VERSION 5.7 ;
  NOWIREEXTENSIONATPIN ON ;
  DIVIDERCHAR "/" ;
  BUSBITCHARS "[]" ;
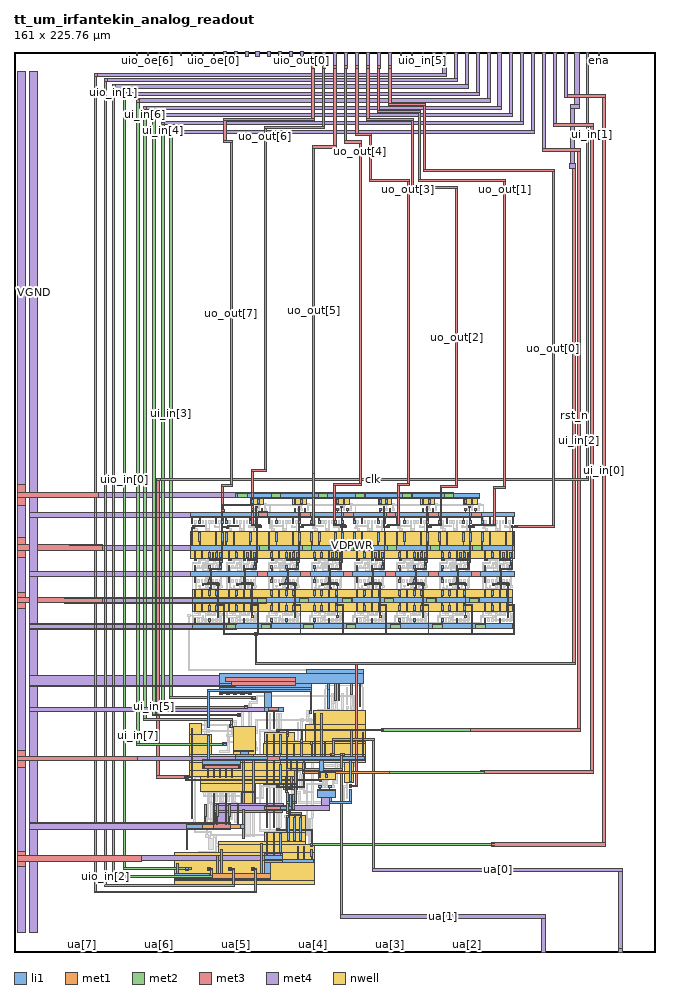
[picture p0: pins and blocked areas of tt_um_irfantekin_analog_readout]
MACRO tt_um_irfantekin_analog_readout
  CLASS BLOCK ;
  FOREIGN tt_um_irfantekin_analog_readout ;
  ORIGIN 0.000 0.000 ;
  SIZE 161.000 BY 225.760 ;
  PIN clk
    DIRECTION INPUT ;
    USE SIGNAL ;
    ANTENNAGATEAREA 0.300000 ;
    ANTENNADIFFAREA 13.200000 ;
    PORT
      LAYER li1 ;
        RECT 42.850 44.050 43.650 44.250 ;
        RECT 44.450 44.050 44.850 56.150 ;
        RECT 42.850 43.650 44.850 44.050 ;
        RECT 42.850 43.450 43.650 43.650 ;
        RECT 44.450 33.550 44.850 43.650 ;
        RECT 76.860 43.250 77.260 43.350 ;
        RECT 76.260 43.050 77.260 43.250 ;
        RECT 76.860 42.950 77.260 43.050 ;
      LAYER met1 ;
        RECT 42.850 43.450 43.650 44.250 ;
        RECT 76.550 42.750 77.250 43.350 ;
      LAYER met2 ;
        RECT 42.850 43.450 43.650 44.250 ;
        RECT 76.650 42.750 77.150 43.350 ;
      LAYER met3 ;
        RECT 35.800 118.300 36.700 118.900 ;
        RECT 35.800 44.200 36.600 118.300 ;
        RECT 42.850 44.200 43.650 44.250 ;
        RECT 35.800 43.500 43.650 44.200 ;
        RECT 42.850 43.450 43.650 43.500 ;
        RECT 43.050 43.350 43.650 43.450 ;
        RECT 43.050 43.050 77.250 43.350 ;
        RECT 76.550 42.750 77.250 43.050 ;
      LAYER met4 ;
        RECT 143.700 118.900 144.200 225.750 ;
        RECT 35.900 118.300 144.200 118.900 ;
        RECT 42.850 43.450 43.650 44.250 ;
    END
  END clk
  PIN ena
    DIRECTION INPUT ;
    USE SIGNAL ;
    PORT
      LAYER met4 ;
        RECT 146.590 224.760 146.890 225.760 ;
    END
  END ena
  PIN rst_n
    DIRECTION INPUT ;
    USE SIGNAL ;
    ANTENNAGATEAREA 19.500000 ;
    PORT
      LAYER li1 ;
        RECT 47.260 92.000 47.660 92.400 ;
        RECT 50.860 91.900 51.460 92.500 ;
        RECT 55.860 92.000 56.260 92.400 ;
        RECT 59.460 91.900 60.060 92.500 ;
        RECT 66.560 92.000 66.960 92.400 ;
        RECT 70.160 91.900 70.760 92.500 ;
        RECT 77.260 92.000 77.660 92.400 ;
        RECT 80.860 91.900 81.460 92.500 ;
        RECT 87.960 92.000 88.360 92.400 ;
        RECT 91.560 91.900 92.160 92.500 ;
        RECT 98.660 92.000 99.060 92.400 ;
        RECT 102.260 91.900 102.860 92.500 ;
        RECT 109.360 92.000 109.760 92.400 ;
        RECT 112.960 91.900 113.560 92.500 ;
        RECT 120.060 92.000 120.460 92.400 ;
        RECT 123.660 91.900 124.260 92.500 ;
        RECT 50.960 84.000 51.360 84.400 ;
        RECT 59.560 84.000 59.960 84.400 ;
        RECT 70.260 84.000 70.660 84.400 ;
        RECT 80.960 84.000 81.360 84.400 ;
        RECT 91.660 84.000 92.060 84.400 ;
        RECT 102.360 84.000 102.760 84.400 ;
        RECT 113.060 84.000 113.460 84.400 ;
        RECT 123.760 84.000 124.160 84.400 ;
        RECT 84.050 41.350 84.650 41.950 ;
      LAYER met1 ;
        RECT 48.560 92.500 49.060 92.700 ;
        RECT 57.160 92.500 57.660 92.700 ;
        RECT 67.860 92.500 68.360 92.700 ;
        RECT 78.560 92.500 79.060 92.700 ;
        RECT 89.260 92.500 89.760 92.700 ;
        RECT 99.960 92.500 100.460 92.700 ;
        RECT 110.660 92.500 111.160 92.700 ;
        RECT 121.360 92.500 121.860 92.700 ;
        RECT 47.360 92.400 49.060 92.500 ;
        RECT 47.260 92.300 49.060 92.400 ;
        RECT 47.260 92.000 47.660 92.300 ;
        RECT 48.560 92.200 49.060 92.300 ;
        RECT 50.860 91.900 51.460 92.500 ;
        RECT 55.960 92.400 57.660 92.500 ;
        RECT 55.860 92.300 57.660 92.400 ;
        RECT 55.860 92.000 56.260 92.300 ;
        RECT 57.160 92.200 57.660 92.300 ;
        RECT 59.460 91.900 60.060 92.500 ;
        RECT 66.660 92.400 68.360 92.500 ;
        RECT 66.560 92.300 68.360 92.400 ;
        RECT 66.560 92.000 66.960 92.300 ;
        RECT 67.860 92.200 68.360 92.300 ;
        RECT 70.160 91.900 70.760 92.500 ;
        RECT 77.360 92.400 79.060 92.500 ;
        RECT 77.260 92.300 79.060 92.400 ;
        RECT 77.260 92.000 77.660 92.300 ;
        RECT 78.560 92.200 79.060 92.300 ;
        RECT 80.860 91.900 81.460 92.500 ;
        RECT 88.060 92.400 89.760 92.500 ;
        RECT 87.960 92.300 89.760 92.400 ;
        RECT 87.960 92.000 88.360 92.300 ;
        RECT 89.260 92.200 89.760 92.300 ;
        RECT 91.560 91.900 92.160 92.500 ;
        RECT 98.760 92.400 100.460 92.500 ;
        RECT 98.660 92.300 100.460 92.400 ;
        RECT 98.660 92.000 99.060 92.300 ;
        RECT 99.960 92.200 100.460 92.300 ;
        RECT 102.260 91.900 102.860 92.500 ;
        RECT 109.460 92.400 111.160 92.500 ;
        RECT 109.360 92.300 111.160 92.400 ;
        RECT 109.360 92.000 109.760 92.300 ;
        RECT 110.660 92.200 111.160 92.300 ;
        RECT 112.960 91.900 113.560 92.500 ;
        RECT 120.160 92.400 121.860 92.500 ;
        RECT 120.060 92.300 121.860 92.400 ;
        RECT 120.060 92.000 120.460 92.300 ;
        RECT 121.360 92.200 121.860 92.300 ;
        RECT 123.660 91.900 124.260 92.500 ;
        RECT 51.060 87.200 51.260 91.900 ;
        RECT 59.660 87.200 59.860 91.900 ;
        RECT 70.360 87.200 70.560 91.900 ;
        RECT 81.060 87.200 81.260 91.900 ;
        RECT 91.760 87.200 91.960 91.900 ;
        RECT 102.460 87.200 102.660 91.900 ;
        RECT 113.160 87.200 113.360 91.900 ;
        RECT 123.860 87.200 124.060 91.900 ;
        RECT 51.060 87.000 52.860 87.200 ;
        RECT 51.060 84.400 51.260 87.000 ;
        RECT 50.960 84.000 51.360 84.400 ;
        RECT 52.660 79.900 52.860 87.000 ;
        RECT 59.660 87.000 61.260 87.200 ;
        RECT 59.660 84.400 59.860 87.000 ;
        RECT 59.560 84.000 59.960 84.400 ;
        RECT 61.060 80.100 61.260 87.000 ;
        RECT 70.360 87.000 71.960 87.200 ;
        RECT 70.360 84.400 70.560 87.000 ;
        RECT 70.260 84.000 70.660 84.400 ;
        RECT 60.450 79.900 61.260 80.100 ;
        RECT 71.760 79.900 71.960 87.000 ;
        RECT 81.060 87.000 82.660 87.200 ;
        RECT 81.060 84.400 81.260 87.000 ;
        RECT 80.960 84.000 81.360 84.400 ;
        RECT 82.460 79.900 82.660 87.000 ;
        RECT 91.760 87.000 93.360 87.200 ;
        RECT 91.760 84.400 91.960 87.000 ;
        RECT 91.660 84.000 92.060 84.400 ;
        RECT 93.160 79.900 93.360 87.000 ;
        RECT 102.460 87.000 104.060 87.200 ;
        RECT 102.460 84.400 102.660 87.000 ;
        RECT 102.360 84.000 102.760 84.400 ;
        RECT 103.860 79.900 104.060 87.000 ;
        RECT 113.160 87.000 114.960 87.200 ;
        RECT 113.160 84.400 113.360 87.000 ;
        RECT 113.060 84.000 113.460 84.400 ;
        RECT 114.760 79.900 114.960 87.000 ;
        RECT 123.860 87.000 125.560 87.200 ;
        RECT 123.860 84.400 124.060 87.000 ;
        RECT 123.760 84.000 124.160 84.400 ;
        RECT 125.360 79.900 125.560 87.000 ;
        RECT 52.660 79.700 125.560 79.900 ;
        RECT 60.450 79.500 61.060 79.700 ;
        RECT 84.050 41.350 84.650 41.950 ;
      LAYER met2 ;
        RECT 48.560 92.600 49.060 92.700 ;
        RECT 57.160 92.600 57.660 92.700 ;
        RECT 67.860 92.600 68.360 92.700 ;
        RECT 78.560 92.600 79.060 92.700 ;
        RECT 89.260 92.600 89.760 92.700 ;
        RECT 99.960 92.600 100.460 92.700 ;
        RECT 110.660 92.600 111.160 92.700 ;
        RECT 121.360 92.600 121.860 92.700 ;
        RECT 48.560 92.500 51.260 92.600 ;
        RECT 57.160 92.500 59.860 92.600 ;
        RECT 67.860 92.500 70.560 92.600 ;
        RECT 78.560 92.500 81.260 92.600 ;
        RECT 89.260 92.500 91.960 92.600 ;
        RECT 99.960 92.500 102.660 92.600 ;
        RECT 110.660 92.500 113.360 92.600 ;
        RECT 121.360 92.500 124.060 92.600 ;
        RECT 48.560 92.300 51.460 92.500 ;
        RECT 48.560 92.200 49.060 92.300 ;
        RECT 50.860 91.900 51.460 92.300 ;
        RECT 57.160 92.300 60.060 92.500 ;
        RECT 57.160 92.200 57.660 92.300 ;
        RECT 59.460 91.900 60.060 92.300 ;
        RECT 67.860 92.300 70.760 92.500 ;
        RECT 67.860 92.200 68.360 92.300 ;
        RECT 70.160 91.900 70.760 92.300 ;
        RECT 78.560 92.300 81.460 92.500 ;
        RECT 78.560 92.200 79.060 92.300 ;
        RECT 80.860 91.900 81.460 92.300 ;
        RECT 89.260 92.300 92.160 92.500 ;
        RECT 89.260 92.200 89.760 92.300 ;
        RECT 91.560 91.900 92.160 92.300 ;
        RECT 99.960 92.300 102.860 92.500 ;
        RECT 99.960 92.200 100.460 92.300 ;
        RECT 102.260 91.900 102.860 92.300 ;
        RECT 110.660 92.300 113.560 92.500 ;
        RECT 110.660 92.200 111.160 92.300 ;
        RECT 112.960 91.900 113.560 92.300 ;
        RECT 121.360 92.300 124.260 92.500 ;
        RECT 121.360 92.200 121.860 92.300 ;
        RECT 123.660 91.900 124.260 92.300 ;
        RECT 60.450 79.500 61.050 80.100 ;
        RECT 84.050 41.350 84.650 41.950 ;
      LAYER met3 ;
        RECT 139.400 196.650 140.900 197.800 ;
        RECT 60.450 79.500 61.050 80.100 ;
        RECT 60.550 72.550 60.950 79.500 ;
        RECT 60.550 72.500 86.150 72.550 ;
        RECT 140.200 72.500 140.900 196.650 ;
        RECT 60.550 72.150 140.900 72.500 ;
        RECT 85.750 72.000 140.900 72.150 ;
        RECT 84.050 41.850 84.650 41.950 ;
        RECT 85.750 41.850 86.150 72.000 ;
        RECT 84.050 41.450 86.150 41.850 ;
        RECT 84.050 41.350 84.650 41.450 ;
      LAYER met4 ;
        RECT 140.550 212.600 141.750 225.750 ;
        RECT 139.700 211.600 141.750 212.600 ;
        RECT 139.700 197.800 140.550 211.600 ;
        RECT 139.400 196.650 140.900 197.800 ;
    END
  END rst_n
  PIN ua[0]
    DIRECTION INOUT ;
    USE SIGNAL ;
    ANTENNAGATEAREA 1.500000 ;
    PORT
      LAYER li1 ;
        RECT 79.750 49.250 80.350 49.850 ;
      LAYER met1 ;
        RECT 79.750 49.250 80.350 49.850 ;
      LAYER met2 ;
        RECT 79.750 49.750 80.350 49.850 ;
        RECT 79.350 49.350 80.350 49.750 ;
        RECT 79.750 49.250 80.350 49.350 ;
      LAYER met3 ;
        RECT 79.700 49.200 80.400 49.900 ;
      LAYER met4 ;
        RECT 79.800 53.000 90.500 53.500 ;
        RECT 79.800 49.900 80.300 53.000 ;
        RECT 79.700 49.200 80.400 49.900 ;
        RECT 89.900 20.900 90.500 53.000 ;
        RECT 89.900 20.300 152.700 20.900 ;
        RECT 151.740 1.000 152.700 20.300 ;
        RECT 151.740 0.000 152.710 1.000 ;
        RECT 151.740 -0.010 152.700 0.000 ;
    END
  END ua[0]
  PIN ua[1]
    DIRECTION INOUT ;
    USE SIGNAL ;
    ANTENNAGATEAREA 1.500000 ;
    ANTENNADIFFAREA 16.500000 ;
    PORT
      LAYER li1 ;
        RECT 68.450 55.200 68.750 55.250 ;
        RECT 68.450 54.700 68.950 55.200 ;
        RECT 68.450 54.550 68.850 54.700 ;
        RECT 68.350 53.950 68.850 54.550 ;
        RECT 81.850 49.250 82.450 49.850 ;
        RECT 68.050 41.800 68.450 44.100 ;
        RECT 69.450 41.800 69.850 44.100 ;
        RECT 68.100 41.200 68.400 41.800 ;
        RECT 69.500 41.200 69.800 41.800 ;
        RECT 68.100 40.950 69.800 41.200 ;
        RECT 68.100 40.500 68.400 40.950 ;
        RECT 68.100 40.000 68.600 40.500 ;
        RECT 69.950 37.750 70.350 39.550 ;
        RECT 69.950 37.250 70.850 37.750 ;
        RECT 69.950 35.750 70.350 37.250 ;
        RECT 68.750 34.950 69.250 35.150 ;
        RECT 68.750 34.450 72.150 34.950 ;
        RECT 68.750 34.400 72.050 34.450 ;
        RECT 68.750 33.850 69.050 34.400 ;
        RECT 70.250 33.850 70.550 34.400 ;
        RECT 71.750 33.850 72.050 34.400 ;
        RECT 68.700 28.050 69.100 33.850 ;
        RECT 70.200 28.050 70.600 33.850 ;
        RECT 71.700 28.050 72.100 33.850 ;
      LAYER met1 ;
        RECT 68.450 54.700 68.950 55.200 ;
        RECT 81.850 49.250 82.450 49.850 ;
        RECT 68.100 40.000 68.600 40.500 ;
        RECT 70.350 37.250 70.850 37.750 ;
        RECT 68.750 34.650 69.250 35.150 ;
      LAYER met2 ;
        RECT 68.450 54.700 68.950 55.200 ;
        RECT 81.850 49.750 82.450 49.850 ;
        RECT 81.850 49.350 82.850 49.750 ;
        RECT 81.850 49.250 82.450 49.350 ;
        RECT 68.100 40.050 68.600 40.500 ;
        RECT 68.100 40.000 68.750 40.050 ;
        RECT 68.250 37.750 68.750 40.000 ;
        RECT 68.250 37.250 70.850 37.750 ;
        RECT 68.250 35.150 68.750 37.250 ;
        RECT 68.250 34.750 69.250 35.150 ;
        RECT 68.750 34.650 69.250 34.750 ;
      LAYER met3 ;
        RECT 68.450 54.700 68.950 55.200 ;
        RECT 81.850 49.250 82.450 49.850 ;
        RECT 68.100 40.000 68.600 40.500 ;
        RECT 70.350 37.250 70.850 37.750 ;
        RECT 68.750 34.650 69.250 35.150 ;
      LAYER met4 ;
        RECT 68.300 54.700 68.950 55.200 ;
        RECT 68.300 46.150 68.700 54.700 ;
        RECT 81.850 49.400 82.450 49.850 ;
        RECT 81.850 49.250 82.500 49.400 ;
        RECT 81.900 46.150 82.500 49.250 ;
        RECT 68.300 45.650 82.500 46.150 ;
        RECT 68.300 40.500 68.700 45.650 ;
        RECT 68.100 40.000 68.700 40.500 ;
        RECT 68.300 39.950 68.700 40.000 ;
        RECT 70.450 37.800 70.850 45.650 ;
        RECT 70.400 37.750 70.900 37.800 ;
        RECT 70.350 37.250 70.900 37.750 ;
        RECT 70.400 37.200 70.900 37.250 ;
        RECT 68.750 34.650 69.250 35.150 ;
        RECT 81.900 9.300 82.500 45.650 ;
        RECT 81.900 8.300 133.400 9.300 ;
        RECT 132.400 0.000 133.400 8.300 ;
    END
  END ua[1]
  PIN ua[2]
    DIRECTION INOUT ;
    USE SIGNAL ;
    PORT
      LAYER met4 ;
        RECT 113.170 0.000 114.070 1.000 ;
    END
  END ua[2]
  PIN ua[3]
    DIRECTION INOUT ;
    USE SIGNAL ;
    PORT
      LAYER met4 ;
        RECT 93.850 0.000 94.750 1.000 ;
    END
  END ua[3]
  PIN ua[4]
    DIRECTION INOUT ;
    USE SIGNAL ;
    PORT
      LAYER met4 ;
        RECT 74.530 0.000 75.430 1.000 ;
    END
  END ua[4]
  PIN ua[5]
    DIRECTION INOUT ;
    USE SIGNAL ;
    PORT
      LAYER met4 ;
        RECT 55.210 0.000 56.110 1.000 ;
    END
  END ua[5]
  PIN ua[6]
    DIRECTION INOUT ;
    USE SIGNAL ;
    PORT
      LAYER met4 ;
        RECT 35.890 0.000 36.790 1.000 ;
    END
  END ua[6]
  PIN ua[7]
    DIRECTION INOUT ;
    USE SIGNAL ;
    PORT
      LAYER met4 ;
        RECT 16.570 0.000 17.470 1.000 ;
    END
  END ua[7]
  PIN ui_in[0]
    DIRECTION INPUT ;
    USE SIGNAL ;
    ANTENNAGATEAREA 2.980000 ;
    PORT
      LAYER li1 ;
        RECT 66.060 30.450 66.560 30.950 ;
        RECT 74.300 26.550 75.000 27.250 ;
      LAYER met1 ;
        RECT 65.950 30.850 66.560 30.950 ;
        RECT 65.950 30.500 74.950 30.850 ;
        RECT 65.950 30.450 66.560 30.500 ;
        RECT 74.600 27.250 74.950 30.500 ;
        RECT 74.300 26.550 75.000 27.250 ;
      LAYER met2 ;
        RECT 74.300 27.200 75.000 27.250 ;
        RECT 119.700 27.200 120.600 27.400 ;
        RECT 74.300 26.600 120.600 27.200 ;
        RECT 74.300 26.550 75.000 26.600 ;
        RECT 119.700 26.500 120.600 26.600 ;
      LAYER met3 ;
        RECT 138.100 214.300 148.400 215.100 ;
        RECT 147.500 27.400 148.400 214.300 ;
        RECT 119.700 26.500 148.400 27.400 ;
      LAYER met4 ;
        RECT 138.100 214.300 138.800 225.750 ;
    END
  END ui_in[0]
  PIN ui_in[1]
    DIRECTION INPUT ;
    USE SIGNAL ;
    ANTENNAGATEAREA 2.980000 ;
    PORT
      LAYER li1 ;
        RECT 72.250 44.800 72.950 45.500 ;
        RECT 66.060 41.150 66.560 41.650 ;
      LAYER met1 ;
        RECT 72.250 45.400 72.950 45.500 ;
        RECT 72.250 44.900 94.200 45.400 ;
        RECT 72.250 44.800 72.950 44.900 ;
        RECT 93.600 44.800 94.200 44.900 ;
        RECT 65.950 41.550 66.560 41.650 ;
        RECT 72.600 41.550 72.900 44.800 ;
        RECT 65.950 41.250 72.900 41.550 ;
        RECT 66.060 41.150 66.560 41.250 ;
      LAYER met2 ;
        RECT 72.250 44.800 72.950 45.500 ;
        RECT 117.100 45.400 118.000 45.600 ;
        RECT 93.600 44.800 118.000 45.400 ;
        RECT 117.100 44.700 118.000 44.800 ;
      LAYER met3 ;
        RECT 135.400 207.000 145.400 207.800 ;
        RECT 144.500 45.600 145.400 207.000 ;
        RECT 117.100 44.700 145.400 45.600 ;
      LAYER met4 ;
        RECT 135.400 207.000 136.100 225.750 ;
    END
  END ui_in[1]
  PIN ui_in[2]
    DIRECTION INPUT ;
    USE SIGNAL ;
    ANTENNAGATEAREA 2.980000 ;
    PORT
      LAYER li1 ;
        RECT 66.060 55.350 66.560 55.850 ;
        RECT 71.750 52.650 72.350 53.350 ;
      LAYER met1 ;
        RECT 92.200 55.900 92.800 56.000 ;
        RECT 66.000 55.850 92.800 55.900 ;
        RECT 65.950 55.500 92.800 55.850 ;
        RECT 65.950 55.350 66.560 55.500 ;
        RECT 72.050 53.350 72.300 55.500 ;
        RECT 92.200 55.400 92.800 55.500 ;
        RECT 71.750 52.650 72.350 53.350 ;
      LAYER met2 ;
        RECT 113.700 56.000 114.600 56.100 ;
        RECT 92.200 55.400 114.600 56.000 ;
        RECT 113.700 55.200 114.600 55.400 ;
        RECT 71.750 52.650 72.350 53.350 ;
      LAYER met3 ;
        RECT 132.600 200.700 142.200 201.500 ;
        RECT 141.300 56.100 142.200 200.700 ;
        RECT 113.700 55.200 142.200 56.100 ;
      LAYER met4 ;
        RECT 132.600 200.700 133.300 225.750 ;
    END
  END ui_in[2]
  PIN ui_in[3]
    DIRECTION INPUT ;
    USE SIGNAL ;
    ANTENNAGATEAREA 2.000000 ;
    PORT
      LAYER li1 ;
        RECT 59.800 63.350 60.500 64.050 ;
      LAYER met1 ;
        RECT 59.650 64.050 60.400 64.100 ;
        RECT 59.650 63.400 60.500 64.050 ;
        RECT 59.800 63.350 60.500 63.400 ;
      LAYER met2 ;
        RECT 39.100 206.000 39.600 206.100 ;
        RECT 39.100 64.000 39.700 206.000 ;
        RECT 59.800 64.000 60.500 64.050 ;
        RECT 39.100 63.500 60.500 64.000 ;
        RECT 59.800 63.350 60.500 63.500 ;
      LAYER met3 ;
        RECT 39.000 205.300 39.800 206.100 ;
      LAYER met4 ;
        RECT 129.800 206.100 130.500 225.750 ;
        RECT 39.000 205.300 130.500 206.100 ;
    END
  END ui_in[3]
  PIN ui_in[4]
    DIRECTION INPUT ;
    USE SIGNAL ;
    ANTENNAGATEAREA 3.500000 ;
    PORT
      LAYER li1 ;
        RECT 57.900 61.050 58.600 61.750 ;
      LAYER met1 ;
        RECT 57.800 61.750 58.550 61.800 ;
        RECT 57.800 61.100 58.600 61.750 ;
        RECT 57.900 61.050 58.600 61.100 ;
      LAYER met2 ;
        RECT 37.100 208.100 37.600 208.300 ;
        RECT 37.100 61.700 37.700 208.100 ;
        RECT 57.900 61.700 58.600 61.750 ;
        RECT 37.100 61.200 58.600 61.700 ;
        RECT 57.900 61.050 58.600 61.200 ;
      LAYER met3 ;
        RECT 37.000 207.500 37.800 208.300 ;
      LAYER met4 ;
        RECT 127.000 208.300 127.800 225.750 ;
        RECT 37.000 207.500 127.800 208.300 ;
    END
  END ui_in[4]
  PIN ui_in[5]
    DIRECTION INPUT ;
    USE SIGNAL ;
    ANTENNAGATEAREA 6.500000 ;
    PORT
      LAYER li1 ;
        RECT 56.100 59.050 56.800 59.750 ;
      LAYER met1 ;
        RECT 55.950 59.750 56.700 59.800 ;
        RECT 55.950 59.100 56.800 59.750 ;
        RECT 56.100 59.050 56.800 59.100 ;
      LAYER met2 ;
        RECT 34.800 210.200 35.300 210.300 ;
        RECT 34.800 59.700 35.400 210.200 ;
        RECT 56.100 59.700 56.800 59.750 ;
        RECT 34.800 59.200 56.800 59.700 ;
        RECT 56.100 59.050 56.800 59.200 ;
      LAYER met3 ;
        RECT 34.700 209.500 35.500 210.300 ;
      LAYER met4 ;
        RECT 124.200 210.300 125.100 225.750 ;
        RECT 34.700 209.500 125.100 210.300 ;
    END
  END ui_in[5]
  PIN ui_in[6]
    DIRECTION INPUT ;
    USE SIGNAL ;
    ANTENNAGATEAREA 10.000000 ;
    PORT
      LAYER li1 ;
        RECT 54.200 56.350 54.900 57.050 ;
      LAYER met1 ;
        RECT 54.100 57.050 54.850 57.100 ;
        RECT 54.100 56.400 54.900 57.050 ;
        RECT 54.200 56.350 54.900 56.400 ;
      LAYER met2 ;
        RECT 32.600 212.000 33.100 212.200 ;
        RECT 32.600 58.500 33.200 212.000 ;
        RECT 32.600 58.000 54.700 58.500 ;
        RECT 54.200 57.050 54.700 58.000 ;
        RECT 54.200 56.350 54.900 57.050 ;
      LAYER met3 ;
        RECT 32.500 211.400 33.300 212.200 ;
      LAYER met4 ;
        RECT 121.400 212.200 122.300 225.750 ;
        RECT 32.500 211.400 122.300 212.200 ;
    END
  END ui_in[6]
  PIN ui_in[7]
    DIRECTION INPUT ;
    USE SIGNAL ;
    ANTENNAGATEAREA 14.000000 ;
    PORT
      LAYER li1 ;
        RECT 52.500 51.750 53.200 52.450 ;
      LAYER met1 ;
        RECT 52.350 52.450 53.100 52.500 ;
        RECT 52.350 51.800 53.200 52.450 ;
        RECT 52.500 51.750 53.200 51.800 ;
      LAYER met2 ;
        RECT 30.800 213.800 31.300 214.000 ;
        RECT 30.800 52.400 31.400 213.800 ;
        RECT 52.500 52.400 53.200 52.450 ;
        RECT 30.800 51.900 53.200 52.400 ;
        RECT 52.500 51.750 53.200 51.900 ;
      LAYER met3 ;
        RECT 30.700 213.200 31.500 214.000 ;
      LAYER met4 ;
        RECT 118.700 214.000 119.500 225.750 ;
        RECT 30.700 213.200 119.500 214.000 ;
    END
  END ui_in[7]
  PIN uio_in[0]
    DIRECTION INPUT ;
    USE SIGNAL ;
    ANTENNAGATEAREA 4.000000 ;
    PORT
      LAYER li1 ;
        RECT 43.000 20.500 43.700 21.200 ;
      LAYER met1 ;
        RECT 42.950 20.500 43.700 21.200 ;
      LAYER met2 ;
        RECT 27.500 21.100 28.000 215.700 ;
        RECT 43.000 21.100 43.700 21.200 ;
        RECT 27.500 20.600 44.400 21.100 ;
        RECT 43.000 20.500 43.700 20.600 ;
      LAYER met3 ;
        RECT 27.400 214.900 28.200 215.700 ;
      LAYER met4 ;
        RECT 115.900 215.700 116.800 225.750 ;
        RECT 27.400 214.900 116.800 215.700 ;
    END
  END uio_in[0]
  PIN uio_in[1]
    DIRECTION INPUT ;
    USE SIGNAL ;
    ANTENNAGATEAREA 12.000000 ;
    PORT
      LAYER li1 ;
        RECT 48.500 20.500 49.200 21.200 ;
      LAYER met1 ;
        RECT 48.450 20.500 49.200 21.200 ;
      LAYER met2 ;
        RECT 24.800 19.100 25.300 217.500 ;
        RECT 48.500 21.000 49.200 21.200 ;
        RECT 48.500 20.700 49.900 21.000 ;
        RECT 48.500 20.500 49.200 20.700 ;
        RECT 49.350 19.100 49.850 20.700 ;
        RECT 24.800 18.600 49.850 19.100 ;
      LAYER met3 ;
        RECT 24.700 216.700 25.500 217.500 ;
      LAYER met4 ;
        RECT 113.200 217.500 114.000 225.750 ;
        RECT 24.700 216.700 114.000 217.500 ;
    END
  END uio_in[1]
  PIN uio_in[2]
    DIRECTION INPUT ;
    USE SIGNAL ;
    ANTENNAGATEAREA 17.199999 ;
    PORT
      LAYER li1 ;
        RECT 53.900 20.500 54.600 21.200 ;
      LAYER met1 ;
        RECT 53.900 20.500 54.650 21.200 ;
      LAYER met2 ;
        RECT 22.700 17.000 23.200 219.100 ;
        RECT 53.900 21.000 54.600 21.200 ;
        RECT 53.900 20.700 55.300 21.000 ;
        RECT 53.900 20.500 54.600 20.700 ;
        RECT 54.800 17.000 55.300 20.700 ;
        RECT 22.700 16.500 55.300 17.000 ;
      LAYER met3 ;
        RECT 22.600 218.300 23.400 219.100 ;
      LAYER met4 ;
        RECT 110.400 219.100 111.300 225.750 ;
        RECT 22.600 218.300 111.300 219.100 ;
    END
  END uio_in[2]
  PIN uio_in[3]
    DIRECTION INPUT ;
    USE SIGNAL ;
    ANTENNAGATEAREA 24.000000 ;
    PORT
      LAYER li1 ;
        RECT 59.500 20.500 60.200 21.200 ;
      LAYER met1 ;
        RECT 59.500 20.500 60.250 21.200 ;
      LAYER met2 ;
        RECT 20.200 15.300 20.700 220.300 ;
        RECT 59.500 21.000 60.200 21.200 ;
        RECT 59.500 20.700 60.900 21.000 ;
        RECT 59.500 20.500 60.200 20.700 ;
        RECT 60.400 15.300 60.900 20.700 ;
        RECT 20.200 14.800 60.900 15.300 ;
      LAYER met3 ;
        RECT 20.100 219.500 20.900 220.300 ;
      LAYER met4 ;
        RECT 107.600 220.300 108.500 225.750 ;
        RECT 20.100 219.500 108.500 220.300 ;
    END
  END uio_in[3]
  PIN uio_in[4]
    DIRECTION INPUT ;
    USE SIGNAL ;
    PORT
      LAYER met4 ;
        RECT 104.900 224.450 105.700 225.750 ;
    END
  END uio_in[4]
  PIN uio_in[5]
    DIRECTION INPUT ;
    USE SIGNAL ;
    PORT
      LAYER met4 ;
        RECT 102.430 224.760 102.730 225.750 ;
    END
  END uio_in[5]
  PIN uio_in[6]
    DIRECTION INPUT ;
    USE SIGNAL ;
    PORT
      LAYER met4 ;
        RECT 99.670 224.760 99.970 225.750 ;
    END
  END uio_in[6]
  PIN uio_in[7]
    DIRECTION INPUT ;
    USE SIGNAL ;
    PORT
      LAYER met4 ;
        RECT 96.910 224.760 97.210 225.750 ;
    END
  END uio_in[7]
  PIN uio_oe[0]
    DIRECTION OUTPUT ;
    USE SIGNAL ;
    PORT
      LAYER met4 ;
        RECT 49.990 224.760 50.290 225.760 ;
    END
  END uio_oe[0]
  PIN uio_oe[1]
    DIRECTION OUTPUT ;
    USE SIGNAL ;
    PORT
      LAYER met4 ;
        RECT 47.230 224.760 47.530 225.760 ;
    END
  END uio_oe[1]
  PIN uio_oe[2]
    DIRECTION OUTPUT ;
    USE SIGNAL ;
    PORT
      LAYER met4 ;
        RECT 44.470 224.760 44.770 225.760 ;
    END
  END uio_oe[2]
  PIN uio_oe[3]
    DIRECTION OUTPUT ;
    USE SIGNAL ;
    PORT
      LAYER met4 ;
        RECT 41.710 224.760 42.010 225.760 ;
    END
  END uio_oe[3]
  PIN uio_oe[4]
    DIRECTION OUTPUT ;
    USE SIGNAL ;
    PORT
      LAYER met4 ;
        RECT 38.950 224.760 39.250 225.760 ;
    END
  END uio_oe[4]
  PIN uio_oe[5]
    DIRECTION OUTPUT ;
    USE SIGNAL ;
    PORT
      LAYER met4 ;
        RECT 36.190 224.760 36.490 225.760 ;
    END
  END uio_oe[5]
  PIN uio_oe[6]
    DIRECTION OUTPUT ;
    USE SIGNAL ;
    PORT
      LAYER met4 ;
        RECT 33.430 224.760 33.730 225.760 ;
    END
  END uio_oe[6]
  PIN uio_oe[7]
    DIRECTION OUTPUT ;
    USE SIGNAL ;
    PORT
      LAYER met4 ;
        RECT 30.670 224.760 30.970 225.760 ;
    END
  END uio_oe[7]
  PIN uio_out[0]
    DIRECTION OUTPUT ;
    USE SIGNAL ;
    PORT
      LAYER met4 ;
        RECT 71.800 224.700 72.600 226.000 ;
    END
  END uio_out[0]
  PIN uio_out[1]
    DIRECTION OUTPUT ;
    USE SIGNAL ;
    PORT
      LAYER met4 ;
        RECT 69.000 224.700 69.800 226.000 ;
    END
  END uio_out[1]
  PIN uio_out[2]
    DIRECTION OUTPUT ;
    USE SIGNAL ;
    PORT
      LAYER met4 ;
        RECT 66.300 224.700 67.100 226.000 ;
    END
  END uio_out[2]
  PIN uio_out[3]
    DIRECTION OUTPUT ;
    USE SIGNAL ;
    PORT
      LAYER met4 ;
        RECT 63.500 224.700 64.300 226.000 ;
    END
  END uio_out[3]
  PIN uio_out[4]
    DIRECTION OUTPUT ;
    USE SIGNAL ;
    PORT
      LAYER met4 ;
        RECT 60.700 224.700 61.500 226.000 ;
    END
  END uio_out[4]
  PIN uio_out[5]
    DIRECTION OUTPUT ;
    USE SIGNAL ;
    PORT
      LAYER met4 ;
        RECT 58.000 224.700 58.800 226.000 ;
    END
  END uio_out[5]
  PIN uio_out[6]
    DIRECTION OUTPUT ;
    USE SIGNAL ;
    PORT
      LAYER met4 ;
        RECT 55.200 224.700 56.000 226.000 ;
    END
  END uio_out[6]
  PIN uio_out[7]
    DIRECTION OUTPUT ;
    USE SIGNAL ;
    PORT
      LAYER met4 ;
        RECT 52.500 224.700 53.300 226.000 ;
    END
  END uio_out[7]
  PIN uo_out[0]
    DIRECTION OUTPUT ;
    USE SIGNAL ;
    ANTENNAGATEAREA 2.150000 ;
    ANTENNADIFFAREA 2.400000 ;
    PORT
      LAYER li1 ;
        RECT 124.760 106.500 125.160 106.900 ;
        RECT 122.560 98.900 122.960 100.200 ;
        RECT 124.360 98.900 124.760 100.200 ;
        RECT 122.660 98.500 122.860 98.900 ;
        RECT 124.460 98.500 124.660 98.900 ;
        RECT 122.660 98.300 124.660 98.500 ;
        RECT 124.460 98.200 124.660 98.300 ;
        RECT 124.460 97.600 125.060 98.200 ;
        RECT 124.460 96.900 124.660 97.600 ;
        RECT 124.360 96.100 124.760 96.900 ;
        RECT 121.960 91.100 122.360 91.500 ;
      LAYER met1 ;
        RECT 124.760 106.800 125.160 106.900 ;
        RECT 125.500 106.800 126.200 107.000 ;
        RECT 124.760 106.600 126.200 106.800 ;
        RECT 124.760 106.500 125.160 106.600 ;
        RECT 124.960 98.200 125.160 106.500 ;
        RECT 125.500 106.400 126.200 106.600 ;
        RECT 124.460 97.600 125.160 98.200 ;
        RECT 124.760 96.100 124.960 97.600 ;
        RECT 122.060 95.900 124.960 96.100 ;
        RECT 122.060 91.500 122.260 95.900 ;
        RECT 121.960 91.100 122.360 91.500 ;
      LAYER met2 ;
        RECT 125.500 106.400 126.200 107.000 ;
      LAYER met3 ;
        RECT 93.900 221.600 94.700 222.400 ;
        RECT 94.000 212.900 94.600 221.600 ;
        RECT 94.000 212.400 103.100 212.900 ;
        RECT 102.600 196.200 103.100 212.400 ;
        RECT 102.600 195.700 135.500 196.200 ;
        RECT 125.500 106.900 126.200 107.000 ;
        RECT 135.000 106.900 135.500 195.700 ;
        RECT 125.500 106.500 135.500 106.900 ;
        RECT 125.500 106.400 126.200 106.500 ;
      LAYER met4 ;
        RECT 93.900 221.600 94.700 225.750 ;
    END
  END uo_out[0]
  PIN uo_out[1]
    DIRECTION OUTPUT ;
    USE SIGNAL ;
    ANTENNAGATEAREA 2.530000 ;
    ANTENNADIFFAREA 2.400000 ;
    PORT
      LAYER li1 ;
        RECT 114.060 111.400 114.460 111.800 ;
        RECT 114.060 106.500 114.460 106.900 ;
        RECT 111.860 98.900 112.260 100.200 ;
        RECT 113.660 98.900 114.060 100.200 ;
        RECT 111.960 98.500 112.160 98.900 ;
        RECT 113.760 98.500 113.960 98.900 ;
        RECT 111.960 98.300 113.960 98.500 ;
        RECT 113.760 98.200 113.960 98.300 ;
        RECT 113.760 97.600 114.360 98.200 ;
        RECT 113.760 96.900 113.960 97.600 ;
        RECT 113.660 96.100 114.060 96.900 ;
        RECT 111.260 91.100 111.660 91.500 ;
      LAYER met1 ;
        RECT 114.060 111.400 114.460 111.800 ;
        RECT 114.160 106.900 114.360 111.400 ;
        RECT 114.060 106.800 114.460 106.900 ;
        RECT 114.800 106.800 115.500 107.000 ;
        RECT 114.060 106.600 115.500 106.800 ;
        RECT 114.060 106.500 114.460 106.600 ;
        RECT 114.260 98.200 114.460 106.500 ;
        RECT 114.800 106.400 115.500 106.600 ;
        RECT 113.760 97.600 114.460 98.200 ;
        RECT 114.060 96.100 114.260 97.600 ;
        RECT 111.360 95.900 114.260 96.100 ;
        RECT 111.360 91.500 111.560 95.900 ;
        RECT 111.260 91.100 111.660 91.500 ;
      LAYER met2 ;
        RECT 114.800 106.400 115.500 107.000 ;
      LAYER met3 ;
        RECT 91.100 221.600 91.900 222.400 ;
        RECT 91.200 211.200 91.800 221.600 ;
        RECT 91.200 210.700 101.900 211.200 ;
        RECT 101.400 193.900 101.900 210.700 ;
        RECT 101.400 193.400 123.300 193.900 ;
        RECT 122.800 116.800 123.300 193.400 ;
        RECT 120.400 116.300 123.300 116.800 ;
        RECT 120.400 107.300 120.800 116.300 ;
        RECT 115.000 107.000 120.800 107.300 ;
        RECT 114.800 106.900 120.800 107.000 ;
        RECT 114.800 106.400 115.500 106.900 ;
      LAYER met4 ;
        RECT 91.100 221.600 91.900 225.750 ;
    END
  END uo_out[1]
  PIN uo_out[2]
    DIRECTION OUTPUT ;
    USE SIGNAL ;
    ANTENNAGATEAREA 2.530000 ;
    ANTENNADIFFAREA 2.400000 ;
    PORT
      LAYER li1 ;
        RECT 103.360 111.400 103.760 111.800 ;
        RECT 103.360 106.500 103.760 106.900 ;
        RECT 101.160 98.900 101.560 100.200 ;
        RECT 102.960 98.900 103.360 100.200 ;
        RECT 101.260 98.500 101.460 98.900 ;
        RECT 103.060 98.500 103.260 98.900 ;
        RECT 101.260 98.300 103.260 98.500 ;
        RECT 103.060 98.200 103.260 98.300 ;
        RECT 103.060 97.600 103.660 98.200 ;
        RECT 103.060 96.900 103.260 97.600 ;
        RECT 102.960 96.100 103.360 96.900 ;
        RECT 100.560 91.100 100.960 91.500 ;
      LAYER met1 ;
        RECT 103.360 111.400 103.760 111.800 ;
        RECT 103.460 106.900 103.660 111.400 ;
        RECT 103.360 106.800 103.760 106.900 ;
        RECT 104.100 106.800 104.800 107.000 ;
        RECT 103.360 106.600 104.800 106.800 ;
        RECT 103.360 106.500 103.760 106.600 ;
        RECT 103.560 98.200 103.760 106.500 ;
        RECT 104.100 106.400 104.800 106.600 ;
        RECT 103.060 97.600 103.760 98.200 ;
        RECT 103.360 96.100 103.560 97.600 ;
        RECT 100.660 95.900 103.560 96.100 ;
        RECT 100.660 91.500 100.860 95.900 ;
        RECT 100.560 91.100 100.960 91.500 ;
      LAYER met2 ;
        RECT 104.100 106.400 104.800 107.000 ;
      LAYER met3 ;
        RECT 88.400 221.600 89.200 222.400 ;
        RECT 88.500 209.100 89.100 221.600 ;
        RECT 88.500 208.600 100.300 209.100 ;
        RECT 99.800 191.900 100.300 208.600 ;
        RECT 99.800 191.400 111.300 191.900 ;
        RECT 110.800 117.100 111.300 191.400 ;
        RECT 106.900 116.600 111.300 117.100 ;
        RECT 106.900 107.300 107.300 116.600 ;
        RECT 104.300 107.000 107.300 107.300 ;
        RECT 104.100 106.900 107.300 107.000 ;
        RECT 104.100 106.400 104.800 106.900 ;
      LAYER met4 ;
        RECT 88.400 221.600 89.200 225.750 ;
    END
  END uo_out[2]
  PIN uo_out[3]
    DIRECTION OUTPUT ;
    USE SIGNAL ;
    ANTENNAGATEAREA 2.530000 ;
    ANTENNADIFFAREA 2.400000 ;
    PORT
      LAYER li1 ;
        RECT 92.660 111.400 93.060 111.800 ;
        RECT 92.660 106.500 93.060 106.900 ;
        RECT 90.460 98.900 90.860 100.200 ;
        RECT 92.260 98.900 92.660 100.200 ;
        RECT 90.560 98.500 90.760 98.900 ;
        RECT 92.360 98.500 92.560 98.900 ;
        RECT 90.560 98.300 92.560 98.500 ;
        RECT 92.360 98.200 92.560 98.300 ;
        RECT 92.360 97.600 92.960 98.200 ;
        RECT 92.360 96.900 92.560 97.600 ;
        RECT 92.260 96.100 92.660 96.900 ;
        RECT 89.860 91.100 90.260 91.500 ;
      LAYER met1 ;
        RECT 92.660 111.400 93.060 111.800 ;
        RECT 92.760 106.900 92.960 111.400 ;
        RECT 92.660 106.800 93.060 106.900 ;
        RECT 93.400 106.800 94.100 107.000 ;
        RECT 92.660 106.600 94.100 106.800 ;
        RECT 92.660 106.500 93.060 106.600 ;
        RECT 92.860 98.200 93.060 106.500 ;
        RECT 93.400 106.400 94.100 106.600 ;
        RECT 92.360 97.600 93.060 98.200 ;
        RECT 92.660 96.100 92.860 97.600 ;
        RECT 89.960 95.900 92.860 96.100 ;
        RECT 89.960 91.500 90.160 95.900 ;
        RECT 89.860 91.100 90.260 91.500 ;
      LAYER met2 ;
        RECT 93.400 106.400 94.100 107.000 ;
      LAYER met3 ;
        RECT 85.600 221.600 86.400 222.400 ;
        RECT 85.700 205.200 86.300 221.600 ;
        RECT 85.700 204.700 89.800 205.200 ;
        RECT 89.300 193.800 89.800 204.700 ;
        RECT 89.300 193.300 99.200 193.800 ;
        RECT 98.700 117.400 99.200 193.300 ;
        RECT 96.200 117.000 99.200 117.400 ;
        RECT 96.200 107.300 96.600 117.000 ;
        RECT 93.600 107.000 96.600 107.300 ;
        RECT 93.400 106.900 96.600 107.000 ;
        RECT 93.400 106.400 94.100 106.900 ;
      LAYER met4 ;
        RECT 85.600 221.600 86.400 225.750 ;
    END
  END uo_out[3]
  PIN uo_out[4]
    DIRECTION OUTPUT ;
    USE SIGNAL ;
    ANTENNAGATEAREA 2.530000 ;
    ANTENNADIFFAREA 2.400000 ;
    PORT
      LAYER li1 ;
        RECT 81.960 111.400 82.360 111.800 ;
        RECT 81.960 106.500 82.360 106.900 ;
        RECT 79.760 98.900 80.160 100.200 ;
        RECT 81.560 98.900 81.960 100.200 ;
        RECT 79.860 98.500 80.060 98.900 ;
        RECT 81.660 98.500 81.860 98.900 ;
        RECT 79.860 98.300 81.860 98.500 ;
        RECT 81.660 98.200 81.860 98.300 ;
        RECT 81.660 97.600 82.260 98.200 ;
        RECT 81.660 96.900 81.860 97.600 ;
        RECT 81.560 96.100 81.960 96.900 ;
        RECT 79.160 91.100 79.560 91.500 ;
      LAYER met1 ;
        RECT 81.960 111.400 82.360 111.800 ;
        RECT 82.060 106.900 82.260 111.400 ;
        RECT 81.960 106.800 82.360 106.900 ;
        RECT 82.700 106.800 83.400 107.000 ;
        RECT 81.960 106.600 83.400 106.800 ;
        RECT 81.960 106.500 82.360 106.600 ;
        RECT 82.160 98.200 82.360 106.500 ;
        RECT 82.700 106.400 83.400 106.600 ;
        RECT 81.660 97.600 82.360 98.200 ;
        RECT 81.960 96.100 82.160 97.600 ;
        RECT 79.260 95.900 82.160 96.100 ;
        RECT 79.260 91.500 79.460 95.900 ;
        RECT 79.160 91.100 79.560 91.500 ;
      LAYER met2 ;
        RECT 82.700 106.400 83.400 107.000 ;
      LAYER met3 ;
        RECT 82.800 221.600 83.600 222.400 ;
        RECT 82.900 203.500 83.500 221.600 ;
        RECT 82.900 202.900 87.100 203.500 ;
        RECT 86.600 117.500 87.100 202.900 ;
        RECT 80.200 116.900 87.200 117.500 ;
        RECT 80.200 107.300 80.600 116.900 ;
        RECT 80.200 107.000 83.200 107.300 ;
        RECT 80.200 106.900 83.400 107.000 ;
        RECT 82.700 106.400 83.400 106.900 ;
      LAYER met4 ;
        RECT 82.800 221.600 83.600 225.750 ;
    END
  END uo_out[4]
  PIN uo_out[5]
    DIRECTION OUTPUT ;
    USE SIGNAL ;
    ANTENNAGATEAREA 2.530000 ;
    ANTENNADIFFAREA 2.400000 ;
    PORT
      LAYER li1 ;
        RECT 71.260 111.400 71.660 111.800 ;
        RECT 71.260 106.500 71.660 106.900 ;
        RECT 69.060 98.900 69.460 100.200 ;
        RECT 70.860 98.900 71.260 100.200 ;
        RECT 69.160 98.500 69.360 98.900 ;
        RECT 70.960 98.500 71.160 98.900 ;
        RECT 69.160 98.300 71.160 98.500 ;
        RECT 70.960 98.200 71.160 98.300 ;
        RECT 70.960 97.600 71.560 98.200 ;
        RECT 70.960 96.900 71.160 97.600 ;
        RECT 70.860 96.100 71.260 96.900 ;
        RECT 68.460 91.100 68.860 91.500 ;
      LAYER met1 ;
        RECT 71.260 111.400 71.660 111.800 ;
        RECT 71.360 106.900 71.560 111.400 ;
        RECT 71.260 106.800 71.660 106.900 ;
        RECT 72.000 106.800 72.700 107.000 ;
        RECT 71.260 106.600 72.700 106.800 ;
        RECT 71.260 106.500 71.660 106.600 ;
        RECT 71.460 98.200 71.660 106.500 ;
        RECT 72.000 106.400 72.700 106.600 ;
        RECT 70.960 97.600 71.660 98.200 ;
        RECT 71.260 96.100 71.460 97.600 ;
        RECT 68.560 95.900 71.460 96.100 ;
        RECT 68.560 91.500 68.760 95.900 ;
        RECT 68.460 91.100 68.860 91.500 ;
      LAYER met2 ;
        RECT 72.000 106.400 72.700 107.000 ;
      LAYER met3 ;
        RECT 80.100 221.600 80.900 222.400 ;
        RECT 80.200 202.200 80.800 221.600 ;
        RECT 74.900 201.600 80.800 202.200 ;
        RECT 74.900 120.100 75.400 201.600 ;
        RECT 75.000 107.300 75.400 120.100 ;
        RECT 72.200 107.000 75.400 107.300 ;
        RECT 72.000 106.900 75.400 107.000 ;
        RECT 72.000 106.400 72.700 106.900 ;
      LAYER met4 ;
        RECT 80.100 221.600 80.900 225.750 ;
    END
  END uo_out[5]
  PIN uo_out[6]
    DIRECTION OUTPUT ;
    USE SIGNAL ;
    ANTENNAGATEAREA 2.530000 ;
    ANTENNADIFFAREA 2.400000 ;
    PORT
      LAYER li1 ;
        RECT 60.560 111.400 60.960 111.800 ;
        RECT 60.560 106.500 60.960 106.900 ;
        RECT 58.360 98.900 58.760 100.200 ;
        RECT 60.160 98.900 60.560 100.200 ;
        RECT 58.460 98.500 58.660 98.900 ;
        RECT 60.260 98.500 60.460 98.900 ;
        RECT 58.460 98.300 60.460 98.500 ;
        RECT 60.260 98.200 60.460 98.300 ;
        RECT 60.260 97.600 60.860 98.200 ;
        RECT 60.260 96.900 60.460 97.600 ;
        RECT 60.160 96.100 60.560 96.900 ;
        RECT 57.760 91.100 58.160 91.500 ;
      LAYER met1 ;
        RECT 60.560 111.400 60.960 111.800 ;
        RECT 60.660 106.900 60.860 111.400 ;
        RECT 60.560 106.800 60.960 106.900 ;
        RECT 61.300 106.800 62.000 107.000 ;
        RECT 60.560 106.600 62.000 106.800 ;
        RECT 60.560 106.500 60.960 106.600 ;
        RECT 60.760 98.200 60.960 106.500 ;
        RECT 61.300 106.400 62.000 106.600 ;
        RECT 60.260 97.600 60.960 98.200 ;
        RECT 60.560 96.100 60.760 97.600 ;
        RECT 57.860 95.900 60.760 96.100 ;
        RECT 57.860 91.500 58.060 95.900 ;
        RECT 57.760 91.100 58.160 91.500 ;
      LAYER met2 ;
        RECT 61.300 106.400 62.000 107.000 ;
      LAYER met3 ;
        RECT 77.300 221.600 78.100 222.400 ;
        RECT 77.400 207.000 78.000 221.600 ;
        RECT 62.800 206.500 78.000 207.000 ;
        RECT 62.800 121.000 63.300 206.500 ;
        RECT 59.500 120.500 63.300 121.000 ;
        RECT 59.500 107.300 60.000 120.500 ;
        RECT 59.500 107.000 61.800 107.300 ;
        RECT 59.500 106.900 62.000 107.000 ;
        RECT 61.300 106.400 62.000 106.900 ;
      LAYER met4 ;
        RECT 77.300 221.600 78.100 225.750 ;
    END
  END uo_out[6]
  PIN uo_out[7]
    DIRECTION OUTPUT ;
    USE SIGNAL ;
    ANTENNAGATEAREA 3.930000 ;
    ANTENNADIFFAREA 2.400000 ;
    PORT
      LAYER li1 ;
        RECT 59.760 111.900 60.160 112.300 ;
        RECT 51.960 106.500 52.360 106.900 ;
        RECT 55.960 106.700 56.360 107.100 ;
        RECT 53.360 106.200 53.760 106.600 ;
        RECT 49.760 98.900 50.160 100.200 ;
        RECT 51.560 98.900 51.960 100.200 ;
        RECT 49.860 98.500 50.060 98.900 ;
        RECT 51.660 98.500 51.860 98.900 ;
        RECT 49.860 98.300 51.860 98.500 ;
        RECT 51.660 98.200 51.860 98.300 ;
        RECT 51.660 97.600 52.260 98.200 ;
        RECT 51.660 96.900 51.860 97.600 ;
        RECT 51.560 96.100 51.960 96.900 ;
        RECT 49.160 91.100 49.560 91.500 ;
      LAYER met1 ;
        RECT 59.760 112.200 60.160 112.300 ;
        RECT 52.060 112.000 60.160 112.200 ;
        RECT 52.060 111.100 52.260 112.000 ;
        RECT 59.760 111.900 60.160 112.000 ;
        RECT 52.000 110.500 52.700 111.100 ;
        RECT 52.060 106.900 52.260 110.500 ;
        RECT 55.960 107.000 56.360 107.100 ;
        RECT 51.960 106.800 52.360 106.900 ;
        RECT 53.460 106.800 56.360 107.000 ;
        RECT 51.960 106.600 53.660 106.800 ;
        RECT 55.960 106.700 56.360 106.800 ;
        RECT 51.960 106.500 52.360 106.600 ;
        RECT 52.160 98.200 52.360 106.500 ;
        RECT 53.360 106.200 53.760 106.600 ;
        RECT 51.660 97.600 52.360 98.200 ;
        RECT 51.960 96.100 52.160 97.600 ;
        RECT 49.260 95.900 52.160 96.100 ;
        RECT 49.260 91.500 49.460 95.900 ;
        RECT 49.160 91.100 49.560 91.500 ;
      LAYER met2 ;
        RECT 52.000 110.500 52.700 111.100 ;
      LAYER met3 ;
        RECT 74.600 221.600 75.400 222.400 ;
        RECT 74.700 209.100 75.300 221.600 ;
        RECT 52.600 208.600 75.300 209.100 ;
        RECT 52.600 203.600 53.200 208.600 ;
        RECT 52.600 203.100 54.700 203.600 ;
        RECT 54.200 117.200 54.700 203.100 ;
        RECT 52.100 116.700 54.700 117.200 ;
        RECT 52.100 111.100 52.600 116.700 ;
        RECT 52.000 110.500 52.700 111.100 ;
      LAYER met4 ;
        RECT 74.600 221.600 75.400 225.750 ;
    END
  END uo_out[7]
  PIN VDPWR
    DIRECTION INOUT ;
    USE POWER ;
    PORT
      LAYER nwell ;
        RECT 59.260 113.800 116.860 115.100 ;
        RECT 59.260 112.300 62.660 113.800 ;
        RECT 69.960 112.300 73.360 113.800 ;
        RECT 80.660 112.300 84.060 113.800 ;
        RECT 91.360 112.300 94.760 113.800 ;
        RECT 102.060 112.300 105.460 113.800 ;
        RECT 112.760 112.300 116.160 113.800 ;
        RECT 44.160 98.600 125.660 105.500 ;
        RECT 44.660 85.400 125.160 91.000 ;
        RECT 44.050 54.650 46.950 57.350 ;
        RECT 75.050 57.050 88.150 60.550 ;
        RECT 44.050 49.450 49.450 54.650 ;
        RECT 55.000 49.550 60.700 56.550 ;
        RECT 67.250 54.950 70.350 55.050 ;
        RECT 62.760 52.750 70.350 54.950 ;
        RECT 73.050 52.750 88.150 57.050 ;
        RECT 62.760 52.200 88.150 52.750 ;
        RECT 62.500 49.550 88.150 52.200 ;
        RECT 55.000 49.450 88.150 49.550 ;
        RECT 44.050 47.650 88.150 49.450 ;
        RECT 44.050 45.450 73.150 47.650 ;
        RECT 44.050 44.050 71.150 45.450 ;
        RECT 46.750 42.150 71.150 44.050 ;
        RECT 76.260 43.350 80.560 45.650 ;
        RECT 82.850 42.450 85.050 47.650 ;
        RECT 46.750 40.250 60.650 42.150 ;
        RECT 62.500 42.050 71.100 42.150 ;
        RECT 67.700 40.750 71.100 42.050 ;
        RECT 57.050 40.050 60.650 40.250 ;
        RECT 57.050 37.050 60.550 40.050 ;
        RECT 68.400 30.100 73.200 34.200 ;
        RECT 66.650 30.050 73.200 30.100 ;
        RECT 62.760 27.800 73.200 30.050 ;
        RECT 51.400 27.050 73.200 27.800 ;
        RECT 51.400 25.000 75.300 27.050 ;
        RECT 40.250 17.950 75.300 25.000 ;
        RECT 40.250 17.050 75.350 17.950 ;
      LAYER li1 ;
        RECT 56.160 115.100 58.460 115.200 ;
        RECT 64.560 115.100 66.860 115.200 ;
        RECT 76.260 115.100 78.560 115.200 ;
        RECT 85.660 115.100 87.960 115.200 ;
        RECT 97.460 115.100 99.760 115.200 ;
        RECT 107.960 115.100 110.260 115.200 ;
        RECT 55.460 114.000 116.860 115.100 ;
        RECT 59.660 113.600 59.860 114.000 ;
        RECT 61.260 113.600 61.460 114.000 ;
        RECT 70.360 113.600 70.560 114.000 ;
        RECT 71.960 113.600 72.160 114.000 ;
        RECT 81.060 113.600 81.260 114.000 ;
        RECT 82.660 113.600 82.860 114.000 ;
        RECT 91.760 113.600 91.960 114.000 ;
        RECT 93.360 113.600 93.560 114.000 ;
        RECT 102.460 113.600 102.660 114.000 ;
        RECT 104.060 113.600 104.260 114.000 ;
        RECT 113.160 113.600 113.360 114.000 ;
        RECT 114.760 113.600 114.960 114.000 ;
        RECT 59.560 112.600 59.960 113.600 ;
        RECT 61.160 112.600 61.560 113.600 ;
        RECT 70.260 112.600 70.660 113.600 ;
        RECT 71.860 112.600 72.260 113.600 ;
        RECT 80.960 112.600 81.360 113.600 ;
        RECT 82.560 112.600 82.960 113.600 ;
        RECT 91.660 112.600 92.060 113.600 ;
        RECT 93.260 112.600 93.660 113.600 ;
        RECT 102.360 112.600 102.760 113.600 ;
        RECT 103.960 112.600 104.360 113.600 ;
        RECT 113.060 112.600 113.460 113.600 ;
        RECT 114.660 112.600 115.060 113.600 ;
        RECT 47.360 106.700 47.760 107.100 ;
        RECT 44.760 106.500 45.160 106.600 ;
        RECT 44.560 106.200 45.160 106.500 ;
        RECT 44.560 105.200 44.760 106.200 ;
        RECT 44.460 102.900 44.860 105.200 ;
        RECT 46.360 102.900 46.760 105.200 ;
        RECT 50.460 102.900 50.860 105.200 ;
        RECT 52.160 102.900 52.560 105.200 ;
        RECT 53.060 102.900 53.460 105.200 ;
        RECT 54.960 102.900 55.360 105.200 ;
        RECT 59.060 102.900 59.460 105.200 ;
        RECT 60.760 102.900 61.160 105.200 ;
        RECT 63.760 102.900 64.160 105.200 ;
        RECT 65.660 102.900 66.060 105.200 ;
        RECT 69.760 102.900 70.160 105.200 ;
        RECT 71.460 102.900 71.860 105.200 ;
        RECT 74.460 102.900 74.860 105.200 ;
        RECT 76.360 102.900 76.760 105.200 ;
        RECT 80.460 102.900 80.860 105.200 ;
        RECT 82.160 102.900 82.560 105.200 ;
        RECT 85.160 102.900 85.560 105.200 ;
        RECT 87.060 102.900 87.460 105.200 ;
        RECT 91.160 102.900 91.560 105.200 ;
        RECT 92.860 102.900 93.260 105.200 ;
        RECT 95.860 102.900 96.260 105.200 ;
        RECT 97.760 102.900 98.160 105.200 ;
        RECT 101.860 102.900 102.260 105.200 ;
        RECT 103.560 102.900 103.960 105.200 ;
        RECT 106.560 102.900 106.960 105.200 ;
        RECT 108.460 102.900 108.860 105.200 ;
        RECT 112.560 102.900 112.960 105.200 ;
        RECT 114.260 102.900 114.660 105.200 ;
        RECT 117.260 102.900 117.660 105.200 ;
        RECT 119.160 102.900 119.560 105.200 ;
        RECT 123.260 102.900 123.660 105.200 ;
        RECT 124.960 102.900 125.360 105.200 ;
        RECT 44.560 102.000 44.760 102.900 ;
        RECT 46.460 102.000 46.660 102.900 ;
        RECT 50.560 102.000 50.760 102.900 ;
        RECT 52.260 102.000 52.460 102.900 ;
        RECT 53.160 102.000 53.360 102.900 ;
        RECT 55.060 102.000 55.260 102.900 ;
        RECT 59.160 102.000 59.360 102.900 ;
        RECT 60.860 102.000 61.060 102.900 ;
        RECT 63.860 102.000 64.060 102.900 ;
        RECT 65.760 102.000 65.960 102.900 ;
        RECT 69.860 102.000 70.060 102.900 ;
        RECT 71.560 102.000 71.760 102.900 ;
        RECT 74.560 102.000 74.760 102.900 ;
        RECT 76.460 102.000 76.660 102.900 ;
        RECT 80.560 102.000 80.760 102.900 ;
        RECT 82.260 102.000 82.460 102.900 ;
        RECT 85.260 102.000 85.460 102.900 ;
        RECT 87.160 102.000 87.360 102.900 ;
        RECT 91.260 102.000 91.460 102.900 ;
        RECT 92.960 102.000 93.160 102.900 ;
        RECT 95.960 102.000 96.160 102.900 ;
        RECT 97.860 102.000 98.060 102.900 ;
        RECT 101.960 102.000 102.160 102.900 ;
        RECT 103.660 102.000 103.860 102.900 ;
        RECT 106.660 102.000 106.860 102.900 ;
        RECT 108.560 102.000 108.760 102.900 ;
        RECT 112.660 102.000 112.860 102.900 ;
        RECT 114.360 102.000 114.560 102.900 ;
        RECT 117.360 102.000 117.560 102.900 ;
        RECT 119.260 102.000 119.460 102.900 ;
        RECT 123.360 102.000 123.560 102.900 ;
        RECT 125.060 102.000 125.260 102.900 ;
        RECT 44.160 100.800 125.660 102.000 ;
        RECT 45.260 100.200 45.460 100.800 ;
        RECT 47.060 100.200 47.260 100.800 ;
        RECT 48.960 100.200 49.160 100.800 ;
        RECT 50.760 100.200 50.960 100.800 ;
        RECT 53.860 100.200 54.060 100.800 ;
        RECT 55.660 100.200 55.860 100.800 ;
        RECT 57.560 100.200 57.760 100.800 ;
        RECT 59.360 100.200 59.560 100.800 ;
        RECT 64.560 100.200 64.760 100.800 ;
        RECT 66.360 100.200 66.560 100.800 ;
        RECT 68.260 100.200 68.460 100.800 ;
        RECT 70.060 100.200 70.260 100.800 ;
        RECT 75.260 100.200 75.460 100.800 ;
        RECT 77.060 100.200 77.260 100.800 ;
        RECT 78.960 100.200 79.160 100.800 ;
        RECT 80.760 100.200 80.960 100.800 ;
        RECT 85.960 100.200 86.160 100.800 ;
        RECT 87.760 100.200 87.960 100.800 ;
        RECT 89.660 100.200 89.860 100.800 ;
        RECT 91.460 100.200 91.660 100.800 ;
        RECT 96.660 100.200 96.860 100.800 ;
        RECT 98.460 100.200 98.660 100.800 ;
        RECT 100.360 100.200 100.560 100.800 ;
        RECT 102.160 100.200 102.360 100.800 ;
        RECT 107.360 100.200 107.560 100.800 ;
        RECT 109.160 100.200 109.360 100.800 ;
        RECT 111.060 100.200 111.260 100.800 ;
        RECT 112.860 100.200 113.060 100.800 ;
        RECT 118.060 100.200 118.260 100.800 ;
        RECT 119.860 100.200 120.060 100.800 ;
        RECT 121.760 100.200 121.960 100.800 ;
        RECT 123.560 100.200 123.760 100.800 ;
        RECT 45.160 98.900 45.560 100.200 ;
        RECT 46.960 98.900 47.360 100.200 ;
        RECT 48.860 98.900 49.260 100.200 ;
        RECT 50.660 98.900 51.060 100.200 ;
        RECT 53.760 98.900 54.160 100.200 ;
        RECT 55.560 98.900 55.960 100.200 ;
        RECT 57.460 98.900 57.860 100.200 ;
        RECT 59.260 98.900 59.660 100.200 ;
        RECT 64.460 98.900 64.860 100.200 ;
        RECT 66.260 98.900 66.660 100.200 ;
        RECT 68.160 98.900 68.560 100.200 ;
        RECT 69.960 98.900 70.360 100.200 ;
        RECT 75.160 98.900 75.560 100.200 ;
        RECT 76.960 98.900 77.360 100.200 ;
        RECT 78.860 98.900 79.260 100.200 ;
        RECT 80.660 98.900 81.060 100.200 ;
        RECT 85.860 98.900 86.260 100.200 ;
        RECT 87.660 98.900 88.060 100.200 ;
        RECT 89.560 98.900 89.960 100.200 ;
        RECT 91.360 98.900 91.760 100.200 ;
        RECT 96.560 98.900 96.960 100.200 ;
        RECT 98.360 98.900 98.760 100.200 ;
        RECT 100.260 98.900 100.660 100.200 ;
        RECT 102.060 98.900 102.460 100.200 ;
        RECT 107.260 98.900 107.660 100.200 ;
        RECT 109.060 98.900 109.460 100.200 ;
        RECT 110.960 98.900 111.360 100.200 ;
        RECT 112.760 98.900 113.160 100.200 ;
        RECT 117.960 98.900 118.360 100.200 ;
        RECT 119.760 98.900 120.160 100.200 ;
        RECT 121.660 98.900 122.060 100.200 ;
        RECT 123.460 98.900 123.860 100.200 ;
        RECT 45.260 98.500 45.460 98.900 ;
        RECT 48.960 98.500 49.160 98.900 ;
        RECT 53.860 98.500 54.060 98.900 ;
        RECT 57.560 98.500 57.760 98.900 ;
        RECT 64.560 98.500 64.760 98.900 ;
        RECT 68.260 98.500 68.460 98.900 ;
        RECT 75.260 98.500 75.460 98.900 ;
        RECT 78.960 98.500 79.160 98.900 ;
        RECT 85.960 98.500 86.160 98.900 ;
        RECT 89.660 98.500 89.860 98.900 ;
        RECT 96.660 98.500 96.860 98.900 ;
        RECT 100.360 98.500 100.560 98.900 ;
        RECT 107.360 98.500 107.560 98.900 ;
        RECT 111.060 98.500 111.260 98.900 ;
        RECT 118.060 98.500 118.260 98.900 ;
        RECT 121.760 98.500 121.960 98.900 ;
        RECT 45.260 98.200 45.860 98.500 ;
        RECT 48.960 98.200 49.560 98.500 ;
        RECT 53.860 98.200 54.460 98.500 ;
        RECT 57.560 98.200 58.160 98.500 ;
        RECT 64.560 98.200 65.160 98.500 ;
        RECT 68.260 98.200 68.860 98.500 ;
        RECT 75.260 98.200 75.860 98.500 ;
        RECT 78.960 98.200 79.560 98.500 ;
        RECT 85.960 98.200 86.560 98.500 ;
        RECT 89.660 98.200 90.260 98.500 ;
        RECT 96.660 98.200 97.260 98.500 ;
        RECT 100.360 98.200 100.960 98.500 ;
        RECT 107.360 98.200 107.960 98.500 ;
        RECT 111.060 98.200 111.660 98.500 ;
        RECT 118.060 98.200 118.660 98.500 ;
        RECT 121.760 98.200 122.360 98.500 ;
        RECT 45.460 98.100 45.860 98.200 ;
        RECT 49.160 98.100 49.560 98.200 ;
        RECT 54.060 98.100 54.460 98.200 ;
        RECT 57.760 98.100 58.160 98.200 ;
        RECT 64.760 98.100 65.160 98.200 ;
        RECT 68.460 98.100 68.860 98.200 ;
        RECT 75.460 98.100 75.860 98.200 ;
        RECT 79.160 98.100 79.560 98.200 ;
        RECT 86.160 98.100 86.560 98.200 ;
        RECT 89.860 98.100 90.260 98.200 ;
        RECT 96.860 98.100 97.260 98.200 ;
        RECT 100.560 98.100 100.960 98.200 ;
        RECT 107.560 98.100 107.960 98.200 ;
        RECT 111.260 98.100 111.660 98.200 ;
        RECT 118.260 98.100 118.660 98.200 ;
        RECT 121.960 98.100 122.360 98.200 ;
        RECT 45.160 89.400 45.560 90.700 ;
        RECT 46.960 89.400 47.360 90.700 ;
        RECT 48.860 89.400 49.260 90.700 ;
        RECT 50.660 89.400 51.060 90.700 ;
        RECT 53.760 89.400 54.160 90.700 ;
        RECT 55.560 89.400 55.960 90.700 ;
        RECT 57.460 89.400 57.860 90.700 ;
        RECT 59.260 89.400 59.660 90.700 ;
        RECT 64.460 89.400 64.860 90.700 ;
        RECT 66.260 89.400 66.660 90.700 ;
        RECT 68.160 89.400 68.560 90.700 ;
        RECT 69.960 89.400 70.360 90.700 ;
        RECT 75.160 89.400 75.560 90.700 ;
        RECT 76.960 89.400 77.360 90.700 ;
        RECT 78.860 89.400 79.260 90.700 ;
        RECT 80.660 89.400 81.060 90.700 ;
        RECT 85.860 89.400 86.260 90.700 ;
        RECT 87.660 89.400 88.060 90.700 ;
        RECT 89.560 89.400 89.960 90.700 ;
        RECT 91.360 89.400 91.760 90.700 ;
        RECT 96.560 89.400 96.960 90.700 ;
        RECT 98.360 89.400 98.760 90.700 ;
        RECT 100.260 89.400 100.660 90.700 ;
        RECT 102.060 89.400 102.460 90.700 ;
        RECT 107.260 89.400 107.660 90.700 ;
        RECT 109.060 89.400 109.460 90.700 ;
        RECT 110.960 89.400 111.360 90.700 ;
        RECT 112.760 89.400 113.160 90.700 ;
        RECT 117.960 89.400 118.360 90.700 ;
        RECT 119.760 89.400 120.160 90.700 ;
        RECT 121.660 89.400 122.060 90.700 ;
        RECT 123.460 89.400 123.860 90.700 ;
        RECT 45.260 88.800 45.460 89.400 ;
        RECT 47.060 88.800 47.260 89.400 ;
        RECT 48.960 88.800 49.160 89.400 ;
        RECT 50.760 88.800 50.960 89.400 ;
        RECT 53.860 88.800 54.060 89.400 ;
        RECT 55.660 88.800 55.860 89.400 ;
        RECT 57.560 88.800 57.760 89.400 ;
        RECT 59.360 88.800 59.560 89.400 ;
        RECT 64.560 88.800 64.760 89.400 ;
        RECT 66.360 88.800 66.560 89.400 ;
        RECT 68.260 88.800 68.460 89.400 ;
        RECT 70.060 88.800 70.260 89.400 ;
        RECT 75.260 88.800 75.460 89.400 ;
        RECT 77.060 88.800 77.260 89.400 ;
        RECT 78.960 88.800 79.160 89.400 ;
        RECT 80.760 88.800 80.960 89.400 ;
        RECT 85.960 88.800 86.160 89.400 ;
        RECT 87.760 88.800 87.960 89.400 ;
        RECT 89.660 88.800 89.860 89.400 ;
        RECT 91.460 88.800 91.660 89.400 ;
        RECT 96.660 88.800 96.860 89.400 ;
        RECT 98.460 88.800 98.660 89.400 ;
        RECT 100.360 88.800 100.560 89.400 ;
        RECT 102.160 88.800 102.360 89.400 ;
        RECT 107.360 88.800 107.560 89.400 ;
        RECT 109.160 88.800 109.360 89.400 ;
        RECT 111.060 88.800 111.260 89.400 ;
        RECT 112.860 88.800 113.060 89.400 ;
        RECT 118.060 88.800 118.260 89.400 ;
        RECT 119.860 88.800 120.060 89.400 ;
        RECT 121.760 88.800 121.960 89.400 ;
        RECT 123.560 88.800 123.760 89.400 ;
        RECT 44.660 87.600 125.060 88.800 ;
        RECT 45.260 87.000 45.460 87.600 ;
        RECT 47.060 87.000 47.260 87.600 ;
        RECT 48.960 87.000 49.160 87.600 ;
        RECT 50.760 87.000 50.960 87.600 ;
        RECT 53.860 87.000 54.060 87.600 ;
        RECT 55.660 87.000 55.860 87.600 ;
        RECT 57.560 87.000 57.760 87.600 ;
        RECT 59.360 87.000 59.560 87.600 ;
        RECT 64.560 87.000 64.760 87.600 ;
        RECT 66.360 87.000 66.560 87.600 ;
        RECT 68.260 87.000 68.460 87.600 ;
        RECT 70.060 87.000 70.260 87.600 ;
        RECT 75.260 87.000 75.460 87.600 ;
        RECT 77.060 87.000 77.260 87.600 ;
        RECT 78.960 87.000 79.160 87.600 ;
        RECT 80.760 87.000 80.960 87.600 ;
        RECT 85.960 87.000 86.160 87.600 ;
        RECT 87.760 87.000 87.960 87.600 ;
        RECT 89.660 87.000 89.860 87.600 ;
        RECT 91.460 87.000 91.660 87.600 ;
        RECT 96.660 87.000 96.860 87.600 ;
        RECT 98.460 87.000 98.660 87.600 ;
        RECT 100.360 87.000 100.560 87.600 ;
        RECT 102.160 87.000 102.360 87.600 ;
        RECT 107.360 87.000 107.560 87.600 ;
        RECT 109.160 87.000 109.360 87.600 ;
        RECT 111.060 87.000 111.260 87.600 ;
        RECT 112.860 87.000 113.060 87.600 ;
        RECT 118.060 87.000 118.260 87.600 ;
        RECT 119.860 87.000 120.060 87.600 ;
        RECT 121.760 87.000 121.960 87.600 ;
        RECT 123.560 87.000 123.760 87.600 ;
        RECT 45.160 85.700 45.560 87.000 ;
        RECT 46.960 85.700 47.360 87.000 ;
        RECT 48.860 85.700 49.260 87.000 ;
        RECT 50.660 85.700 51.060 87.000 ;
        RECT 53.760 85.700 54.160 87.000 ;
        RECT 55.560 85.700 55.960 87.000 ;
        RECT 57.460 85.700 57.860 87.000 ;
        RECT 59.260 85.700 59.660 87.000 ;
        RECT 64.460 85.700 64.860 87.000 ;
        RECT 66.260 85.700 66.660 87.000 ;
        RECT 68.160 85.700 68.560 87.000 ;
        RECT 69.960 85.700 70.360 87.000 ;
        RECT 75.160 85.700 75.560 87.000 ;
        RECT 76.960 85.700 77.360 87.000 ;
        RECT 78.860 85.700 79.260 87.000 ;
        RECT 80.660 85.700 81.060 87.000 ;
        RECT 85.860 85.700 86.260 87.000 ;
        RECT 87.660 85.700 88.060 87.000 ;
        RECT 89.560 85.700 89.960 87.000 ;
        RECT 91.360 85.700 91.760 87.000 ;
        RECT 96.560 85.700 96.960 87.000 ;
        RECT 98.360 85.700 98.760 87.000 ;
        RECT 100.260 85.700 100.660 87.000 ;
        RECT 102.060 85.700 102.460 87.000 ;
        RECT 107.260 85.700 107.660 87.000 ;
        RECT 109.060 85.700 109.460 87.000 ;
        RECT 110.960 85.700 111.360 87.000 ;
        RECT 112.760 85.700 113.160 87.000 ;
        RECT 117.960 85.700 118.360 87.000 ;
        RECT 119.760 85.700 120.160 87.000 ;
        RECT 121.660 85.700 122.060 87.000 ;
        RECT 123.460 85.700 123.860 87.000 ;
        RECT 48.650 48.250 49.050 54.350 ;
        RECT 55.400 50.250 60.200 50.650 ;
        RECT 56.900 49.550 58.700 50.250 ;
        RECT 63.260 49.850 63.660 54.650 ;
        RECT 65.060 49.850 65.460 54.650 ;
        RECT 66.660 49.850 67.060 54.650 ;
        RECT 55.600 49.050 60.200 49.550 ;
        RECT 63.360 49.150 63.560 49.850 ;
        RECT 65.160 49.150 65.360 49.850 ;
        RECT 66.760 49.150 66.960 49.850 ;
        RECT 70.050 49.150 70.450 52.350 ;
        RECT 71.850 49.150 72.250 52.350 ;
        RECT 74.450 52.050 74.850 52.850 ;
        RECT 62.450 49.050 73.250 49.150 ;
        RECT 55.550 48.950 73.250 49.050 ;
        RECT 74.550 48.950 74.850 52.050 ;
        RECT 75.350 48.950 75.750 59.850 ;
        RECT 76.950 48.950 77.350 59.850 ;
        RECT 77.850 52.050 78.250 52.850 ;
        RECT 77.850 48.950 78.150 52.050 ;
        RECT 84.450 48.950 84.850 55.650 ;
        RECT 87.350 48.950 87.750 55.050 ;
        RECT 55.550 48.250 87.950 48.950 ;
        RECT 47.250 48.050 87.950 48.250 ;
        RECT 47.250 47.950 67.360 48.050 ;
        RECT 69.350 48.000 72.750 48.050 ;
        RECT 47.250 47.000 56.850 47.950 ;
        RECT 57.350 47.500 57.800 47.950 ;
        RECT 47.250 46.000 56.800 47.000 ;
        RECT 48.550 45.550 48.800 46.000 ;
        RECT 50.050 45.550 50.300 46.000 ;
        RECT 51.550 45.550 51.800 46.000 ;
        RECT 53.050 45.550 53.300 46.000 ;
        RECT 54.550 45.550 54.800 46.000 ;
        RECT 48.450 43.650 48.850 45.550 ;
        RECT 49.950 43.650 50.350 45.550 ;
        RECT 51.450 43.650 51.850 45.550 ;
        RECT 52.950 43.650 53.350 45.550 ;
        RECT 54.450 43.650 54.850 45.550 ;
        RECT 57.350 37.350 57.750 47.500 ;
        RECT 59.850 37.350 60.250 47.950 ;
        RECT 63.360 47.150 63.560 47.950 ;
        RECT 65.160 47.150 65.360 47.950 ;
        RECT 66.760 47.150 66.960 47.950 ;
        RECT 69.350 47.550 69.550 48.000 ;
        RECT 70.850 47.550 71.050 48.000 ;
        RECT 72.550 47.600 72.750 48.000 ;
        RECT 63.260 42.350 63.660 47.150 ;
        RECT 65.060 42.350 65.460 47.150 ;
        RECT 66.660 42.350 67.060 47.150 ;
        RECT 69.250 45.750 69.650 47.550 ;
        RECT 70.750 45.750 71.150 47.550 ;
        RECT 72.450 45.800 72.850 47.600 ;
        RECT 76.650 45.350 77.650 48.050 ;
        RECT 76.260 44.950 80.560 45.350 ;
        RECT 76.660 44.450 76.860 44.950 ;
        RECT 78.260 44.450 78.460 44.950 ;
        RECT 76.560 43.650 76.960 44.450 ;
        RECT 78.160 43.650 78.560 44.450 ;
        RECT 84.150 42.750 84.550 48.050 ;
        RECT 40.800 19.800 41.200 22.300 ;
        RECT 50.900 19.800 51.300 24.300 ;
        RECT 51.800 19.800 52.200 25.600 ;
        RECT 61.900 19.800 62.300 27.300 ;
        RECT 63.260 24.950 63.660 29.750 ;
        RECT 65.060 24.950 65.460 29.750 ;
        RECT 66.660 24.950 67.060 29.750 ;
        RECT 63.360 24.150 63.560 24.950 ;
        RECT 65.160 24.150 65.360 24.950 ;
        RECT 66.760 24.150 66.960 24.950 ;
        RECT 62.850 23.250 67.360 24.150 ;
        RECT 71.000 23.550 71.400 26.350 ;
        RECT 72.500 23.550 72.900 26.350 ;
        RECT 74.500 23.950 74.900 25.750 ;
        RECT 71.050 23.250 71.350 23.550 ;
        RECT 72.550 23.250 72.850 23.550 ;
        RECT 74.550 23.250 74.850 23.950 ;
        RECT 62.850 22.550 75.100 23.250 ;
        RECT 62.850 22.450 67.450 22.550 ;
        RECT 62.850 19.800 64.300 22.450 ;
        RECT 40.200 18.450 64.300 19.800 ;
        RECT 40.200 18.250 64.350 18.450 ;
      LAYER met1 ;
        RECT 56.160 114.000 58.460 115.200 ;
        RECT 64.560 115.000 66.860 115.200 ;
        RECT 64.500 114.000 66.900 115.000 ;
        RECT 76.260 114.000 78.560 115.200 ;
        RECT 85.660 114.000 87.960 115.200 ;
        RECT 97.460 114.000 99.760 115.200 ;
        RECT 107.960 114.000 110.260 115.200 ;
        RECT 47.360 107.000 47.760 107.100 ;
        RECT 44.860 106.800 47.760 107.000 ;
        RECT 44.860 106.600 45.060 106.800 ;
        RECT 47.360 106.700 47.760 106.800 ;
        RECT 44.760 106.200 45.160 106.600 ;
        RECT 61.560 100.800 63.860 102.000 ;
        RECT 72.260 100.800 74.560 102.000 ;
        RECT 82.960 100.800 85.260 102.000 ;
        RECT 93.660 100.800 95.960 102.000 ;
        RECT 104.360 100.800 106.660 102.000 ;
        RECT 115.060 100.800 117.360 102.000 ;
        RECT 60.960 87.600 63.260 88.800 ;
        RECT 71.560 87.600 73.860 88.800 ;
        RECT 82.460 87.600 84.760 88.800 ;
        RECT 92.860 87.600 95.160 88.800 ;
        RECT 103.460 87.600 105.760 88.800 ;
        RECT 114.260 87.600 116.560 88.800 ;
        RECT 63.650 48.050 66.660 48.950 ;
        RECT 47.650 46.100 56.500 46.900 ;
        RECT 62.950 23.050 67.250 24.250 ;
        RECT 63.050 19.700 64.250 23.050 ;
        RECT 49.100 18.300 64.250 19.700 ;
      LAYER met2 ;
        RECT 56.160 114.000 58.460 115.200 ;
        RECT 64.560 115.000 66.860 115.200 ;
        RECT 64.500 114.000 66.900 115.000 ;
        RECT 76.260 114.000 78.560 115.200 ;
        RECT 85.660 114.000 87.960 115.200 ;
        RECT 97.460 114.000 99.760 115.200 ;
        RECT 107.960 114.000 110.260 115.200 ;
        RECT 61.560 100.800 63.860 102.000 ;
        RECT 72.260 100.800 74.560 102.000 ;
        RECT 82.960 100.800 85.260 102.000 ;
        RECT 93.660 100.800 95.960 102.000 ;
        RECT 104.360 100.800 106.660 102.000 ;
        RECT 115.060 100.800 117.360 102.000 ;
        RECT 60.960 87.600 63.260 88.800 ;
        RECT 71.560 87.600 73.860 88.800 ;
        RECT 82.460 87.600 84.760 88.800 ;
        RECT 92.860 87.600 95.160 88.800 ;
        RECT 103.460 87.600 105.760 88.800 ;
        RECT 114.260 87.600 116.560 88.800 ;
        RECT 63.650 48.050 66.650 48.950 ;
        RECT 47.750 46.150 56.400 46.850 ;
        RECT 62.950 23.050 67.250 24.250 ;
      LAYER met3 ;
        RECT 1.000 115.200 3.000 117.150 ;
        RECT 1.000 113.900 21.200 115.200 ;
        RECT 56.160 115.170 58.460 115.200 ;
        RECT 64.560 115.170 66.860 115.200 ;
        RECT 76.260 115.170 78.560 115.200 ;
        RECT 85.660 115.170 87.960 115.200 ;
        RECT 97.460 115.170 99.760 115.200 ;
        RECT 107.960 115.170 110.260 115.200 ;
        RECT 56.160 114.000 58.570 115.170 ;
        RECT 64.560 115.000 66.970 115.170 ;
        RECT 64.500 114.000 66.970 115.000 ;
        RECT 76.260 114.000 78.670 115.170 ;
        RECT 85.660 114.000 88.070 115.170 ;
        RECT 97.460 114.000 99.870 115.170 ;
        RECT 107.960 114.000 110.370 115.170 ;
        RECT 56.170 113.970 58.570 114.000 ;
        RECT 64.570 113.970 66.970 114.000 ;
        RECT 76.270 113.970 78.670 114.000 ;
        RECT 85.670 113.970 88.070 114.000 ;
        RECT 97.470 113.970 99.870 114.000 ;
        RECT 107.970 113.970 110.370 114.000 ;
        RECT 1.000 111.900 3.000 113.900 ;
        RECT 1.000 102.100 3.000 103.950 ;
        RECT 1.000 100.800 22.200 102.100 ;
        RECT 61.560 101.970 63.860 102.000 ;
        RECT 72.260 101.970 74.560 102.000 ;
        RECT 82.960 101.970 85.260 102.000 ;
        RECT 93.660 101.970 95.960 102.000 ;
        RECT 104.360 101.970 106.660 102.000 ;
        RECT 115.060 101.970 117.360 102.000 ;
        RECT 61.560 100.800 63.970 101.970 ;
        RECT 72.260 100.800 74.670 101.970 ;
        RECT 82.960 100.800 85.370 101.970 ;
        RECT 93.660 100.800 96.070 101.970 ;
        RECT 104.360 100.800 106.770 101.970 ;
        RECT 115.060 100.800 117.470 101.970 ;
        RECT 1.000 99.000 3.000 100.800 ;
        RECT 61.570 100.770 63.970 100.800 ;
        RECT 72.270 100.770 74.670 100.800 ;
        RECT 82.970 100.770 85.370 100.800 ;
        RECT 93.670 100.770 96.070 100.800 ;
        RECT 104.370 100.770 106.770 100.800 ;
        RECT 115.070 100.770 117.470 100.800 ;
        RECT 1.000 88.900 3.000 90.250 ;
        RECT 1.000 87.600 22.200 88.900 ;
        RECT 60.960 88.770 63.260 88.800 ;
        RECT 71.560 88.770 73.860 88.800 ;
        RECT 82.460 88.770 84.760 88.800 ;
        RECT 92.860 88.770 95.160 88.800 ;
        RECT 103.460 88.770 105.760 88.800 ;
        RECT 114.260 88.770 116.560 88.800 ;
        RECT 60.960 87.600 63.370 88.770 ;
        RECT 71.560 87.600 73.970 88.770 ;
        RECT 82.460 87.600 84.870 88.770 ;
        RECT 92.860 87.600 95.270 88.770 ;
        RECT 103.460 87.600 105.870 88.770 ;
        RECT 114.260 87.600 116.670 88.770 ;
        RECT 1.000 86.200 3.000 87.600 ;
        RECT 60.970 87.570 63.370 87.600 ;
        RECT 71.570 87.570 73.970 87.600 ;
        RECT 82.470 87.570 84.870 87.600 ;
        RECT 92.870 87.570 95.270 87.600 ;
        RECT 103.470 87.570 105.870 87.600 ;
        RECT 114.270 87.570 116.670 87.600 ;
        RECT 1.000 48.950 3.000 50.550 ;
        RECT 1.000 48.000 31.000 48.950 ;
        RECT 63.650 48.050 66.650 48.950 ;
        RECT 1.000 46.250 3.000 48.000 ;
        RECT 47.750 46.150 56.400 46.850 ;
        RECT 1.000 24.200 3.000 25.300 ;
        RECT 1.000 22.800 32.100 24.200 ;
        RECT 62.950 23.050 67.250 24.250 ;
        RECT 1.000 21.500 3.000 22.800 ;
      LAYER met4 ;
        RECT 1.000 5.000 3.000 220.760 ;
        RECT 14.600 115.170 67.000 115.200 ;
        RECT 14.600 114.000 110.370 115.170 ;
        RECT 38.370 113.970 110.370 114.000 ;
        RECT 13.850 101.970 63.900 102.000 ;
        RECT 13.850 100.800 117.470 101.970 ;
        RECT 40.270 100.770 117.470 100.800 ;
        RECT 12.650 88.800 17.600 88.900 ;
        RECT 12.650 88.770 63.300 88.800 ;
        RECT 12.650 87.570 116.670 88.770 ;
        RECT 12.650 87.500 63.300 87.570 ;
        RECT 25.500 48.050 67.350 48.950 ;
        RECT 47.650 46.100 56.500 48.050 ;
        RECT 62.850 24.150 67.250 24.650 ;
        RECT 25.950 22.850 67.250 24.150 ;
        RECT 62.850 22.550 67.250 22.850 ;
    END
  END VDPWR
  PIN VGND
    DIRECTION INOUT ;
    USE GROUND ;
    PORT
      LAYER li1 ;
        RECT 59.560 110.700 59.960 111.200 ;
        RECT 62.060 110.700 62.460 111.200 ;
        RECT 70.260 110.700 70.660 111.200 ;
        RECT 72.760 110.700 73.160 111.200 ;
        RECT 80.960 110.700 81.360 111.200 ;
        RECT 83.460 110.700 83.860 111.200 ;
        RECT 91.660 110.700 92.060 111.200 ;
        RECT 94.160 110.700 94.560 111.200 ;
        RECT 102.360 110.700 102.760 111.200 ;
        RECT 104.860 110.700 105.260 111.200 ;
        RECT 113.060 110.700 113.460 111.200 ;
        RECT 115.560 110.700 115.960 111.200 ;
        RECT 59.660 110.300 59.860 110.700 ;
        RECT 62.160 110.300 62.360 110.700 ;
        RECT 70.360 110.300 70.560 110.700 ;
        RECT 72.860 110.300 73.060 110.700 ;
        RECT 81.060 110.300 81.260 110.700 ;
        RECT 83.560 110.300 83.760 110.700 ;
        RECT 91.760 110.300 91.960 110.700 ;
        RECT 94.260 110.300 94.460 110.700 ;
        RECT 102.460 110.300 102.660 110.700 ;
        RECT 104.960 110.300 105.160 110.700 ;
        RECT 113.160 110.300 113.360 110.700 ;
        RECT 115.660 110.300 115.860 110.700 ;
        RECT 44.160 109.200 125.660 110.300 ;
        RECT 44.560 108.200 44.760 109.200 ;
        RECT 46.460 108.200 46.660 109.200 ;
        RECT 50.560 108.200 50.760 109.200 ;
        RECT 52.260 108.200 52.460 109.200 ;
        RECT 53.160 108.200 53.360 109.200 ;
        RECT 55.060 108.200 55.260 109.200 ;
        RECT 59.160 108.200 59.360 109.200 ;
        RECT 60.860 108.200 61.060 109.200 ;
        RECT 63.860 108.200 64.060 109.200 ;
        RECT 65.760 108.200 65.960 109.200 ;
        RECT 69.860 108.200 70.060 109.200 ;
        RECT 71.560 108.200 71.760 109.200 ;
        RECT 74.560 108.200 74.760 109.200 ;
        RECT 76.460 108.200 76.660 109.200 ;
        RECT 80.560 108.200 80.760 109.200 ;
        RECT 82.260 108.200 82.460 109.200 ;
        RECT 85.260 108.200 85.460 109.200 ;
        RECT 87.160 108.200 87.360 109.200 ;
        RECT 91.260 108.200 91.460 109.200 ;
        RECT 92.960 108.200 93.160 109.200 ;
        RECT 95.960 108.200 96.160 109.200 ;
        RECT 97.860 108.200 98.060 109.200 ;
        RECT 101.960 108.200 102.160 109.200 ;
        RECT 103.660 108.200 103.860 109.200 ;
        RECT 106.660 108.200 106.860 109.200 ;
        RECT 108.560 108.200 108.760 109.200 ;
        RECT 112.660 108.200 112.860 109.200 ;
        RECT 114.360 108.200 114.560 109.200 ;
        RECT 117.360 108.200 117.560 109.200 ;
        RECT 119.260 108.200 119.460 109.200 ;
        RECT 123.360 108.200 123.560 109.200 ;
        RECT 125.060 108.200 125.260 109.200 ;
        RECT 44.460 107.400 44.860 108.200 ;
        RECT 46.360 107.400 46.760 108.200 ;
        RECT 50.460 107.400 50.860 108.200 ;
        RECT 52.160 107.400 52.560 108.200 ;
        RECT 53.060 107.400 53.460 108.200 ;
        RECT 54.960 107.400 55.360 108.200 ;
        RECT 59.060 107.400 59.460 108.200 ;
        RECT 60.760 107.400 61.160 108.200 ;
        RECT 63.760 107.400 64.160 108.200 ;
        RECT 65.660 107.400 66.060 108.200 ;
        RECT 69.760 107.400 70.160 108.200 ;
        RECT 71.460 107.400 71.860 108.200 ;
        RECT 74.460 107.400 74.860 108.200 ;
        RECT 76.360 107.400 76.760 108.200 ;
        RECT 80.460 107.400 80.860 108.200 ;
        RECT 82.160 107.400 82.560 108.200 ;
        RECT 85.160 107.400 85.560 108.200 ;
        RECT 87.060 107.400 87.460 108.200 ;
        RECT 91.160 107.400 91.560 108.200 ;
        RECT 92.860 107.400 93.260 108.200 ;
        RECT 95.860 107.400 96.260 108.200 ;
        RECT 97.760 107.400 98.160 108.200 ;
        RECT 101.860 107.400 102.260 108.200 ;
        RECT 103.560 107.400 103.960 108.200 ;
        RECT 106.560 107.400 106.960 108.200 ;
        RECT 108.460 107.400 108.860 108.200 ;
        RECT 112.560 107.400 112.960 108.200 ;
        RECT 114.260 107.400 114.660 108.200 ;
        RECT 117.260 107.400 117.660 108.200 ;
        RECT 119.160 107.400 119.560 108.200 ;
        RECT 123.260 107.400 123.660 108.200 ;
        RECT 124.960 107.400 125.360 108.200 ;
        RECT 45.160 96.100 45.560 96.900 ;
        RECT 48.860 96.100 49.260 96.900 ;
        RECT 53.760 96.100 54.160 96.900 ;
        RECT 57.460 96.100 57.860 96.900 ;
        RECT 64.460 96.100 64.860 96.900 ;
        RECT 68.160 96.100 68.560 96.900 ;
        RECT 75.160 96.100 75.560 96.900 ;
        RECT 78.860 96.100 79.260 96.900 ;
        RECT 85.860 96.100 86.260 96.900 ;
        RECT 89.560 96.100 89.960 96.900 ;
        RECT 96.560 96.100 96.960 96.900 ;
        RECT 100.260 96.100 100.660 96.900 ;
        RECT 107.260 96.100 107.660 96.900 ;
        RECT 110.960 96.100 111.360 96.900 ;
        RECT 117.960 96.100 118.360 96.900 ;
        RECT 121.660 96.100 122.060 96.900 ;
        RECT 45.260 95.500 45.460 96.100 ;
        RECT 48.960 95.500 49.160 96.100 ;
        RECT 53.860 95.500 54.060 96.100 ;
        RECT 57.560 95.500 57.760 96.100 ;
        RECT 64.560 95.500 64.760 96.100 ;
        RECT 68.260 95.500 68.460 96.100 ;
        RECT 75.260 95.500 75.460 96.100 ;
        RECT 78.960 95.500 79.160 96.100 ;
        RECT 85.960 95.500 86.160 96.100 ;
        RECT 89.660 95.500 89.860 96.100 ;
        RECT 96.660 95.500 96.860 96.100 ;
        RECT 100.360 95.500 100.560 96.100 ;
        RECT 107.360 95.500 107.560 96.100 ;
        RECT 111.060 95.500 111.260 96.100 ;
        RECT 118.060 95.500 118.260 96.100 ;
        RECT 121.760 95.500 121.960 96.100 ;
        RECT 44.160 94.100 125.660 95.500 ;
        RECT 45.260 93.500 45.460 94.100 ;
        RECT 48.960 93.500 49.160 94.100 ;
        RECT 53.860 93.500 54.060 94.100 ;
        RECT 57.560 93.500 57.760 94.100 ;
        RECT 64.560 93.500 64.760 94.100 ;
        RECT 68.260 93.500 68.460 94.100 ;
        RECT 75.260 93.500 75.460 94.100 ;
        RECT 78.960 93.500 79.160 94.100 ;
        RECT 85.960 93.500 86.160 94.100 ;
        RECT 89.660 93.500 89.860 94.100 ;
        RECT 96.660 93.500 96.860 94.100 ;
        RECT 100.360 93.500 100.560 94.100 ;
        RECT 107.360 93.500 107.560 94.100 ;
        RECT 111.060 93.500 111.260 94.100 ;
        RECT 118.060 93.500 118.260 94.100 ;
        RECT 121.760 93.500 121.960 94.100 ;
        RECT 45.160 92.700 45.560 93.500 ;
        RECT 48.860 92.700 49.260 93.500 ;
        RECT 53.760 92.700 54.160 93.500 ;
        RECT 57.460 92.700 57.860 93.500 ;
        RECT 64.460 92.700 64.860 93.500 ;
        RECT 68.160 92.700 68.560 93.500 ;
        RECT 75.160 92.700 75.560 93.500 ;
        RECT 78.860 92.700 79.260 93.500 ;
        RECT 85.860 92.700 86.260 93.500 ;
        RECT 89.560 92.700 89.960 93.500 ;
        RECT 96.560 92.700 96.960 93.500 ;
        RECT 100.260 92.700 100.660 93.500 ;
        RECT 107.260 92.700 107.660 93.500 ;
        RECT 110.960 92.700 111.360 93.500 ;
        RECT 117.960 92.700 118.360 93.500 ;
        RECT 121.660 92.700 122.060 93.500 ;
        RECT 45.160 82.900 45.560 83.700 ;
        RECT 48.860 82.900 49.260 83.700 ;
        RECT 53.760 82.900 54.160 83.700 ;
        RECT 57.460 82.900 57.860 83.700 ;
        RECT 64.460 82.900 64.860 83.700 ;
        RECT 68.160 82.900 68.560 83.700 ;
        RECT 75.160 82.900 75.560 83.700 ;
        RECT 78.860 82.900 79.260 83.700 ;
        RECT 85.860 82.900 86.260 83.700 ;
        RECT 89.560 82.900 89.960 83.700 ;
        RECT 96.560 82.900 96.960 83.700 ;
        RECT 100.260 82.900 100.660 83.700 ;
        RECT 107.260 82.900 107.660 83.700 ;
        RECT 110.960 82.900 111.360 83.700 ;
        RECT 117.960 82.900 118.360 83.700 ;
        RECT 121.660 82.900 122.060 83.700 ;
        RECT 45.260 82.300 45.460 82.900 ;
        RECT 48.960 82.300 49.160 82.900 ;
        RECT 53.860 82.300 54.060 82.900 ;
        RECT 57.560 82.300 57.760 82.900 ;
        RECT 64.560 82.300 64.760 82.900 ;
        RECT 68.260 82.300 68.460 82.900 ;
        RECT 75.260 82.300 75.460 82.900 ;
        RECT 78.960 82.300 79.160 82.900 ;
        RECT 85.960 82.300 86.160 82.900 ;
        RECT 89.660 82.300 89.860 82.900 ;
        RECT 96.660 82.300 96.860 82.900 ;
        RECT 100.360 82.300 100.560 82.900 ;
        RECT 107.360 82.300 107.560 82.900 ;
        RECT 111.060 82.300 111.260 82.900 ;
        RECT 118.060 82.300 118.260 82.900 ;
        RECT 121.760 82.300 121.960 82.900 ;
        RECT 44.660 81.100 125.060 82.300 ;
        RECT 73.350 69.750 87.550 70.750 ;
        RECT 51.450 67.450 87.550 69.750 ;
        RECT 51.450 66.350 74.550 67.450 ;
        RECT 51.500 65.950 74.550 66.350 ;
        RECT 48.650 65.450 74.550 65.950 ;
        RECT 78.750 65.850 79.050 67.450 ;
        RECT 48.650 56.350 49.050 65.450 ;
        RECT 51.500 65.250 74.550 65.450 ;
        RECT 51.500 65.000 64.500 65.250 ;
        RECT 51.500 64.950 59.500 65.000 ;
        RECT 51.500 64.650 52.300 64.950 ;
        RECT 53.300 64.650 54.100 64.950 ;
        RECT 55.100 64.650 55.900 64.950 ;
        RECT 56.900 64.650 57.700 64.950 ;
        RECT 58.700 64.650 59.500 64.950 ;
        RECT 62.850 61.450 64.500 65.000 ;
        RECT 62.850 60.450 67.550 61.450 ;
        RECT 74.250 60.550 74.550 65.250 ;
        RECT 78.650 61.050 79.050 65.850 ;
        RECT 80.450 63.150 80.850 67.450 ;
        RECT 81.350 63.050 81.750 67.450 ;
        RECT 84.450 64.550 84.850 67.450 ;
        RECT 86.550 66.450 86.850 67.450 ;
        RECT 86.550 61.550 86.950 66.450 ;
        RECT 63.360 59.750 63.560 60.450 ;
        RECT 65.160 59.750 65.360 60.450 ;
        RECT 74.150 59.750 74.550 60.550 ;
        RECT 63.260 56.050 63.660 59.750 ;
        RECT 65.060 56.050 65.460 59.750 ;
        RECT 76.460 41.250 77.060 41.750 ;
        RECT 78.960 41.250 79.560 41.750 ;
        RECT 49.950 37.850 50.350 39.750 ;
        RECT 52.950 37.850 53.350 39.750 ;
        RECT 63.260 37.250 63.660 40.950 ;
        RECT 65.060 37.250 65.460 40.950 ;
        RECT 76.660 40.850 76.860 41.250 ;
        RECT 79.060 40.850 79.260 41.250 ;
        RECT 76.150 40.450 80.560 40.850 ;
        RECT 47.800 34.050 48.200 36.950 ;
        RECT 47.800 32.050 48.000 34.050 ;
        RECT 50.000 32.550 50.400 36.950 ;
        RECT 50.800 34.050 51.200 36.950 ;
        RECT 43.200 32.000 48.050 32.050 ;
        RECT 50.100 32.000 50.300 32.550 ;
        RECT 50.800 32.000 51.000 34.050 ;
        RECT 53.000 32.550 53.400 36.950 ;
        RECT 53.800 34.050 54.200 36.950 ;
        RECT 53.100 32.000 53.300 32.550 ;
        RECT 53.800 32.000 54.000 34.050 ;
        RECT 56.000 32.550 56.400 36.950 ;
        RECT 63.360 36.650 63.560 37.250 ;
        RECT 65.160 36.650 65.360 37.250 ;
        RECT 62.960 36.450 67.550 36.650 ;
        RECT 69.150 36.450 69.550 39.550 ;
        RECT 76.150 38.750 80.550 40.450 ;
        RECT 79.250 37.850 79.650 38.750 ;
        RECT 84.150 37.850 84.550 40.750 ;
        RECT 79.250 37.350 84.550 37.850 ;
        RECT 62.960 35.750 69.550 36.450 ;
        RECT 56.100 32.000 56.300 32.550 ;
        RECT 57.350 32.050 57.750 35.750 ;
        RECT 62.960 35.650 67.550 35.750 ;
        RECT 63.250 34.850 63.560 35.650 ;
        RECT 65.160 34.850 65.360 35.650 ;
        RECT 63.250 34.650 63.660 34.850 ;
        RECT 56.750 32.000 57.750 32.050 ;
        RECT 43.200 31.050 57.750 32.000 ;
        RECT 63.260 31.150 63.660 34.650 ;
        RECT 65.060 31.150 65.460 34.850 ;
        RECT 43.200 25.700 43.600 31.050 ;
        RECT 47.250 31.000 57.750 31.050 ;
        RECT 57.350 28.550 57.750 31.000 ;
      LAYER met1 ;
        RECT 61.260 109.200 63.660 110.300 ;
        RECT 71.960 109.200 74.360 110.300 ;
        RECT 82.660 109.200 85.060 110.300 ;
        RECT 93.360 109.200 95.760 110.300 ;
        RECT 104.060 109.200 106.460 110.300 ;
        RECT 114.760 109.200 117.160 110.300 ;
        RECT 61.160 94.300 63.560 95.400 ;
        RECT 71.860 94.300 74.260 95.400 ;
        RECT 82.560 94.300 84.960 95.400 ;
        RECT 93.260 94.300 95.660 95.400 ;
        RECT 103.960 94.300 106.360 95.400 ;
        RECT 114.660 94.300 117.060 95.400 ;
        RECT 61.200 94.200 63.500 94.300 ;
        RECT 53.260 81.100 55.660 82.200 ;
        RECT 62.060 81.100 64.460 82.200 ;
        RECT 72.660 81.100 75.060 82.200 ;
        RECT 83.360 81.100 85.760 82.200 ;
        RECT 94.560 81.100 96.960 82.200 ;
        RECT 105.060 81.100 107.460 82.200 ;
        RECT 115.860 81.100 118.260 82.200 ;
        RECT 53.140 67.850 70.640 68.800 ;
        RECT 54.650 66.750 70.650 67.850 ;
        RECT 63.950 60.550 66.360 61.350 ;
        RECT 50.000 38.150 50.300 39.550 ;
        RECT 53.000 38.150 53.300 39.550 ;
        RECT 76.150 38.750 80.550 40.850 ;
        RECT 50.050 32.000 50.250 38.150 ;
        RECT 53.050 32.000 53.250 38.150 ;
        RECT 63.450 35.750 66.860 36.550 ;
        RECT 47.250 31.000 56.800 32.000 ;
      LAYER met2 ;
        RECT 61.260 109.200 63.660 110.300 ;
        RECT 71.960 109.200 74.360 110.300 ;
        RECT 82.660 109.200 85.060 110.300 ;
        RECT 93.360 109.200 95.760 110.300 ;
        RECT 104.060 109.200 106.460 110.300 ;
        RECT 114.760 109.200 117.160 110.300 ;
        RECT 61.160 94.300 63.560 95.400 ;
        RECT 71.860 94.300 74.260 95.400 ;
        RECT 82.560 94.300 84.960 95.400 ;
        RECT 93.260 94.300 95.660 95.400 ;
        RECT 103.960 94.300 106.360 95.400 ;
        RECT 114.660 94.300 117.060 95.400 ;
        RECT 61.200 94.200 63.500 94.300 ;
        RECT 53.260 81.100 55.660 82.200 ;
        RECT 62.060 81.100 64.460 82.200 ;
        RECT 72.660 81.100 75.060 82.200 ;
        RECT 83.360 81.100 85.760 82.200 ;
        RECT 94.560 81.100 96.960 82.200 ;
        RECT 105.060 81.100 107.460 82.200 ;
        RECT 115.860 81.100 118.260 82.200 ;
        RECT 53.140 67.850 70.640 68.800 ;
        RECT 54.650 66.750 70.650 67.850 ;
        RECT 63.950 60.550 66.350 61.350 ;
        RECT 76.150 38.750 80.550 40.850 ;
        RECT 63.450 35.750 66.850 36.550 ;
        RECT 49.950 30.750 54.350 32.250 ;
      LAYER met3 ;
        RECT 61.260 110.300 63.560 110.400 ;
        RECT 61.260 110.270 63.660 110.300 ;
        RECT 71.960 110.270 74.360 110.300 ;
        RECT 82.660 110.270 85.060 110.300 ;
        RECT 93.360 110.270 95.760 110.300 ;
        RECT 104.060 110.270 106.460 110.300 ;
        RECT 114.760 110.270 117.160 110.300 ;
        RECT 61.260 109.200 63.670 110.270 ;
        RECT 71.960 109.200 74.370 110.270 ;
        RECT 82.660 109.200 85.070 110.270 ;
        RECT 93.360 109.200 95.770 110.270 ;
        RECT 104.060 109.200 106.470 110.270 ;
        RECT 114.760 109.200 117.170 110.270 ;
        RECT 61.270 109.070 63.670 109.200 ;
        RECT 71.970 109.070 74.370 109.200 ;
        RECT 82.670 109.070 85.070 109.200 ;
        RECT 93.370 109.070 95.770 109.200 ;
        RECT 104.070 109.070 106.470 109.200 ;
        RECT 114.770 109.070 117.170 109.200 ;
        RECT 61.160 95.400 63.460 95.500 ;
        RECT 114.660 95.400 116.960 95.500 ;
        RECT 61.160 95.370 63.560 95.400 ;
        RECT 71.860 95.370 74.260 95.400 ;
        RECT 82.560 95.370 84.960 95.400 ;
        RECT 93.260 95.370 95.660 95.400 ;
        RECT 103.960 95.370 106.360 95.400 ;
        RECT 114.660 95.370 117.060 95.400 ;
        RECT 61.160 94.300 63.570 95.370 ;
        RECT 71.860 94.300 74.270 95.370 ;
        RECT 82.560 94.300 84.970 95.370 ;
        RECT 93.260 94.300 95.670 95.370 ;
        RECT 103.960 94.300 106.370 95.370 ;
        RECT 114.660 94.300 117.070 95.370 ;
        RECT 61.170 94.170 63.570 94.300 ;
        RECT 71.870 94.170 74.270 94.300 ;
        RECT 82.570 94.170 84.970 94.300 ;
        RECT 93.270 94.170 95.670 94.300 ;
        RECT 103.970 94.170 106.370 94.300 ;
        RECT 114.670 94.170 117.070 94.300 ;
        RECT 62.060 82.270 64.360 82.300 ;
        RECT 115.860 82.270 118.160 82.300 ;
        RECT 53.270 82.200 55.670 82.270 ;
        RECT 53.260 81.100 55.670 82.200 ;
        RECT 62.060 81.100 64.470 82.270 ;
        RECT 72.670 82.200 75.070 82.270 ;
        RECT 83.370 82.200 85.770 82.270 ;
        RECT 94.570 82.200 96.970 82.270 ;
        RECT 105.070 82.200 107.470 82.270 ;
        RECT 72.660 81.100 75.070 82.200 ;
        RECT 83.360 81.100 85.770 82.200 ;
        RECT 94.560 81.100 96.970 82.200 ;
        RECT 105.060 81.100 107.470 82.200 ;
        RECT 115.860 81.100 118.270 82.270 ;
        RECT 53.270 81.070 55.670 81.100 ;
        RECT 62.070 81.070 64.470 81.100 ;
        RECT 72.670 81.070 75.070 81.100 ;
        RECT 83.370 81.070 85.770 81.100 ;
        RECT 94.570 81.070 96.970 81.100 ;
        RECT 105.070 81.070 107.470 81.100 ;
        RECT 115.870 81.070 118.270 81.100 ;
        RECT 53.140 67.850 70.640 68.800 ;
        RECT 54.650 66.750 70.650 67.850 ;
        RECT 63.950 60.550 66.350 61.350 ;
        RECT 76.150 38.750 80.550 40.850 ;
        RECT 63.450 35.750 66.850 36.550 ;
        RECT 49.950 30.750 54.350 32.250 ;
      LAYER met4 ;
        RECT 4.000 110.300 6.000 220.760 ;
        RECT 4.000 110.270 63.700 110.300 ;
        RECT 4.000 109.070 117.170 110.270 ;
        RECT 4.000 109.000 63.700 109.070 ;
        RECT 4.000 95.400 6.000 109.000 ;
        RECT 4.000 95.370 63.600 95.400 ;
        RECT 4.000 94.170 117.070 95.370 ;
        RECT 4.000 94.100 63.600 94.170 ;
        RECT 4.000 82.300 6.000 94.100 ;
        RECT 4.000 82.270 55.700 82.300 ;
        RECT 4.000 81.070 118.270 82.270 ;
        RECT 4.000 81.000 55.700 81.070 ;
        RECT 4.000 69.250 6.000 81.000 ;
        RECT 4.000 66.750 70.700 69.250 ;
        RECT 4.000 66.700 55.660 66.750 ;
        RECT 4.000 61.350 6.000 66.700 ;
        RECT 4.000 60.300 67.350 61.350 ;
        RECT 4.000 32.400 6.000 60.300 ;
        RECT 76.150 38.750 80.550 40.850 ;
        RECT 50.350 36.650 67.600 37.150 ;
        RECT 77.050 36.650 79.250 38.750 ;
        RECT 50.350 35.450 79.250 36.650 ;
        RECT 50.350 35.050 67.250 35.450 ;
        RECT 50.450 32.400 53.750 35.050 ;
        RECT 4.000 32.250 54.300 32.400 ;
        RECT 4.000 30.750 54.350 32.250 ;
        RECT 4.000 30.700 54.300 30.750 ;
        RECT 4.000 5.000 6.000 30.700 ;
    END
  END VGND
  OBS
      LAYER li1 ;
        RECT 60.360 112.600 60.760 113.600 ;
        RECT 61.960 112.600 62.360 113.600 ;
        RECT 71.060 112.600 71.460 113.600 ;
        RECT 72.660 112.600 73.060 113.600 ;
        RECT 81.760 112.600 82.160 113.600 ;
        RECT 83.360 112.600 83.760 113.600 ;
        RECT 92.460 112.600 92.860 113.600 ;
        RECT 94.060 112.600 94.460 113.600 ;
        RECT 103.160 112.600 103.560 113.600 ;
        RECT 104.760 112.600 105.160 113.600 ;
        RECT 113.860 112.600 114.260 113.600 ;
        RECT 115.460 112.600 115.860 113.600 ;
        RECT 60.460 112.200 60.660 112.600 ;
        RECT 62.060 112.400 62.260 112.600 ;
        RECT 61.360 112.200 61.760 112.300 ;
        RECT 62.060 112.200 63.460 112.400 ;
        RECT 60.460 112.000 61.760 112.200 ;
        RECT 61.260 111.900 61.760 112.000 ;
        RECT 62.960 111.900 63.460 112.200 ;
        RECT 70.460 111.900 70.860 112.300 ;
        RECT 71.160 112.200 71.360 112.600 ;
        RECT 72.760 112.400 72.960 112.600 ;
        RECT 72.060 112.200 72.460 112.300 ;
        RECT 72.760 112.200 74.160 112.400 ;
        RECT 71.160 112.000 72.460 112.200 ;
        RECT 71.960 111.900 72.460 112.000 ;
        RECT 73.660 111.900 74.160 112.200 ;
        RECT 81.160 111.900 81.560 112.300 ;
        RECT 81.860 112.200 82.060 112.600 ;
        RECT 83.460 112.400 83.660 112.600 ;
        RECT 82.760 112.200 83.160 112.300 ;
        RECT 83.460 112.200 84.860 112.400 ;
        RECT 81.860 112.000 83.160 112.200 ;
        RECT 82.660 111.900 83.160 112.000 ;
        RECT 84.360 111.900 84.860 112.200 ;
        RECT 91.860 111.900 92.260 112.300 ;
        RECT 92.560 112.200 92.760 112.600 ;
        RECT 94.160 112.400 94.360 112.600 ;
        RECT 93.460 112.200 93.860 112.300 ;
        RECT 94.160 112.200 95.560 112.400 ;
        RECT 92.560 112.000 93.860 112.200 ;
        RECT 93.360 111.900 93.860 112.000 ;
        RECT 95.060 111.900 95.560 112.200 ;
        RECT 102.560 111.900 102.960 112.300 ;
        RECT 103.260 112.200 103.460 112.600 ;
        RECT 104.860 112.400 105.060 112.600 ;
        RECT 104.160 112.200 104.560 112.300 ;
        RECT 104.860 112.200 106.260 112.400 ;
        RECT 103.260 112.000 104.560 112.200 ;
        RECT 104.060 111.900 104.560 112.000 ;
        RECT 105.760 111.900 106.260 112.200 ;
        RECT 113.260 111.900 113.660 112.300 ;
        RECT 113.960 112.200 114.160 112.600 ;
        RECT 115.560 112.400 115.760 112.600 ;
        RECT 114.860 112.200 115.260 112.300 ;
        RECT 115.560 112.200 116.960 112.400 ;
        RECT 113.960 112.000 115.260 112.200 ;
        RECT 114.760 111.900 115.260 112.000 ;
        RECT 116.460 111.900 116.960 112.200 ;
        RECT 61.260 111.200 61.460 111.900 ;
        RECT 62.960 111.200 63.160 111.900 ;
        RECT 71.960 111.200 72.160 111.900 ;
        RECT 73.660 111.200 73.860 111.900 ;
        RECT 82.660 111.200 82.860 111.900 ;
        RECT 84.360 111.200 84.560 111.900 ;
        RECT 93.360 111.200 93.560 111.900 ;
        RECT 95.060 111.200 95.260 111.900 ;
        RECT 104.060 111.200 104.260 111.900 ;
        RECT 105.760 111.200 105.960 111.900 ;
        RECT 114.760 111.200 114.960 111.900 ;
        RECT 116.460 111.200 116.660 111.900 ;
        RECT 60.360 110.700 60.760 111.200 ;
        RECT 61.160 110.700 61.560 111.200 ;
        RECT 62.860 110.700 63.260 111.200 ;
        RECT 71.060 110.700 71.460 111.200 ;
        RECT 71.860 110.700 72.260 111.200 ;
        RECT 73.560 110.700 73.960 111.200 ;
        RECT 81.760 110.700 82.160 111.200 ;
        RECT 82.560 110.700 82.960 111.200 ;
        RECT 84.260 110.700 84.660 111.200 ;
        RECT 92.460 110.700 92.860 111.200 ;
        RECT 93.260 110.700 93.660 111.200 ;
        RECT 94.960 110.700 95.360 111.200 ;
        RECT 103.160 110.700 103.560 111.200 ;
        RECT 103.960 110.700 104.360 111.200 ;
        RECT 105.660 110.700 106.060 111.200 ;
        RECT 113.860 110.700 114.260 111.200 ;
        RECT 114.660 110.700 115.060 111.200 ;
        RECT 116.360 110.700 116.760 111.200 ;
        RECT 45.260 107.400 45.660 108.200 ;
        RECT 47.160 107.400 47.560 108.200 ;
        RECT 47.960 107.400 48.360 108.200 ;
        RECT 48.860 107.400 49.260 108.200 ;
        RECT 49.660 107.400 50.060 108.200 ;
        RECT 51.360 107.400 51.760 108.200 ;
        RECT 53.860 107.400 54.260 108.200 ;
        RECT 55.760 107.400 56.160 108.200 ;
        RECT 56.560 107.400 56.960 108.200 ;
        RECT 57.460 107.400 57.860 108.200 ;
        RECT 58.260 107.400 58.660 108.200 ;
        RECT 59.960 107.400 60.360 108.200 ;
        RECT 64.560 107.400 64.960 108.200 ;
        RECT 66.460 107.400 66.860 108.200 ;
        RECT 67.260 107.400 67.660 108.200 ;
        RECT 68.160 107.400 68.560 108.200 ;
        RECT 68.960 107.400 69.360 108.200 ;
        RECT 70.660 107.400 71.060 108.200 ;
        RECT 75.260 107.400 75.660 108.200 ;
        RECT 77.160 107.400 77.560 108.200 ;
        RECT 77.960 107.400 78.360 108.200 ;
        RECT 78.860 107.400 79.260 108.200 ;
        RECT 79.660 107.400 80.060 108.200 ;
        RECT 81.360 107.400 81.760 108.200 ;
        RECT 85.960 107.400 86.360 108.200 ;
        RECT 87.860 107.400 88.260 108.200 ;
        RECT 88.660 107.400 89.060 108.200 ;
        RECT 89.560 107.400 89.960 108.200 ;
        RECT 90.360 107.400 90.760 108.200 ;
        RECT 92.060 107.400 92.460 108.200 ;
        RECT 96.660 107.400 97.060 108.200 ;
        RECT 98.560 107.400 98.960 108.200 ;
        RECT 99.360 107.400 99.760 108.200 ;
        RECT 100.260 107.400 100.660 108.200 ;
        RECT 101.060 107.400 101.460 108.200 ;
        RECT 102.760 107.400 103.160 108.200 ;
        RECT 107.360 107.400 107.760 108.200 ;
        RECT 109.260 107.400 109.660 108.200 ;
        RECT 110.060 107.400 110.460 108.200 ;
        RECT 110.960 107.400 111.360 108.200 ;
        RECT 111.760 107.400 112.160 108.200 ;
        RECT 113.460 107.400 113.860 108.200 ;
        RECT 118.060 107.400 118.460 108.200 ;
        RECT 119.960 107.400 120.360 108.200 ;
        RECT 120.760 107.400 121.160 108.200 ;
        RECT 121.660 107.400 122.060 108.200 ;
        RECT 122.460 107.400 122.860 108.200 ;
        RECT 124.160 107.400 124.560 108.200 ;
        RECT 45.360 106.200 45.560 107.400 ;
        RECT 48.060 106.300 48.260 107.400 ;
        RECT 48.960 106.300 49.160 107.400 ;
        RECT 50.260 106.800 50.660 106.900 ;
        RECT 51.460 106.800 51.660 107.400 ;
        RECT 50.260 106.600 51.660 106.800 ;
        RECT 50.260 106.500 50.660 106.600 ;
        RECT 45.360 105.800 46.060 106.200 ;
        RECT 45.360 105.200 45.560 105.800 ;
        RECT 48.060 105.700 49.160 106.300 ;
        RECT 48.060 105.200 48.260 105.700 ;
        RECT 48.960 105.200 49.160 105.700 ;
        RECT 51.460 105.200 51.660 106.600 ;
        RECT 53.960 106.200 54.160 107.400 ;
        RECT 56.660 106.300 56.860 107.400 ;
        RECT 57.560 106.300 57.760 107.400 ;
        RECT 58.860 106.800 59.260 106.900 ;
        RECT 60.060 106.800 60.260 107.400 ;
        RECT 58.860 106.600 60.260 106.800 ;
        RECT 58.860 106.500 59.260 106.600 ;
        RECT 53.960 105.800 54.660 106.200 ;
        RECT 53.960 105.200 54.160 105.800 ;
        RECT 56.660 105.700 57.760 106.300 ;
        RECT 56.660 105.200 56.860 105.700 ;
        RECT 57.560 105.200 57.760 105.700 ;
        RECT 60.060 105.200 60.260 106.600 ;
        RECT 64.060 106.200 64.460 106.600 ;
        RECT 64.660 106.200 64.860 107.400 ;
        RECT 66.660 106.700 67.060 107.100 ;
        RECT 67.360 106.300 67.560 107.400 ;
        RECT 68.260 106.300 68.460 107.400 ;
        RECT 69.560 106.800 69.960 106.900 ;
        RECT 70.760 106.800 70.960 107.400 ;
        RECT 69.560 106.600 70.960 106.800 ;
        RECT 69.560 106.500 69.960 106.600 ;
        RECT 64.660 105.800 65.360 106.200 ;
        RECT 64.660 105.200 64.860 105.800 ;
        RECT 67.360 105.700 68.460 106.300 ;
        RECT 67.360 105.200 67.560 105.700 ;
        RECT 68.260 105.200 68.460 105.700 ;
        RECT 70.760 105.200 70.960 106.600 ;
        RECT 74.760 106.200 75.160 106.600 ;
        RECT 75.360 106.200 75.560 107.400 ;
        RECT 77.360 106.700 77.760 107.100 ;
        RECT 78.060 106.300 78.260 107.400 ;
        RECT 78.960 106.300 79.160 107.400 ;
        RECT 80.260 106.800 80.660 106.900 ;
        RECT 81.460 106.800 81.660 107.400 ;
        RECT 80.260 106.600 81.660 106.800 ;
        RECT 80.260 106.500 80.660 106.600 ;
        RECT 75.360 105.800 76.060 106.200 ;
        RECT 75.360 105.200 75.560 105.800 ;
        RECT 78.060 105.700 79.160 106.300 ;
        RECT 78.060 105.200 78.260 105.700 ;
        RECT 78.960 105.200 79.160 105.700 ;
        RECT 81.460 105.200 81.660 106.600 ;
        RECT 85.460 106.200 85.860 106.600 ;
        RECT 86.060 106.200 86.260 107.400 ;
        RECT 88.060 106.700 88.460 107.100 ;
        RECT 88.760 106.300 88.960 107.400 ;
        RECT 89.660 106.300 89.860 107.400 ;
        RECT 90.960 106.800 91.360 106.900 ;
        RECT 92.160 106.800 92.360 107.400 ;
        RECT 90.960 106.600 92.360 106.800 ;
        RECT 90.960 106.500 91.360 106.600 ;
        RECT 86.060 105.800 86.760 106.200 ;
        RECT 86.060 105.200 86.260 105.800 ;
        RECT 88.760 105.700 89.860 106.300 ;
        RECT 88.760 105.200 88.960 105.700 ;
        RECT 89.660 105.200 89.860 105.700 ;
        RECT 92.160 105.200 92.360 106.600 ;
        RECT 96.160 106.200 96.560 106.600 ;
        RECT 96.760 106.200 96.960 107.400 ;
        RECT 98.760 106.700 99.160 107.100 ;
        RECT 99.460 106.300 99.660 107.400 ;
        RECT 100.360 106.300 100.560 107.400 ;
        RECT 101.660 106.800 102.060 106.900 ;
        RECT 102.860 106.800 103.060 107.400 ;
        RECT 101.660 106.600 103.060 106.800 ;
        RECT 101.660 106.500 102.060 106.600 ;
        RECT 96.760 105.800 97.460 106.200 ;
        RECT 96.760 105.200 96.960 105.800 ;
        RECT 99.460 105.700 100.560 106.300 ;
        RECT 99.460 105.200 99.660 105.700 ;
        RECT 100.360 105.200 100.560 105.700 ;
        RECT 102.860 105.200 103.060 106.600 ;
        RECT 106.860 106.200 107.260 106.600 ;
        RECT 107.460 106.200 107.660 107.400 ;
        RECT 109.460 106.700 109.860 107.100 ;
        RECT 110.160 106.300 110.360 107.400 ;
        RECT 111.060 106.300 111.260 107.400 ;
        RECT 112.360 106.800 112.760 106.900 ;
        RECT 113.560 106.800 113.760 107.400 ;
        RECT 112.360 106.600 113.760 106.800 ;
        RECT 112.360 106.500 112.760 106.600 ;
        RECT 107.460 105.800 108.160 106.200 ;
        RECT 107.460 105.200 107.660 105.800 ;
        RECT 110.160 105.700 111.260 106.300 ;
        RECT 110.160 105.200 110.360 105.700 ;
        RECT 111.060 105.200 111.260 105.700 ;
        RECT 113.560 105.200 113.760 106.600 ;
        RECT 117.560 106.200 117.960 106.600 ;
        RECT 118.160 106.200 118.360 107.400 ;
        RECT 120.160 106.700 120.560 107.100 ;
        RECT 120.860 106.300 121.060 107.400 ;
        RECT 121.760 106.300 121.960 107.400 ;
        RECT 123.060 106.800 123.460 106.900 ;
        RECT 124.260 106.800 124.460 107.400 ;
        RECT 123.060 106.600 124.460 106.800 ;
        RECT 123.060 106.500 123.460 106.600 ;
        RECT 118.160 105.800 118.860 106.200 ;
        RECT 118.160 105.200 118.360 105.800 ;
        RECT 120.860 105.700 121.960 106.300 ;
        RECT 120.860 105.200 121.060 105.700 ;
        RECT 121.760 105.200 121.960 105.700 ;
        RECT 124.260 105.200 124.460 106.600 ;
        RECT 45.260 102.900 45.660 105.200 ;
        RECT 47.160 102.900 47.560 105.200 ;
        RECT 47.960 102.900 48.360 105.200 ;
        RECT 48.860 102.900 49.260 105.200 ;
        RECT 49.660 102.900 50.060 105.200 ;
        RECT 51.360 102.900 51.760 105.200 ;
        RECT 53.860 102.900 54.260 105.200 ;
        RECT 55.760 102.900 56.160 105.200 ;
        RECT 56.560 102.900 56.960 105.200 ;
        RECT 57.460 102.900 57.860 105.200 ;
        RECT 58.260 102.900 58.660 105.200 ;
        RECT 59.960 102.900 60.360 105.200 ;
        RECT 64.560 102.900 64.960 105.200 ;
        RECT 66.460 102.900 66.860 105.200 ;
        RECT 67.260 102.900 67.660 105.200 ;
        RECT 68.160 102.900 68.560 105.200 ;
        RECT 68.960 102.900 69.360 105.200 ;
        RECT 70.660 102.900 71.060 105.200 ;
        RECT 75.260 102.900 75.660 105.200 ;
        RECT 77.160 102.900 77.560 105.200 ;
        RECT 77.960 102.900 78.360 105.200 ;
        RECT 78.860 102.900 79.260 105.200 ;
        RECT 79.660 102.900 80.060 105.200 ;
        RECT 81.360 102.900 81.760 105.200 ;
        RECT 85.960 102.900 86.360 105.200 ;
        RECT 87.860 102.900 88.260 105.200 ;
        RECT 88.660 102.900 89.060 105.200 ;
        RECT 89.560 102.900 89.960 105.200 ;
        RECT 90.360 102.900 90.760 105.200 ;
        RECT 92.060 102.900 92.460 105.200 ;
        RECT 96.660 102.900 97.060 105.200 ;
        RECT 98.560 102.900 98.960 105.200 ;
        RECT 99.360 102.900 99.760 105.200 ;
        RECT 100.260 102.900 100.660 105.200 ;
        RECT 101.060 102.900 101.460 105.200 ;
        RECT 102.760 102.900 103.160 105.200 ;
        RECT 107.360 102.900 107.760 105.200 ;
        RECT 109.260 102.900 109.660 105.200 ;
        RECT 110.060 102.900 110.460 105.200 ;
        RECT 110.960 102.900 111.360 105.200 ;
        RECT 111.760 102.900 112.160 105.200 ;
        RECT 113.460 102.900 113.860 105.200 ;
        RECT 118.060 102.900 118.460 105.200 ;
        RECT 119.960 102.900 120.360 105.200 ;
        RECT 120.760 102.900 121.160 105.200 ;
        RECT 121.660 102.900 122.060 105.200 ;
        RECT 122.460 102.900 122.860 105.200 ;
        RECT 124.160 102.900 124.560 105.200 ;
        RECT 46.060 98.900 46.460 100.200 ;
        RECT 47.860 98.900 48.260 100.200 ;
        RECT 54.660 98.900 55.060 100.200 ;
        RECT 56.460 98.900 56.860 100.200 ;
        RECT 65.360 98.900 65.760 100.200 ;
        RECT 67.160 98.900 67.560 100.200 ;
        RECT 76.060 98.900 76.460 100.200 ;
        RECT 77.860 98.900 78.260 100.200 ;
        RECT 86.760 98.900 87.160 100.200 ;
        RECT 88.560 98.900 88.960 100.200 ;
        RECT 97.460 98.900 97.860 100.200 ;
        RECT 99.260 98.900 99.660 100.200 ;
        RECT 108.160 98.900 108.560 100.200 ;
        RECT 109.960 98.900 110.360 100.200 ;
        RECT 118.860 98.900 119.260 100.200 ;
        RECT 120.660 98.900 121.060 100.200 ;
        RECT 46.160 98.500 46.360 98.900 ;
        RECT 47.960 98.500 48.160 98.900 ;
        RECT 46.160 98.300 48.160 98.500 ;
        RECT 54.760 98.500 54.960 98.900 ;
        RECT 56.560 98.500 56.760 98.900 ;
        RECT 54.760 98.300 56.760 98.500 ;
        RECT 65.460 98.500 65.660 98.900 ;
        RECT 67.260 98.500 67.460 98.900 ;
        RECT 65.460 98.300 67.460 98.500 ;
        RECT 76.160 98.500 76.360 98.900 ;
        RECT 77.960 98.500 78.160 98.900 ;
        RECT 76.160 98.300 78.160 98.500 ;
        RECT 86.860 98.500 87.060 98.900 ;
        RECT 88.660 98.500 88.860 98.900 ;
        RECT 86.860 98.300 88.860 98.500 ;
        RECT 97.560 98.500 97.760 98.900 ;
        RECT 99.360 98.500 99.560 98.900 ;
        RECT 97.560 98.300 99.560 98.500 ;
        RECT 108.260 98.500 108.460 98.900 ;
        RECT 110.060 98.500 110.260 98.900 ;
        RECT 108.260 98.300 110.260 98.500 ;
        RECT 118.960 98.500 119.160 98.900 ;
        RECT 120.760 98.500 120.960 98.900 ;
        RECT 118.960 98.300 120.960 98.500 ;
        RECT 47.960 98.200 48.160 98.300 ;
        RECT 56.560 98.200 56.760 98.300 ;
        RECT 67.260 98.200 67.460 98.300 ;
        RECT 77.960 98.200 78.160 98.300 ;
        RECT 88.660 98.200 88.860 98.300 ;
        RECT 99.360 98.200 99.560 98.300 ;
        RECT 110.060 98.200 110.260 98.300 ;
        RECT 120.760 98.200 120.960 98.300 ;
        RECT 46.360 97.600 46.760 98.000 ;
        RECT 47.160 97.100 47.760 97.700 ;
        RECT 47.960 97.600 48.560 98.200 ;
        RECT 47.960 96.900 48.160 97.600 ;
        RECT 49.960 97.500 50.560 98.100 ;
        RECT 50.860 97.100 51.460 97.700 ;
        RECT 54.960 97.600 55.360 98.000 ;
        RECT 55.760 97.100 56.360 97.700 ;
        RECT 56.560 97.600 57.160 98.200 ;
        RECT 56.560 96.900 56.760 97.600 ;
        RECT 58.560 97.500 59.160 98.100 ;
        RECT 59.460 97.100 60.060 97.700 ;
        RECT 65.660 97.600 66.060 98.000 ;
        RECT 66.460 97.100 67.060 97.700 ;
        RECT 67.260 97.600 67.860 98.200 ;
        RECT 67.260 96.900 67.460 97.600 ;
        RECT 69.260 97.500 69.860 98.100 ;
        RECT 70.160 97.100 70.760 97.700 ;
        RECT 76.360 97.600 76.760 98.000 ;
        RECT 77.160 97.100 77.760 97.700 ;
        RECT 77.960 97.600 78.560 98.200 ;
        RECT 77.960 96.900 78.160 97.600 ;
        RECT 79.960 97.500 80.560 98.100 ;
        RECT 80.860 97.100 81.460 97.700 ;
        RECT 87.060 97.600 87.460 98.000 ;
        RECT 87.860 97.100 88.460 97.700 ;
        RECT 88.660 97.600 89.260 98.200 ;
        RECT 88.660 96.900 88.860 97.600 ;
        RECT 90.660 97.500 91.260 98.100 ;
        RECT 91.560 97.100 92.160 97.700 ;
        RECT 97.760 97.600 98.160 98.000 ;
        RECT 98.560 97.100 99.160 97.700 ;
        RECT 99.360 97.600 99.960 98.200 ;
        RECT 99.360 96.900 99.560 97.600 ;
        RECT 101.360 97.500 101.960 98.100 ;
        RECT 102.260 97.100 102.860 97.700 ;
        RECT 108.460 97.600 108.860 98.000 ;
        RECT 109.260 97.100 109.860 97.700 ;
        RECT 110.060 97.600 110.660 98.200 ;
        RECT 110.060 96.900 110.260 97.600 ;
        RECT 112.060 97.500 112.660 98.100 ;
        RECT 112.960 97.100 113.560 97.700 ;
        RECT 119.160 97.600 119.560 98.000 ;
        RECT 119.960 97.100 120.560 97.700 ;
        RECT 120.760 97.600 121.360 98.200 ;
        RECT 120.760 96.900 120.960 97.600 ;
        RECT 122.760 97.500 123.360 98.100 ;
        RECT 123.660 97.100 124.260 97.700 ;
        RECT 46.060 96.100 46.460 96.900 ;
        RECT 46.960 96.100 47.360 96.900 ;
        RECT 47.860 96.100 48.260 96.900 ;
        RECT 49.760 96.100 50.160 96.900 ;
        RECT 50.660 96.100 51.060 96.900 ;
        RECT 54.660 96.100 55.060 96.900 ;
        RECT 55.560 96.100 55.960 96.900 ;
        RECT 56.460 96.100 56.860 96.900 ;
        RECT 58.360 96.100 58.760 96.900 ;
        RECT 59.260 96.100 59.660 96.900 ;
        RECT 65.360 96.100 65.760 96.900 ;
        RECT 66.260 96.100 66.660 96.900 ;
        RECT 67.160 96.100 67.560 96.900 ;
        RECT 69.060 96.100 69.460 96.900 ;
        RECT 69.960 96.100 70.360 96.900 ;
        RECT 76.060 96.100 76.460 96.900 ;
        RECT 76.960 96.100 77.360 96.900 ;
        RECT 77.860 96.100 78.260 96.900 ;
        RECT 79.760 96.100 80.160 96.900 ;
        RECT 80.660 96.100 81.060 96.900 ;
        RECT 86.760 96.100 87.160 96.900 ;
        RECT 87.660 96.100 88.060 96.900 ;
        RECT 88.560 96.100 88.960 96.900 ;
        RECT 90.460 96.100 90.860 96.900 ;
        RECT 91.360 96.100 91.760 96.900 ;
        RECT 97.460 96.100 97.860 96.900 ;
        RECT 98.360 96.100 98.760 96.900 ;
        RECT 99.260 96.100 99.660 96.900 ;
        RECT 101.160 96.100 101.560 96.900 ;
        RECT 102.060 96.100 102.460 96.900 ;
        RECT 108.160 96.100 108.560 96.900 ;
        RECT 109.060 96.100 109.460 96.900 ;
        RECT 109.960 96.100 110.360 96.900 ;
        RECT 111.860 96.100 112.260 96.900 ;
        RECT 112.760 96.100 113.160 96.900 ;
        RECT 118.860 96.100 119.260 96.900 ;
        RECT 119.760 96.100 120.160 96.900 ;
        RECT 120.660 96.100 121.060 96.900 ;
        RECT 122.560 96.100 122.960 96.900 ;
        RECT 123.460 96.100 123.860 96.900 ;
        RECT 46.060 92.700 46.460 93.500 ;
        RECT 46.960 92.700 47.360 93.500 ;
        RECT 47.860 92.700 48.260 93.500 ;
        RECT 49.760 92.700 50.160 93.500 ;
        RECT 50.660 92.700 51.060 93.500 ;
        RECT 51.560 92.700 51.960 93.500 ;
        RECT 54.660 92.700 55.060 93.500 ;
        RECT 55.560 92.700 55.960 93.500 ;
        RECT 56.460 92.700 56.860 93.500 ;
        RECT 58.360 92.700 58.760 93.500 ;
        RECT 59.260 92.700 59.660 93.500 ;
        RECT 60.160 92.700 60.560 93.500 ;
        RECT 65.360 92.700 65.760 93.500 ;
        RECT 66.260 92.700 66.660 93.500 ;
        RECT 67.160 92.700 67.560 93.500 ;
        RECT 69.060 92.700 69.460 93.500 ;
        RECT 69.960 92.700 70.360 93.500 ;
        RECT 70.860 92.700 71.260 93.500 ;
        RECT 76.060 92.700 76.460 93.500 ;
        RECT 76.960 92.700 77.360 93.500 ;
        RECT 77.860 92.700 78.260 93.500 ;
        RECT 79.760 92.700 80.160 93.500 ;
        RECT 80.660 92.700 81.060 93.500 ;
        RECT 81.560 92.700 81.960 93.500 ;
        RECT 86.760 92.700 87.160 93.500 ;
        RECT 87.660 92.700 88.060 93.500 ;
        RECT 88.560 92.700 88.960 93.500 ;
        RECT 90.460 92.700 90.860 93.500 ;
        RECT 91.360 92.700 91.760 93.500 ;
        RECT 92.260 92.700 92.660 93.500 ;
        RECT 97.460 92.700 97.860 93.500 ;
        RECT 98.360 92.700 98.760 93.500 ;
        RECT 99.260 92.700 99.660 93.500 ;
        RECT 101.160 92.700 101.560 93.500 ;
        RECT 102.060 92.700 102.460 93.500 ;
        RECT 102.960 92.700 103.360 93.500 ;
        RECT 108.160 92.700 108.560 93.500 ;
        RECT 109.060 92.700 109.460 93.500 ;
        RECT 109.960 92.700 110.360 93.500 ;
        RECT 111.860 92.700 112.260 93.500 ;
        RECT 112.760 92.700 113.160 93.500 ;
        RECT 113.660 92.700 114.060 93.500 ;
        RECT 118.860 92.700 119.260 93.500 ;
        RECT 119.760 92.700 120.160 93.500 ;
        RECT 120.660 92.700 121.060 93.500 ;
        RECT 122.560 92.700 122.960 93.500 ;
        RECT 123.460 92.700 123.860 93.500 ;
        RECT 124.360 92.700 124.760 93.500 ;
        RECT 47.960 92.000 48.160 92.700 ;
        RECT 51.660 92.000 51.860 92.700 ;
        RECT 56.560 92.000 56.760 92.700 ;
        RECT 60.260 92.000 60.460 92.700 ;
        RECT 67.260 92.000 67.460 92.700 ;
        RECT 70.960 92.000 71.160 92.700 ;
        RECT 77.960 92.000 78.160 92.700 ;
        RECT 81.660 92.000 81.860 92.700 ;
        RECT 88.660 92.000 88.860 92.700 ;
        RECT 92.360 92.000 92.560 92.700 ;
        RECT 99.360 92.000 99.560 92.700 ;
        RECT 103.060 92.000 103.260 92.700 ;
        RECT 110.060 92.000 110.260 92.700 ;
        RECT 113.760 92.000 113.960 92.700 ;
        RECT 120.760 92.000 120.960 92.700 ;
        RECT 124.460 92.000 124.660 92.700 ;
        RECT 46.360 91.600 46.760 92.000 ;
        RECT 45.460 91.100 45.860 91.500 ;
        RECT 47.960 91.400 48.560 92.000 ;
        RECT 50.060 91.600 50.460 92.000 ;
        RECT 51.660 91.400 52.260 92.000 ;
        RECT 54.960 91.600 55.360 92.000 ;
        RECT 47.960 91.300 48.160 91.400 ;
        RECT 51.660 91.300 51.860 91.400 ;
        RECT 46.160 91.100 48.160 91.300 ;
        RECT 46.160 90.700 46.360 91.100 ;
        RECT 47.960 90.700 48.160 91.100 ;
        RECT 49.860 91.100 51.860 91.300 ;
        RECT 54.060 91.100 54.460 91.500 ;
        RECT 56.560 91.400 57.160 92.000 ;
        RECT 58.660 91.600 59.060 92.000 ;
        RECT 60.260 91.400 60.860 92.000 ;
        RECT 65.660 91.600 66.060 92.000 ;
        RECT 56.560 91.300 56.760 91.400 ;
        RECT 60.260 91.300 60.460 91.400 ;
        RECT 54.760 91.100 56.760 91.300 ;
        RECT 49.860 90.700 50.060 91.100 ;
        RECT 51.660 90.700 51.860 91.100 ;
        RECT 54.760 90.700 54.960 91.100 ;
        RECT 56.560 90.700 56.760 91.100 ;
        RECT 58.460 91.100 60.460 91.300 ;
        RECT 64.760 91.100 65.160 91.500 ;
        RECT 67.260 91.400 67.860 92.000 ;
        RECT 69.360 91.600 69.760 92.000 ;
        RECT 70.960 91.400 71.560 92.000 ;
        RECT 76.360 91.600 76.760 92.000 ;
        RECT 67.260 91.300 67.460 91.400 ;
        RECT 70.960 91.300 71.160 91.400 ;
        RECT 65.460 91.100 67.460 91.300 ;
        RECT 58.460 90.700 58.660 91.100 ;
        RECT 60.260 90.700 60.460 91.100 ;
        RECT 65.460 90.700 65.660 91.100 ;
        RECT 67.260 90.700 67.460 91.100 ;
        RECT 69.160 91.100 71.160 91.300 ;
        RECT 75.460 91.100 75.860 91.500 ;
        RECT 77.960 91.400 78.560 92.000 ;
        RECT 80.060 91.600 80.460 92.000 ;
        RECT 81.660 91.400 82.260 92.000 ;
        RECT 87.060 91.600 87.460 92.000 ;
        RECT 77.960 91.300 78.160 91.400 ;
        RECT 81.660 91.300 81.860 91.400 ;
        RECT 76.160 91.100 78.160 91.300 ;
        RECT 69.160 90.700 69.360 91.100 ;
        RECT 70.960 90.700 71.160 91.100 ;
        RECT 76.160 90.700 76.360 91.100 ;
        RECT 77.960 90.700 78.160 91.100 ;
        RECT 79.860 91.100 81.860 91.300 ;
        RECT 86.160 91.100 86.560 91.500 ;
        RECT 88.660 91.400 89.260 92.000 ;
        RECT 90.760 91.600 91.160 92.000 ;
        RECT 92.360 91.400 92.960 92.000 ;
        RECT 97.760 91.600 98.160 92.000 ;
        RECT 88.660 91.300 88.860 91.400 ;
        RECT 92.360 91.300 92.560 91.400 ;
        RECT 86.860 91.100 88.860 91.300 ;
        RECT 79.860 90.700 80.060 91.100 ;
        RECT 81.660 90.700 81.860 91.100 ;
        RECT 86.860 90.700 87.060 91.100 ;
        RECT 88.660 90.700 88.860 91.100 ;
        RECT 90.560 91.100 92.560 91.300 ;
        RECT 96.860 91.100 97.260 91.500 ;
        RECT 99.360 91.400 99.960 92.000 ;
        RECT 101.460 91.600 101.860 92.000 ;
        RECT 103.060 91.400 103.660 92.000 ;
        RECT 108.460 91.600 108.860 92.000 ;
        RECT 99.360 91.300 99.560 91.400 ;
        RECT 103.060 91.300 103.260 91.400 ;
        RECT 97.560 91.100 99.560 91.300 ;
        RECT 90.560 90.700 90.760 91.100 ;
        RECT 92.360 90.700 92.560 91.100 ;
        RECT 97.560 90.700 97.760 91.100 ;
        RECT 99.360 90.700 99.560 91.100 ;
        RECT 101.260 91.100 103.260 91.300 ;
        RECT 107.560 91.100 107.960 91.500 ;
        RECT 110.060 91.400 110.660 92.000 ;
        RECT 112.160 91.600 112.560 92.000 ;
        RECT 113.760 91.400 114.360 92.000 ;
        RECT 119.160 91.600 119.560 92.000 ;
        RECT 110.060 91.300 110.260 91.400 ;
        RECT 113.760 91.300 113.960 91.400 ;
        RECT 108.260 91.100 110.260 91.300 ;
        RECT 101.260 90.700 101.460 91.100 ;
        RECT 103.060 90.700 103.260 91.100 ;
        RECT 108.260 90.700 108.460 91.100 ;
        RECT 110.060 90.700 110.260 91.100 ;
        RECT 111.960 91.100 113.960 91.300 ;
        RECT 118.260 91.100 118.660 91.500 ;
        RECT 120.760 91.400 121.360 92.000 ;
        RECT 122.860 91.600 123.260 92.000 ;
        RECT 124.460 91.400 125.060 92.000 ;
        RECT 120.760 91.300 120.960 91.400 ;
        RECT 124.460 91.300 124.660 91.400 ;
        RECT 118.960 91.100 120.960 91.300 ;
        RECT 111.960 90.700 112.160 91.100 ;
        RECT 113.760 90.700 113.960 91.100 ;
        RECT 118.960 90.700 119.160 91.100 ;
        RECT 120.760 90.700 120.960 91.100 ;
        RECT 122.660 91.100 124.660 91.300 ;
        RECT 122.660 90.700 122.860 91.100 ;
        RECT 124.460 90.700 124.660 91.100 ;
        RECT 46.060 89.400 46.460 90.700 ;
        RECT 47.860 89.400 48.260 90.700 ;
        RECT 49.760 89.400 50.160 90.700 ;
        RECT 51.560 89.400 51.960 90.700 ;
        RECT 54.660 89.400 55.060 90.700 ;
        RECT 56.460 89.400 56.860 90.700 ;
        RECT 58.360 89.400 58.760 90.700 ;
        RECT 60.160 89.400 60.560 90.700 ;
        RECT 65.360 89.400 65.760 90.700 ;
        RECT 67.160 89.400 67.560 90.700 ;
        RECT 69.060 89.400 69.460 90.700 ;
        RECT 70.860 89.400 71.260 90.700 ;
        RECT 76.060 89.400 76.460 90.700 ;
        RECT 77.860 89.400 78.260 90.700 ;
        RECT 79.760 89.400 80.160 90.700 ;
        RECT 81.560 89.400 81.960 90.700 ;
        RECT 86.760 89.400 87.160 90.700 ;
        RECT 88.560 89.400 88.960 90.700 ;
        RECT 90.460 89.400 90.860 90.700 ;
        RECT 92.260 89.400 92.660 90.700 ;
        RECT 97.460 89.400 97.860 90.700 ;
        RECT 99.260 89.400 99.660 90.700 ;
        RECT 101.160 89.400 101.560 90.700 ;
        RECT 102.960 89.400 103.360 90.700 ;
        RECT 108.160 89.400 108.560 90.700 ;
        RECT 109.960 89.400 110.360 90.700 ;
        RECT 111.860 89.400 112.260 90.700 ;
        RECT 113.660 89.400 114.060 90.700 ;
        RECT 118.860 89.400 119.260 90.700 ;
        RECT 120.660 89.400 121.060 90.700 ;
        RECT 122.560 89.400 122.960 90.700 ;
        RECT 124.360 89.400 124.760 90.700 ;
        RECT 46.060 85.700 46.460 87.000 ;
        RECT 47.860 85.700 48.260 87.000 ;
        RECT 49.760 85.700 50.160 87.000 ;
        RECT 51.560 85.700 51.960 87.000 ;
        RECT 54.660 85.700 55.060 87.000 ;
        RECT 56.460 85.700 56.860 87.000 ;
        RECT 58.360 85.700 58.760 87.000 ;
        RECT 60.160 85.700 60.560 87.000 ;
        RECT 65.360 85.700 65.760 87.000 ;
        RECT 67.160 85.700 67.560 87.000 ;
        RECT 69.060 85.700 69.460 87.000 ;
        RECT 70.860 85.700 71.260 87.000 ;
        RECT 76.060 85.700 76.460 87.000 ;
        RECT 77.860 85.700 78.260 87.000 ;
        RECT 79.760 85.700 80.160 87.000 ;
        RECT 81.560 85.700 81.960 87.000 ;
        RECT 86.760 85.700 87.160 87.000 ;
        RECT 88.560 85.700 88.960 87.000 ;
        RECT 90.460 85.700 90.860 87.000 ;
        RECT 92.260 85.700 92.660 87.000 ;
        RECT 97.460 85.700 97.860 87.000 ;
        RECT 99.260 85.700 99.660 87.000 ;
        RECT 101.160 85.700 101.560 87.000 ;
        RECT 102.960 85.700 103.360 87.000 ;
        RECT 108.160 85.700 108.560 87.000 ;
        RECT 109.960 85.700 110.360 87.000 ;
        RECT 111.860 85.700 112.260 87.000 ;
        RECT 113.660 85.700 114.060 87.000 ;
        RECT 118.860 85.700 119.260 87.000 ;
        RECT 120.660 85.700 121.060 87.000 ;
        RECT 122.560 85.700 122.960 87.000 ;
        RECT 124.360 85.700 124.760 87.000 ;
        RECT 45.360 84.800 45.960 85.400 ;
        RECT 46.160 85.300 46.360 85.700 ;
        RECT 47.960 85.300 48.160 85.700 ;
        RECT 49.860 85.300 50.060 85.700 ;
        RECT 51.660 85.300 51.860 85.700 ;
        RECT 46.160 85.100 48.160 85.300 ;
        RECT 47.960 85.000 48.160 85.100 ;
        RECT 46.260 84.300 46.860 84.900 ;
        RECT 47.960 84.400 48.560 85.000 ;
        RECT 49.160 84.900 49.560 85.300 ;
        RECT 49.860 85.100 51.860 85.300 ;
        RECT 51.660 85.000 51.860 85.100 ;
        RECT 47.260 84.000 47.660 84.400 ;
        RECT 47.960 83.700 48.160 84.400 ;
        RECT 49.960 84.300 50.560 84.900 ;
        RECT 51.660 84.400 52.260 85.000 ;
        RECT 53.960 84.800 54.560 85.400 ;
        RECT 54.760 85.300 54.960 85.700 ;
        RECT 56.560 85.300 56.760 85.700 ;
        RECT 58.460 85.300 58.660 85.700 ;
        RECT 60.260 85.300 60.460 85.700 ;
        RECT 54.760 85.100 56.760 85.300 ;
        RECT 56.560 85.000 56.760 85.100 ;
        RECT 51.660 83.700 51.860 84.400 ;
        RECT 54.860 84.300 55.460 84.900 ;
        RECT 56.560 84.400 57.160 85.000 ;
        RECT 57.760 84.900 58.160 85.300 ;
        RECT 58.460 85.100 60.460 85.300 ;
        RECT 60.260 85.000 60.460 85.100 ;
        RECT 55.860 84.000 56.260 84.400 ;
        RECT 56.560 83.700 56.760 84.400 ;
        RECT 58.560 84.300 59.160 84.900 ;
        RECT 60.260 84.400 60.860 85.000 ;
        RECT 64.660 84.800 65.260 85.400 ;
        RECT 65.460 85.300 65.660 85.700 ;
        RECT 67.260 85.300 67.460 85.700 ;
        RECT 69.160 85.300 69.360 85.700 ;
        RECT 70.960 85.300 71.160 85.700 ;
        RECT 65.460 85.100 67.460 85.300 ;
        RECT 67.260 85.000 67.460 85.100 ;
        RECT 60.260 83.700 60.460 84.400 ;
        RECT 65.560 84.300 66.160 84.900 ;
        RECT 67.260 84.400 67.860 85.000 ;
        RECT 68.460 84.900 68.860 85.300 ;
        RECT 69.160 85.100 71.160 85.300 ;
        RECT 70.960 85.000 71.160 85.100 ;
        RECT 66.560 84.000 66.960 84.400 ;
        RECT 67.260 83.700 67.460 84.400 ;
        RECT 69.260 84.300 69.860 84.900 ;
        RECT 70.960 84.400 71.560 85.000 ;
        RECT 75.360 84.800 75.960 85.400 ;
        RECT 76.160 85.300 76.360 85.700 ;
        RECT 77.960 85.300 78.160 85.700 ;
        RECT 79.860 85.300 80.060 85.700 ;
        RECT 81.660 85.300 81.860 85.700 ;
        RECT 76.160 85.100 78.160 85.300 ;
        RECT 77.960 85.000 78.160 85.100 ;
        RECT 70.960 83.700 71.160 84.400 ;
        RECT 76.260 84.300 76.860 84.900 ;
        RECT 77.960 84.400 78.560 85.000 ;
        RECT 79.160 84.900 79.560 85.300 ;
        RECT 79.860 85.100 81.860 85.300 ;
        RECT 81.660 85.000 81.860 85.100 ;
        RECT 77.260 84.000 77.660 84.400 ;
        RECT 77.960 83.700 78.160 84.400 ;
        RECT 79.960 84.300 80.560 84.900 ;
        RECT 81.660 84.400 82.260 85.000 ;
        RECT 86.060 84.800 86.660 85.400 ;
        RECT 86.860 85.300 87.060 85.700 ;
        RECT 88.660 85.300 88.860 85.700 ;
        RECT 90.560 85.300 90.760 85.700 ;
        RECT 92.360 85.300 92.560 85.700 ;
        RECT 86.860 85.100 88.860 85.300 ;
        RECT 88.660 85.000 88.860 85.100 ;
        RECT 81.660 83.700 81.860 84.400 ;
        RECT 86.960 84.300 87.560 84.900 ;
        RECT 88.660 84.400 89.260 85.000 ;
        RECT 89.860 84.900 90.260 85.300 ;
        RECT 90.560 85.100 92.560 85.300 ;
        RECT 92.360 85.000 92.560 85.100 ;
        RECT 87.960 84.000 88.360 84.400 ;
        RECT 88.660 83.700 88.860 84.400 ;
        RECT 90.660 84.300 91.260 84.900 ;
        RECT 92.360 84.400 92.960 85.000 ;
        RECT 96.760 84.800 97.360 85.400 ;
        RECT 97.560 85.300 97.760 85.700 ;
        RECT 99.360 85.300 99.560 85.700 ;
        RECT 101.260 85.300 101.460 85.700 ;
        RECT 103.060 85.300 103.260 85.700 ;
        RECT 97.560 85.100 99.560 85.300 ;
        RECT 99.360 85.000 99.560 85.100 ;
        RECT 92.360 83.700 92.560 84.400 ;
        RECT 97.660 84.300 98.260 84.900 ;
        RECT 99.360 84.400 99.960 85.000 ;
        RECT 100.560 84.900 100.960 85.300 ;
        RECT 101.260 85.100 103.260 85.300 ;
        RECT 103.060 85.000 103.260 85.100 ;
        RECT 98.660 84.000 99.060 84.400 ;
        RECT 99.360 83.700 99.560 84.400 ;
        RECT 101.360 84.300 101.960 84.900 ;
        RECT 103.060 84.400 103.660 85.000 ;
        RECT 107.460 84.800 108.060 85.400 ;
        RECT 108.260 85.300 108.460 85.700 ;
        RECT 110.060 85.300 110.260 85.700 ;
        RECT 111.960 85.300 112.160 85.700 ;
        RECT 113.760 85.300 113.960 85.700 ;
        RECT 108.260 85.100 110.260 85.300 ;
        RECT 110.060 85.000 110.260 85.100 ;
        RECT 103.060 83.700 103.260 84.400 ;
        RECT 108.360 84.300 108.960 84.900 ;
        RECT 110.060 84.400 110.660 85.000 ;
        RECT 111.260 84.900 111.660 85.300 ;
        RECT 111.960 85.100 113.960 85.300 ;
        RECT 113.760 85.000 113.960 85.100 ;
        RECT 109.360 84.000 109.760 84.400 ;
        RECT 110.060 83.700 110.260 84.400 ;
        RECT 112.060 84.300 112.660 84.900 ;
        RECT 113.760 84.400 114.360 85.000 ;
        RECT 118.160 84.800 118.760 85.400 ;
        RECT 118.960 85.300 119.160 85.700 ;
        RECT 120.760 85.300 120.960 85.700 ;
        RECT 122.660 85.300 122.860 85.700 ;
        RECT 124.460 85.300 124.660 85.700 ;
        RECT 118.960 85.100 120.960 85.300 ;
        RECT 120.760 85.000 120.960 85.100 ;
        RECT 113.760 83.700 113.960 84.400 ;
        RECT 119.060 84.300 119.660 84.900 ;
        RECT 120.760 84.400 121.360 85.000 ;
        RECT 121.960 84.900 122.360 85.300 ;
        RECT 122.660 85.100 124.660 85.300 ;
        RECT 124.460 85.000 124.660 85.100 ;
        RECT 120.060 84.000 120.460 84.400 ;
        RECT 120.760 83.700 120.960 84.400 ;
        RECT 122.760 84.300 123.360 84.900 ;
        RECT 124.460 84.400 125.060 85.000 ;
        RECT 124.460 83.700 124.660 84.400 ;
        RECT 46.060 82.900 46.460 83.700 ;
        RECT 46.960 82.900 47.360 83.700 ;
        RECT 47.860 82.900 48.260 83.700 ;
        RECT 49.760 82.900 50.160 83.700 ;
        RECT 50.660 82.900 51.060 83.700 ;
        RECT 51.560 82.900 51.960 83.700 ;
        RECT 54.660 82.900 55.060 83.700 ;
        RECT 55.560 82.900 55.960 83.700 ;
        RECT 56.460 82.900 56.860 83.700 ;
        RECT 58.360 82.900 58.760 83.700 ;
        RECT 59.260 82.900 59.660 83.700 ;
        RECT 60.160 82.900 60.560 83.700 ;
        RECT 65.360 82.900 65.760 83.700 ;
        RECT 66.260 82.900 66.660 83.700 ;
        RECT 67.160 82.900 67.560 83.700 ;
        RECT 69.060 82.900 69.460 83.700 ;
        RECT 69.960 82.900 70.360 83.700 ;
        RECT 70.860 82.900 71.260 83.700 ;
        RECT 76.060 82.900 76.460 83.700 ;
        RECT 76.960 82.900 77.360 83.700 ;
        RECT 77.860 82.900 78.260 83.700 ;
        RECT 79.760 82.900 80.160 83.700 ;
        RECT 80.660 82.900 81.060 83.700 ;
        RECT 81.560 82.900 81.960 83.700 ;
        RECT 86.760 82.900 87.160 83.700 ;
        RECT 87.660 82.900 88.060 83.700 ;
        RECT 88.560 82.900 88.960 83.700 ;
        RECT 90.460 82.900 90.860 83.700 ;
        RECT 91.360 82.900 91.760 83.700 ;
        RECT 92.260 82.900 92.660 83.700 ;
        RECT 97.460 82.900 97.860 83.700 ;
        RECT 98.360 82.900 98.760 83.700 ;
        RECT 99.260 82.900 99.660 83.700 ;
        RECT 101.160 82.900 101.560 83.700 ;
        RECT 102.060 82.900 102.460 83.700 ;
        RECT 102.960 82.900 103.360 83.700 ;
        RECT 108.160 82.900 108.560 83.700 ;
        RECT 109.060 82.900 109.460 83.700 ;
        RECT 109.960 82.900 110.360 83.700 ;
        RECT 111.860 82.900 112.260 83.700 ;
        RECT 112.760 82.900 113.160 83.700 ;
        RECT 113.660 82.900 114.060 83.700 ;
        RECT 118.860 82.900 119.260 83.700 ;
        RECT 119.760 82.900 120.160 83.700 ;
        RECT 120.660 82.900 121.060 83.700 ;
        RECT 122.560 82.900 122.960 83.700 ;
        RECT 123.460 82.900 123.860 83.700 ;
        RECT 124.360 82.900 124.760 83.700 ;
        RECT 87.050 66.650 87.450 67.050 ;
        RECT 78.150 66.150 78.550 66.550 ;
        RECT 58.700 62.050 59.500 62.450 ;
        RECT 56.900 60.550 57.700 60.950 ;
        RECT 44.950 56.950 45.650 57.250 ;
        RECT 44.950 56.550 46.950 56.950 ;
        RECT 45.250 44.050 45.650 56.150 ;
        RECT 46.550 55.750 46.950 56.550 ;
        RECT 47.850 55.750 48.250 58.650 ;
        RECT 55.100 57.550 55.900 57.950 ;
        RECT 55.400 56.050 55.900 57.550 ;
        RECT 57.000 56.050 57.600 60.550 ;
        RECT 58.800 56.050 59.400 62.050 ;
        RECT 77.850 61.050 78.250 65.850 ;
        RECT 79.650 62.850 80.050 64.950 ;
        RECT 79.650 62.450 80.350 62.850 ;
        RECT 64.060 56.050 64.460 59.750 ;
        RECT 65.860 56.050 66.260 59.750 ;
        RECT 66.660 56.050 67.060 59.750 ;
        RECT 73.350 59.650 73.750 60.550 ;
        RECT 73.350 59.550 73.850 59.650 ;
        RECT 73.350 59.150 74.050 59.550 ;
        RECT 71.850 57.850 72.550 58.550 ;
        RECT 54.600 55.750 61.000 56.050 ;
        RECT 46.550 55.350 48.250 55.750 ;
        RECT 47.850 49.550 48.250 55.350 ;
        RECT 48.550 55.150 49.150 55.750 ;
        RECT 54.600 54.450 54.900 55.750 ;
        RECT 55.400 55.650 61.000 55.750 ;
        RECT 60.500 55.550 61.000 55.650 ;
        RECT 60.500 54.850 61.200 55.550 ;
        RECT 63.460 55.250 63.960 55.750 ;
        RECT 64.160 55.650 64.360 56.050 ;
        RECT 64.160 55.250 65.660 55.650 ;
        RECT 66.760 55.350 66.960 56.050 ;
        RECT 66.760 55.250 67.160 55.350 ;
        RECT 64.160 54.650 64.360 55.250 ;
        RECT 66.750 55.150 67.850 55.250 ;
        RECT 65.960 54.950 67.850 55.150 ;
        RECT 65.960 54.650 66.160 54.950 ;
        RECT 53.300 54.150 54.900 54.450 ;
        RECT 53.300 54.050 54.100 54.150 ;
        RECT 53.500 50.450 54.100 54.050 ;
        RECT 55.400 52.050 60.200 52.450 ;
        RECT 56.200 51.450 59.600 52.050 ;
        RECT 55.400 51.050 60.200 51.450 ;
        RECT 60.500 50.450 61.200 51.150 ;
        RECT 51.500 50.050 54.100 50.450 ;
        RECT 64.060 49.850 64.460 54.650 ;
        RECT 65.860 49.850 66.260 54.650 ;
        RECT 67.550 54.150 67.850 54.950 ;
        RECT 67.550 53.450 68.150 54.150 ;
        RECT 68.350 53.150 68.850 53.750 ;
        RECT 71.050 53.650 71.450 57.450 ;
        RECT 71.850 53.650 72.250 57.850 ;
        RECT 73.350 57.750 73.750 59.150 ;
        RECT 74.150 57.450 74.550 58.550 ;
        RECT 74.050 57.050 74.550 57.450 ;
        RECT 68.450 51.550 68.850 53.150 ;
        RECT 69.350 53.150 69.950 53.250 ;
        RECT 71.150 53.150 71.350 53.650 ;
        RECT 73.350 53.450 73.750 56.650 ;
        RECT 74.150 53.850 74.550 57.050 ;
        RECT 73.350 53.150 74.050 53.450 ;
        RECT 69.350 52.950 71.350 53.150 ;
        RECT 69.350 52.650 69.950 52.950 ;
        RECT 71.150 52.350 71.350 52.950 ;
        RECT 71.050 50.550 71.450 52.350 ;
        RECT 73.650 51.750 74.050 53.150 ;
        RECT 76.150 52.050 76.550 60.650 ;
        RECT 77.850 59.950 78.150 61.050 ;
        RECT 77.850 59.450 78.350 59.950 ;
        RECT 77.850 57.650 78.150 59.450 ;
        RECT 78.350 58.050 78.750 58.450 ;
        RECT 77.850 53.850 78.250 57.650 ;
        RECT 78.650 51.750 79.050 57.650 ;
        RECT 73.650 51.550 74.350 51.750 ;
        RECT 73.950 51.350 74.350 51.550 ;
        RECT 78.350 51.550 79.050 51.750 ;
        RECT 78.350 51.350 78.750 51.550 ;
        RECT 79.650 50.250 80.050 62.450 ;
        RECT 80.450 60.550 81.750 60.950 ;
        RECT 80.450 50.250 80.850 60.550 ;
        RECT 81.350 50.250 81.750 60.550 ;
        RECT 82.150 50.250 82.550 64.950 ;
        RECT 83.350 62.150 83.750 66.350 ;
        RECT 84.450 61.650 84.850 63.950 ;
        RECT 83.350 61.050 83.850 61.550 ;
        RECT 84.450 60.950 85.250 61.650 ;
        RECT 87.350 60.950 87.750 66.350 ;
        RECT 83.350 51.850 83.750 60.250 ;
        RECT 84.450 56.450 84.850 60.950 ;
        RECT 87.050 60.550 87.750 60.950 ;
        RECT 86.550 55.750 86.950 60.250 ;
        RECT 87.350 56.450 87.750 60.550 ;
        RECT 86.550 55.350 87.250 55.750 ;
        RECT 86.550 51.150 86.950 55.350 ;
        RECT 45.250 43.650 47.250 44.050 ;
        RECT 49.100 43.650 49.500 45.550 ;
        RECT 50.600 43.650 51.000 45.550 ;
        RECT 52.100 43.650 52.500 45.550 ;
        RECT 53.600 43.650 54.000 45.550 ;
        RECT 55.100 43.650 55.500 45.550 ;
        RECT 45.250 33.550 45.650 43.650 ;
        RECT 46.750 40.550 47.250 43.650 ;
        RECT 46.750 40.350 48.050 40.550 ;
        RECT 46.750 40.300 48.250 40.350 ;
        RECT 48.550 40.300 48.950 40.400 ;
        RECT 46.750 40.150 48.950 40.300 ;
        RECT 47.350 40.100 48.950 40.150 ;
        RECT 47.350 40.050 48.050 40.100 ;
        RECT 48.550 40.000 48.950 40.100 ;
        RECT 49.200 40.300 49.400 43.650 ;
        RECT 50.050 40.300 50.450 40.400 ;
        RECT 49.200 40.100 50.450 40.300 ;
        RECT 49.200 39.750 49.400 40.100 ;
        RECT 50.050 40.000 50.450 40.100 ;
        RECT 50.700 40.300 50.900 43.650 ;
        RECT 51.550 40.300 51.950 40.400 ;
        RECT 50.700 40.100 51.950 40.300 ;
        RECT 50.700 39.750 50.900 40.100 ;
        RECT 51.550 40.000 51.950 40.100 ;
        RECT 52.200 40.300 52.400 43.650 ;
        RECT 53.050 40.300 53.450 40.400 ;
        RECT 52.200 40.100 53.450 40.300 ;
        RECT 52.200 39.750 52.400 40.100 ;
        RECT 53.050 40.000 53.450 40.100 ;
        RECT 53.700 40.300 53.900 43.650 ;
        RECT 54.550 40.300 54.950 40.400 ;
        RECT 53.700 40.100 54.950 40.300 ;
        RECT 53.700 39.750 53.900 40.100 ;
        RECT 54.550 40.000 54.950 40.100 ;
        RECT 55.200 40.350 55.400 43.650 ;
        RECT 55.200 40.050 57.050 40.350 ;
        RECT 55.200 39.750 55.400 40.050 ;
        RECT 48.450 37.850 48.850 39.750 ;
        RECT 49.100 37.850 49.500 39.750 ;
        RECT 50.600 37.850 51.000 39.750 ;
        RECT 51.450 37.850 51.850 39.750 ;
        RECT 52.100 37.850 52.500 39.750 ;
        RECT 53.600 37.850 54.000 39.750 ;
        RECT 54.450 37.850 54.850 39.750 ;
        RECT 55.100 37.850 55.500 39.750 ;
        RECT 48.550 37.400 48.750 37.850 ;
        RECT 49.550 37.400 50.000 37.600 ;
        RECT 48.550 37.200 50.000 37.400 ;
        RECT 51.550 37.400 51.750 37.850 ;
        RECT 52.550 37.400 53.000 37.600 ;
        RECT 51.550 37.200 53.000 37.400 ;
        RECT 54.550 37.400 54.750 37.850 ;
        RECT 55.550 37.400 56.000 37.600 ;
        RECT 54.550 37.200 56.000 37.400 ;
        RECT 48.550 36.950 48.750 37.200 ;
        RECT 49.550 36.950 49.750 37.200 ;
        RECT 51.550 36.950 51.750 37.200 ;
        RECT 52.550 36.950 52.750 37.200 ;
        RECT 54.550 36.950 54.750 37.200 ;
        RECT 55.550 36.950 55.750 37.200 ;
        RECT 48.450 34.050 48.850 36.950 ;
        RECT 48.250 33.350 48.650 33.750 ;
        RECT 44.950 32.450 45.650 33.150 ;
        RECT 49.350 32.550 49.750 36.950 ;
        RECT 51.450 34.050 51.850 36.950 ;
        RECT 51.250 33.350 51.650 33.750 ;
        RECT 52.350 32.550 52.750 36.950 ;
        RECT 54.450 34.050 54.850 36.950 ;
        RECT 54.250 33.350 54.650 33.750 ;
        RECT 55.350 32.550 55.750 36.950 ;
        RECT 56.750 36.650 57.050 40.050 ;
        RECT 58.150 37.350 59.450 46.950 ;
        RECT 64.060 42.350 64.460 47.150 ;
        RECT 65.860 42.350 66.260 47.150 ;
        RECT 68.500 45.750 68.900 47.550 ;
        RECT 70.000 45.750 70.400 47.550 ;
        RECT 71.650 45.800 72.050 47.600 ;
        RECT 68.600 45.300 68.800 45.750 ;
        RECT 70.100 45.300 70.300 45.750 ;
        RECT 68.600 45.100 70.300 45.300 ;
        RECT 70.950 45.350 71.350 45.450 ;
        RECT 71.750 45.350 71.950 45.800 ;
        RECT 70.950 45.150 71.950 45.350 ;
        RECT 69.400 44.800 69.850 45.100 ;
        RECT 70.950 45.050 71.350 45.150 ;
        RECT 68.800 44.500 70.600 44.800 ;
        RECT 71.750 44.500 71.950 45.150 ;
        RECT 68.800 44.100 69.100 44.500 ;
        RECT 70.300 44.100 70.600 44.500 ;
        RECT 63.360 41.350 63.860 41.850 ;
        RECT 64.160 41.750 64.360 42.350 ;
        RECT 65.960 42.050 66.160 42.350 ;
        RECT 65.960 41.850 67.160 42.050 ;
        RECT 66.760 41.750 67.160 41.850 ;
        RECT 68.750 41.800 69.150 44.100 ;
        RECT 70.250 41.800 70.650 44.100 ;
        RECT 64.160 41.350 65.660 41.750 ;
        RECT 66.760 41.450 67.700 41.750 ;
        RECT 64.160 40.950 64.360 41.350 ;
        RECT 66.760 40.950 66.960 41.450 ;
        RECT 67.350 41.200 67.700 41.450 ;
        RECT 57.550 36.650 58.150 36.750 ;
        RECT 56.750 36.350 58.150 36.650 ;
        RECT 57.550 36.250 58.150 36.350 ;
        RECT 58.550 36.350 59.050 37.350 ;
        RECT 64.060 37.250 64.460 40.950 ;
        RECT 65.860 37.250 66.260 40.950 ;
        RECT 66.660 37.250 67.060 40.950 ;
        RECT 71.650 40.700 72.050 44.500 ;
        RECT 72.450 40.700 72.850 44.500 ;
        RECT 77.360 43.650 77.760 44.450 ;
        RECT 78.960 43.650 79.360 44.450 ;
        RECT 77.460 43.250 77.660 43.650 ;
        RECT 79.060 43.350 79.260 43.650 ;
        RECT 78.360 43.250 78.860 43.350 ;
        RECT 77.460 43.050 78.860 43.250 ;
        RECT 79.060 43.150 80.160 43.350 ;
        RECT 78.360 42.950 78.860 43.050 ;
        RECT 77.660 42.650 78.060 42.750 ;
        RECT 77.460 42.450 78.060 42.650 ;
        RECT 77.660 42.350 78.060 42.450 ;
        RECT 78.360 41.750 78.560 42.950 ;
        RECT 79.960 42.850 80.160 43.150 ;
        RECT 80.450 42.850 81.150 42.950 ;
        RECT 79.960 42.450 81.150 42.850 ;
        RECT 79.960 41.750 80.160 42.450 ;
        RECT 80.450 42.250 81.150 42.450 ;
        RECT 83.350 41.850 83.750 47.550 ;
        RECT 77.260 41.250 77.860 41.750 ;
        RECT 78.060 41.250 78.660 41.750 ;
        RECT 79.760 41.250 80.360 41.750 ;
        RECT 82.650 41.250 83.750 41.850 ;
        RECT 72.550 40.450 72.750 40.700 ;
        RECT 69.650 39.850 70.250 40.450 ;
        RECT 72.550 39.750 73.250 40.450 ;
        RECT 83.350 38.450 83.750 41.250 ;
        RECT 59.650 36.550 60.350 37.050 ;
        RECT 58.550 35.950 60.550 36.350 ;
        RECT 48.000 29.200 48.700 29.500 ;
        RECT 48.000 28.800 49.200 29.200 ;
        RECT 50.000 28.800 50.700 29.500 ;
        RECT 58.150 28.950 59.450 35.750 ;
        RECT 59.850 28.950 60.250 35.950 ;
        RECT 64.060 31.150 64.460 34.850 ;
        RECT 65.860 31.150 66.260 34.850 ;
        RECT 66.660 31.150 67.060 34.850 ;
        RECT 67.950 33.850 68.450 34.250 ;
        RECT 74.550 33.850 75.250 34.550 ;
        RECT 68.000 33.800 68.450 33.850 ;
        RECT 63.360 30.350 63.860 30.850 ;
        RECT 64.160 30.750 64.360 31.150 ;
        RECT 64.160 30.350 65.660 30.750 ;
        RECT 66.760 30.450 66.960 31.150 ;
        RECT 64.160 29.750 64.360 30.350 ;
        RECT 66.760 30.300 67.160 30.450 ;
        RECT 68.100 30.300 68.300 33.800 ;
        RECT 66.760 30.250 68.300 30.300 ;
        RECT 65.960 30.100 68.300 30.250 ;
        RECT 65.960 30.050 67.160 30.100 ;
        RECT 65.960 29.750 66.160 30.050 ;
        RECT 48.800 28.500 49.200 28.800 ;
        RECT 48.800 25.700 50.100 28.500 ;
        RECT 50.500 27.300 50.900 28.500 ;
        RECT 50.500 26.500 57.700 27.300 ;
        RECT 50.500 25.200 50.900 26.500 ;
        RECT 46.300 24.800 50.900 25.200 ;
        RECT 46.300 22.300 46.700 24.800 ;
        RECT 45.400 21.500 46.700 22.300 ;
        RECT 56.400 21.500 56.800 26.500 ;
        RECT 57.300 21.500 57.700 26.500 ;
        RECT 64.060 24.950 64.460 29.750 ;
        RECT 65.860 24.950 66.260 29.750 ;
        RECT 69.450 28.050 69.850 33.850 ;
        RECT 70.950 28.050 71.350 33.850 ;
        RECT 72.450 28.050 72.850 33.850 ;
        RECT 74.550 33.550 74.850 33.850 ;
        RECT 69.500 27.450 69.800 28.050 ;
        RECT 71.000 27.450 71.300 28.050 ;
        RECT 72.500 27.450 72.800 28.050 ;
        RECT 73.750 27.750 74.150 33.550 ;
        RECT 74.500 27.750 74.900 33.550 ;
        RECT 69.500 27.250 72.800 27.450 ;
        RECT 70.300 27.000 72.100 27.250 ;
        RECT 73.850 27.050 74.050 27.750 ;
        RECT 70.300 26.350 70.600 27.000 ;
        RECT 71.800 26.350 72.100 27.000 ;
        RECT 72.650 26.650 74.050 27.050 ;
        RECT 70.250 23.550 70.650 26.350 ;
        RECT 71.750 23.550 72.150 26.350 ;
        RECT 73.850 25.750 74.050 26.650 ;
        RECT 73.750 23.950 74.150 25.750 ;
      LAYER met1 ;
        RECT 62.960 112.200 63.460 112.400 ;
        RECT 70.460 112.200 70.860 112.300 ;
        RECT 62.960 112.000 70.860 112.200 ;
        RECT 62.960 111.900 63.460 112.000 ;
        RECT 64.160 107.000 64.360 112.000 ;
        RECT 70.460 111.900 70.860 112.000 ;
        RECT 73.660 112.200 74.160 112.400 ;
        RECT 81.160 112.200 81.560 112.300 ;
        RECT 73.660 112.000 81.560 112.200 ;
        RECT 73.660 111.900 74.160 112.000 ;
        RECT 66.660 107.000 67.060 107.100 ;
        RECT 64.160 106.800 67.060 107.000 ;
        RECT 64.160 106.600 64.360 106.800 ;
        RECT 66.660 106.700 67.060 106.800 ;
        RECT 74.860 107.000 75.060 112.000 ;
        RECT 81.160 111.900 81.560 112.000 ;
        RECT 84.360 112.200 84.860 112.400 ;
        RECT 91.860 112.200 92.260 112.300 ;
        RECT 84.360 112.000 92.260 112.200 ;
        RECT 84.360 111.900 84.860 112.000 ;
        RECT 77.360 107.000 77.760 107.100 ;
        RECT 74.860 106.800 77.760 107.000 ;
        RECT 74.860 106.600 75.060 106.800 ;
        RECT 77.360 106.700 77.760 106.800 ;
        RECT 85.560 107.000 85.760 112.000 ;
        RECT 91.860 111.900 92.260 112.000 ;
        RECT 95.060 112.200 95.560 112.400 ;
        RECT 102.560 112.200 102.960 112.300 ;
        RECT 95.060 112.000 102.960 112.200 ;
        RECT 95.060 111.900 95.560 112.000 ;
        RECT 88.060 107.000 88.460 107.100 ;
        RECT 85.560 106.800 88.460 107.000 ;
        RECT 85.560 106.600 85.760 106.800 ;
        RECT 88.060 106.700 88.460 106.800 ;
        RECT 96.260 107.000 96.460 112.000 ;
        RECT 102.560 111.900 102.960 112.000 ;
        RECT 105.760 112.200 106.260 112.400 ;
        RECT 113.260 112.200 113.660 112.300 ;
        RECT 105.760 112.000 113.660 112.200 ;
        RECT 105.760 111.900 106.260 112.000 ;
        RECT 98.760 107.000 99.160 107.100 ;
        RECT 96.260 106.800 99.160 107.000 ;
        RECT 96.260 106.600 96.460 106.800 ;
        RECT 98.760 106.700 99.160 106.800 ;
        RECT 106.960 107.000 107.160 112.000 ;
        RECT 113.260 111.900 113.660 112.000 ;
        RECT 116.460 112.200 116.960 112.400 ;
        RECT 116.460 112.000 117.860 112.200 ;
        RECT 116.460 111.900 116.960 112.000 ;
        RECT 109.460 107.000 109.860 107.100 ;
        RECT 106.960 106.800 109.860 107.000 ;
        RECT 106.960 106.600 107.160 106.800 ;
        RECT 109.460 106.700 109.860 106.800 ;
        RECT 117.660 107.000 117.860 112.000 ;
        RECT 120.160 107.000 120.560 107.100 ;
        RECT 117.660 106.800 120.560 107.000 ;
        RECT 117.660 106.600 117.860 106.800 ;
        RECT 120.160 106.700 120.560 106.800 ;
        RECT 48.360 105.700 48.960 106.300 ;
        RECT 56.960 105.700 57.560 106.300 ;
        RECT 64.060 106.200 64.460 106.600 ;
        RECT 67.660 105.700 68.260 106.300 ;
        RECT 74.760 106.200 75.160 106.600 ;
        RECT 78.360 105.700 78.960 106.300 ;
        RECT 85.460 106.200 85.860 106.600 ;
        RECT 89.060 105.700 89.660 106.300 ;
        RECT 96.160 106.200 96.560 106.600 ;
        RECT 99.760 105.700 100.360 106.300 ;
        RECT 106.860 106.200 107.260 106.600 ;
        RECT 110.460 105.700 111.060 106.300 ;
        RECT 117.560 106.200 117.960 106.600 ;
        RECT 121.160 105.700 121.760 106.300 ;
        RECT 46.360 97.700 46.760 98.000 ;
        RECT 44.660 97.600 46.760 97.700 ;
        RECT 44.660 97.500 46.660 97.600 ;
        RECT 44.660 84.000 44.860 97.500 ;
        RECT 47.160 97.100 47.760 97.700 ;
        RECT 47.960 97.600 48.560 98.200 ;
        RECT 48.160 96.500 48.360 97.600 ;
        RECT 49.960 97.500 50.560 98.100 ;
        RECT 54.960 97.700 55.360 98.000 ;
        RECT 50.860 97.100 51.460 97.700 ;
        RECT 53.260 97.600 55.360 97.700 ;
        RECT 53.260 97.500 55.260 97.600 ;
        RECT 45.560 96.300 48.360 96.500 ;
        RECT 45.560 91.500 45.760 96.300 ;
        RECT 46.360 91.600 46.760 92.000 ;
        RECT 45.460 91.100 45.860 91.500 ;
        RECT 45.360 84.800 45.960 85.400 ;
        RECT 46.460 84.900 46.660 91.600 ;
        RECT 47.960 91.400 48.560 92.000 ;
        RECT 50.060 91.600 50.460 92.000 ;
        RECT 50.060 89.100 50.260 91.600 ;
        RECT 51.660 91.400 52.260 92.000 ;
        RECT 49.260 88.900 50.260 89.100 ;
        RECT 49.260 85.300 49.460 88.900 ;
        RECT 49.160 85.000 49.560 85.300 ;
        RECT 47.960 84.900 49.560 85.000 ;
        RECT 46.260 84.300 46.860 84.900 ;
        RECT 47.960 84.800 49.360 84.900 ;
        RECT 47.960 84.400 48.560 84.800 ;
        RECT 47.260 84.000 47.660 84.400 ;
        RECT 49.960 84.300 50.560 84.900 ;
        RECT 51.660 84.400 52.260 85.000 ;
        RECT 44.660 83.800 47.560 84.000 ;
        RECT 47.360 83.300 47.560 83.800 ;
        RECT 51.960 83.300 52.160 84.400 ;
        RECT 53.260 84.000 53.460 97.500 ;
        RECT 55.760 97.100 56.360 97.700 ;
        RECT 56.560 97.600 57.160 98.200 ;
        RECT 56.760 96.500 56.960 97.600 ;
        RECT 58.560 97.500 59.160 98.100 ;
        RECT 65.660 97.700 66.060 98.000 ;
        RECT 59.460 97.100 60.060 97.700 ;
        RECT 63.960 97.600 66.060 97.700 ;
        RECT 63.960 97.500 65.960 97.600 ;
        RECT 54.160 96.300 56.960 96.500 ;
        RECT 54.160 91.500 54.360 96.300 ;
        RECT 54.960 91.600 55.360 92.000 ;
        RECT 54.060 91.100 54.460 91.500 ;
        RECT 53.960 84.800 54.560 85.400 ;
        RECT 55.060 84.900 55.260 91.600 ;
        RECT 56.560 91.400 57.160 92.000 ;
        RECT 58.660 91.600 59.060 92.000 ;
        RECT 58.660 89.100 58.860 91.600 ;
        RECT 60.260 91.400 60.860 92.000 ;
        RECT 57.860 88.900 58.860 89.100 ;
        RECT 57.860 85.300 58.060 88.900 ;
        RECT 57.760 85.000 58.160 85.300 ;
        RECT 56.560 84.900 58.160 85.000 ;
        RECT 54.860 84.300 55.460 84.900 ;
        RECT 56.560 84.800 57.960 84.900 ;
        RECT 56.560 84.400 57.160 84.800 ;
        RECT 55.860 84.000 56.260 84.400 ;
        RECT 58.560 84.300 59.160 84.900 ;
        RECT 60.260 84.400 60.860 85.000 ;
        RECT 53.260 83.800 56.160 84.000 ;
        RECT 47.360 83.100 52.160 83.300 ;
        RECT 55.960 83.300 56.160 83.800 ;
        RECT 60.560 83.300 60.760 84.400 ;
        RECT 63.960 84.000 64.160 97.500 ;
        RECT 66.460 97.100 67.060 97.700 ;
        RECT 67.260 97.600 67.860 98.200 ;
        RECT 67.460 96.500 67.660 97.600 ;
        RECT 69.260 97.500 69.860 98.100 ;
        RECT 76.360 97.700 76.760 98.000 ;
        RECT 70.160 97.100 70.760 97.700 ;
        RECT 74.660 97.600 76.760 97.700 ;
        RECT 74.660 97.500 76.660 97.600 ;
        RECT 64.860 96.300 67.660 96.500 ;
        RECT 64.860 91.500 65.060 96.300 ;
        RECT 65.660 91.600 66.060 92.000 ;
        RECT 64.760 91.100 65.160 91.500 ;
        RECT 64.660 84.800 65.260 85.400 ;
        RECT 65.760 84.900 65.960 91.600 ;
        RECT 67.260 91.400 67.860 92.000 ;
        RECT 69.360 91.600 69.760 92.000 ;
        RECT 69.360 89.100 69.560 91.600 ;
        RECT 70.960 91.400 71.560 92.000 ;
        RECT 68.560 88.900 69.560 89.100 ;
        RECT 68.560 85.300 68.760 88.900 ;
        RECT 68.460 85.000 68.860 85.300 ;
        RECT 67.260 84.900 68.860 85.000 ;
        RECT 65.560 84.300 66.160 84.900 ;
        RECT 67.260 84.800 68.660 84.900 ;
        RECT 67.260 84.400 67.860 84.800 ;
        RECT 66.560 84.000 66.960 84.400 ;
        RECT 69.260 84.300 69.860 84.900 ;
        RECT 70.960 84.400 71.560 85.000 ;
        RECT 63.960 83.800 66.860 84.000 ;
        RECT 55.960 83.100 60.760 83.300 ;
        RECT 66.660 83.300 66.860 83.800 ;
        RECT 71.260 83.300 71.460 84.400 ;
        RECT 74.660 84.000 74.860 97.500 ;
        RECT 77.160 97.100 77.760 97.700 ;
        RECT 77.960 97.600 78.560 98.200 ;
        RECT 78.160 96.500 78.360 97.600 ;
        RECT 79.960 97.500 80.560 98.100 ;
        RECT 87.060 97.700 87.460 98.000 ;
        RECT 80.860 97.100 81.460 97.700 ;
        RECT 85.360 97.600 87.460 97.700 ;
        RECT 85.360 97.500 87.360 97.600 ;
        RECT 75.560 96.300 78.360 96.500 ;
        RECT 75.560 91.500 75.760 96.300 ;
        RECT 76.360 91.600 76.760 92.000 ;
        RECT 75.460 91.100 75.860 91.500 ;
        RECT 75.360 84.800 75.960 85.400 ;
        RECT 76.460 84.900 76.660 91.600 ;
        RECT 77.960 91.400 78.560 92.000 ;
        RECT 80.060 91.600 80.460 92.000 ;
        RECT 80.060 89.100 80.260 91.600 ;
        RECT 81.660 91.400 82.260 92.000 ;
        RECT 79.260 88.900 80.260 89.100 ;
        RECT 79.260 85.300 79.460 88.900 ;
        RECT 79.160 85.000 79.560 85.300 ;
        RECT 77.960 84.900 79.560 85.000 ;
        RECT 76.260 84.300 76.860 84.900 ;
        RECT 77.960 84.800 79.360 84.900 ;
        RECT 77.960 84.400 78.560 84.800 ;
        RECT 77.260 84.000 77.660 84.400 ;
        RECT 79.960 84.300 80.560 84.900 ;
        RECT 81.660 84.400 82.260 85.000 ;
        RECT 74.660 83.800 77.560 84.000 ;
        RECT 66.660 83.100 71.460 83.300 ;
        RECT 77.360 83.300 77.560 83.800 ;
        RECT 81.960 83.300 82.160 84.400 ;
        RECT 85.360 84.000 85.560 97.500 ;
        RECT 87.860 97.100 88.460 97.700 ;
        RECT 88.660 97.600 89.260 98.200 ;
        RECT 88.860 96.500 89.060 97.600 ;
        RECT 90.660 97.500 91.260 98.100 ;
        RECT 97.760 97.700 98.160 98.000 ;
        RECT 91.560 97.100 92.160 97.700 ;
        RECT 96.060 97.600 98.160 97.700 ;
        RECT 96.060 97.500 98.060 97.600 ;
        RECT 86.260 96.300 89.060 96.500 ;
        RECT 86.260 91.500 86.460 96.300 ;
        RECT 87.060 91.600 87.460 92.000 ;
        RECT 86.160 91.100 86.560 91.500 ;
        RECT 86.060 84.800 86.660 85.400 ;
        RECT 87.160 84.900 87.360 91.600 ;
        RECT 88.660 91.400 89.260 92.000 ;
        RECT 90.760 91.600 91.160 92.000 ;
        RECT 90.760 89.100 90.960 91.600 ;
        RECT 92.360 91.400 92.960 92.000 ;
        RECT 89.960 88.900 90.960 89.100 ;
        RECT 89.960 85.300 90.160 88.900 ;
        RECT 89.860 85.000 90.260 85.300 ;
        RECT 88.660 84.900 90.260 85.000 ;
        RECT 86.960 84.300 87.560 84.900 ;
        RECT 88.660 84.800 90.060 84.900 ;
        RECT 88.660 84.400 89.260 84.800 ;
        RECT 87.960 84.000 88.360 84.400 ;
        RECT 90.660 84.300 91.260 84.900 ;
        RECT 92.360 84.400 92.960 85.000 ;
        RECT 85.360 83.800 88.260 84.000 ;
        RECT 77.360 83.100 82.160 83.300 ;
        RECT 88.060 83.300 88.260 83.800 ;
        RECT 92.660 83.300 92.860 84.400 ;
        RECT 96.060 84.000 96.260 97.500 ;
        RECT 98.560 97.100 99.160 97.700 ;
        RECT 99.360 97.600 99.960 98.200 ;
        RECT 99.560 96.500 99.760 97.600 ;
        RECT 101.360 97.500 101.960 98.100 ;
        RECT 108.460 97.700 108.860 98.000 ;
        RECT 102.260 97.100 102.860 97.700 ;
        RECT 106.760 97.600 108.860 97.700 ;
        RECT 106.760 97.500 108.760 97.600 ;
        RECT 96.960 96.300 99.760 96.500 ;
        RECT 96.960 91.500 97.160 96.300 ;
        RECT 97.760 91.600 98.160 92.000 ;
        RECT 96.860 91.100 97.260 91.500 ;
        RECT 96.760 84.800 97.360 85.400 ;
        RECT 97.860 84.900 98.060 91.600 ;
        RECT 99.360 91.400 99.960 92.000 ;
        RECT 101.460 91.600 101.860 92.000 ;
        RECT 101.460 89.100 101.660 91.600 ;
        RECT 103.060 91.400 103.660 92.000 ;
        RECT 100.660 88.900 101.660 89.100 ;
        RECT 100.660 85.300 100.860 88.900 ;
        RECT 100.560 85.000 100.960 85.300 ;
        RECT 99.360 84.900 100.960 85.000 ;
        RECT 97.660 84.300 98.260 84.900 ;
        RECT 99.360 84.800 100.760 84.900 ;
        RECT 99.360 84.400 99.960 84.800 ;
        RECT 98.660 84.000 99.060 84.400 ;
        RECT 101.360 84.300 101.960 84.900 ;
        RECT 103.060 84.400 103.660 85.000 ;
        RECT 96.060 83.800 98.960 84.000 ;
        RECT 88.060 83.100 92.860 83.300 ;
        RECT 98.760 83.300 98.960 83.800 ;
        RECT 103.360 83.300 103.560 84.400 ;
        RECT 106.760 84.000 106.960 97.500 ;
        RECT 109.260 97.100 109.860 97.700 ;
        RECT 110.060 97.600 110.660 98.200 ;
        RECT 110.260 96.500 110.460 97.600 ;
        RECT 112.060 97.500 112.660 98.100 ;
        RECT 119.160 97.700 119.560 98.000 ;
        RECT 112.960 97.100 113.560 97.700 ;
        RECT 117.460 97.600 119.560 97.700 ;
        RECT 117.460 97.500 119.460 97.600 ;
        RECT 107.660 96.300 110.460 96.500 ;
        RECT 107.660 91.500 107.860 96.300 ;
        RECT 108.460 91.600 108.860 92.000 ;
        RECT 107.560 91.100 107.960 91.500 ;
        RECT 107.460 84.800 108.060 85.400 ;
        RECT 108.560 84.900 108.760 91.600 ;
        RECT 110.060 91.400 110.660 92.000 ;
        RECT 112.160 91.600 112.560 92.000 ;
        RECT 112.160 89.100 112.360 91.600 ;
        RECT 113.760 91.400 114.360 92.000 ;
        RECT 111.360 88.900 112.360 89.100 ;
        RECT 111.360 85.300 111.560 88.900 ;
        RECT 111.260 85.000 111.660 85.300 ;
        RECT 110.060 84.900 111.660 85.000 ;
        RECT 108.360 84.300 108.960 84.900 ;
        RECT 110.060 84.800 111.460 84.900 ;
        RECT 110.060 84.400 110.660 84.800 ;
        RECT 109.360 84.000 109.760 84.400 ;
        RECT 112.060 84.300 112.660 84.900 ;
        RECT 113.760 84.400 114.360 85.000 ;
        RECT 106.760 83.800 109.660 84.000 ;
        RECT 98.760 83.100 103.560 83.300 ;
        RECT 109.460 83.300 109.660 83.800 ;
        RECT 114.060 83.300 114.260 84.400 ;
        RECT 117.460 84.000 117.660 97.500 ;
        RECT 119.960 97.100 120.560 97.700 ;
        RECT 120.760 97.600 121.360 98.200 ;
        RECT 120.960 96.500 121.160 97.600 ;
        RECT 122.760 97.500 123.360 98.100 ;
        RECT 123.660 97.100 124.260 97.700 ;
        RECT 118.360 96.300 121.160 96.500 ;
        RECT 118.360 91.500 118.560 96.300 ;
        RECT 119.160 91.600 119.560 92.000 ;
        RECT 118.260 91.100 118.660 91.500 ;
        RECT 118.160 84.800 118.760 85.400 ;
        RECT 119.260 84.900 119.460 91.600 ;
        RECT 120.760 91.400 121.360 92.000 ;
        RECT 122.860 91.600 123.260 92.000 ;
        RECT 122.860 89.100 123.060 91.600 ;
        RECT 124.460 91.400 125.060 92.000 ;
        RECT 122.060 88.900 123.060 89.100 ;
        RECT 122.060 85.300 122.260 88.900 ;
        RECT 121.960 85.000 122.360 85.300 ;
        RECT 120.760 84.900 122.360 85.000 ;
        RECT 119.060 84.300 119.660 84.900 ;
        RECT 120.760 84.800 122.160 84.900 ;
        RECT 120.760 84.400 121.360 84.800 ;
        RECT 120.060 84.000 120.460 84.400 ;
        RECT 122.760 84.300 123.360 84.900 ;
        RECT 124.460 84.400 125.060 85.000 ;
        RECT 117.460 83.800 120.360 84.000 ;
        RECT 109.460 83.100 114.260 83.300 ;
        RECT 120.160 83.300 120.360 83.800 ;
        RECT 124.760 83.300 124.960 84.400 ;
        RECT 120.160 83.100 124.960 83.300 ;
        RECT 87.050 66.950 87.450 67.050 ;
        RECT 78.250 66.750 87.450 66.950 ;
        RECT 78.250 66.550 78.450 66.750 ;
        RECT 87.050 66.650 87.450 66.750 ;
        RECT 78.150 66.150 78.550 66.550 ;
        RECT 84.600 61.650 85.300 61.700 ;
        RECT 83.350 61.050 83.850 61.550 ;
        RECT 84.550 60.950 85.300 61.650 ;
        RECT 80.450 60.850 80.850 60.950 ;
        RECT 76.250 60.650 80.850 60.850 ;
        RECT 76.150 60.250 76.550 60.650 ;
        RECT 80.450 60.550 80.850 60.650 ;
        RECT 82.150 60.550 82.550 60.950 ;
        RECT 84.600 60.900 85.300 60.950 ;
        RECT 77.850 59.450 78.350 59.950 ;
        RECT 71.850 57.850 72.550 58.550 ;
        RECT 78.350 58.350 78.750 58.450 ;
        RECT 82.250 58.350 82.450 60.550 ;
        RECT 78.350 58.150 82.450 58.350 ;
        RECT 78.350 58.050 78.750 58.150 ;
        RECT 44.950 57.050 45.650 57.250 ;
        RECT 44.950 56.750 53.750 57.050 ;
        RECT 44.950 56.550 45.650 56.750 ;
        RECT 48.550 55.150 49.150 55.750 ;
        RECT 53.450 52.850 53.750 56.750 ;
        RECT 60.500 54.850 61.200 55.550 ;
        RECT 61.550 55.250 63.960 55.750 ;
        RECT 53.450 52.550 60.950 52.850 ;
        RECT 60.650 51.200 60.950 52.550 ;
        RECT 60.400 51.150 61.150 51.200 ;
        RECT 60.400 50.500 61.200 51.150 ;
        RECT 60.500 50.450 61.200 50.500 ;
        RECT 47.350 40.050 48.050 40.550 ;
        RECT 61.550 38.750 61.950 55.250 ;
        RECT 67.550 53.450 68.150 54.150 ;
        RECT 80.500 42.950 81.200 43.000 ;
        RECT 77.550 42.250 78.050 42.750 ;
        RECT 80.450 42.250 81.200 42.950 ;
        RECT 80.500 42.200 81.200 42.250 ;
        RECT 63.360 41.750 63.860 41.850 ;
        RECT 62.150 41.450 63.860 41.750 ;
        RECT 62.150 38.750 62.550 41.450 ;
        RECT 63.360 41.350 63.860 41.450 ;
        RECT 82.650 41.250 83.350 41.850 ;
        RECT 69.650 40.150 70.250 40.450 ;
        RECT 69.650 39.850 71.750 40.150 ;
        RECT 58.650 38.450 62.550 38.750 ;
        RECT 58.650 36.550 58.950 38.450 ;
        RECT 59.650 36.550 60.350 37.050 ;
        RECT 58.550 35.950 59.050 36.550 ;
        RECT 54.250 33.750 54.750 33.850 ;
        RECT 48.250 33.200 48.800 33.750 ;
        RECT 51.250 33.200 51.800 33.750 ;
        RECT 54.250 33.200 54.800 33.750 ;
        RECT 44.950 32.450 45.650 33.150 ;
        RECT 61.550 30.850 61.950 38.450 ;
        RECT 71.450 37.650 71.750 39.850 ;
        RECT 72.550 39.750 73.250 40.450 ;
        RECT 82.650 37.650 82.950 41.250 ;
        RECT 71.450 37.350 82.950 37.650 ;
        RECT 74.550 33.850 75.250 34.550 ;
        RECT 61.550 30.350 63.860 30.850 ;
        RECT 48.000 28.800 48.700 29.500 ;
        RECT 50.000 28.800 50.750 29.500 ;
      LAYER met2 ;
        RECT 48.360 105.700 48.960 106.300 ;
        RECT 56.960 105.700 57.560 106.300 ;
        RECT 67.660 105.700 68.260 106.300 ;
        RECT 78.360 105.700 78.960 106.300 ;
        RECT 89.060 105.700 89.660 106.300 ;
        RECT 99.760 105.700 100.360 106.300 ;
        RECT 110.460 105.700 111.060 106.300 ;
        RECT 121.160 105.700 121.760 106.300 ;
        RECT 47.160 97.500 47.760 97.700 ;
        RECT 49.960 97.500 50.560 98.100 ;
        RECT 47.160 97.300 50.260 97.500 ;
        RECT 47.160 97.100 47.760 97.300 ;
        RECT 50.860 97.100 51.460 97.700 ;
        RECT 55.760 97.500 56.360 97.700 ;
        RECT 58.560 97.500 59.160 98.100 ;
        RECT 55.760 97.300 58.860 97.500 ;
        RECT 55.760 97.100 56.360 97.300 ;
        RECT 59.460 97.100 60.060 97.700 ;
        RECT 66.460 97.500 67.060 97.700 ;
        RECT 69.260 97.500 69.860 98.100 ;
        RECT 66.460 97.300 69.560 97.500 ;
        RECT 66.460 97.100 67.060 97.300 ;
        RECT 70.160 97.100 70.760 97.700 ;
        RECT 77.160 97.500 77.760 97.700 ;
        RECT 79.960 97.500 80.560 98.100 ;
        RECT 77.160 97.300 80.260 97.500 ;
        RECT 77.160 97.100 77.760 97.300 ;
        RECT 80.860 97.100 81.460 97.700 ;
        RECT 87.860 97.500 88.460 97.700 ;
        RECT 90.660 97.500 91.260 98.100 ;
        RECT 87.860 97.300 90.960 97.500 ;
        RECT 87.860 97.100 88.460 97.300 ;
        RECT 91.560 97.100 92.160 97.700 ;
        RECT 98.560 97.500 99.160 97.700 ;
        RECT 101.360 97.500 101.960 98.100 ;
        RECT 98.560 97.300 101.660 97.500 ;
        RECT 98.560 97.100 99.160 97.300 ;
        RECT 102.260 97.100 102.860 97.700 ;
        RECT 109.260 97.500 109.860 97.700 ;
        RECT 112.060 97.500 112.660 98.100 ;
        RECT 109.260 97.300 112.360 97.500 ;
        RECT 109.260 97.100 109.860 97.300 ;
        RECT 112.960 97.100 113.560 97.700 ;
        RECT 119.960 97.500 120.560 97.700 ;
        RECT 122.760 97.500 123.360 98.100 ;
        RECT 119.960 97.300 123.060 97.500 ;
        RECT 119.960 97.100 120.560 97.300 ;
        RECT 123.660 97.100 124.260 97.700 ;
        RECT 47.360 95.800 47.560 97.100 ;
        RECT 47.360 95.600 48.360 95.800 ;
        RECT 48.160 92.000 48.360 95.600 ;
        RECT 51.060 95.700 51.260 97.100 ;
        RECT 55.960 95.800 56.160 97.100 ;
        RECT 51.060 95.500 52.060 95.700 ;
        RECT 55.960 95.600 56.960 95.800 ;
        RECT 51.860 92.000 52.060 95.500 ;
        RECT 56.760 92.000 56.960 95.600 ;
        RECT 59.660 95.700 59.860 97.100 ;
        RECT 66.660 95.800 66.860 97.100 ;
        RECT 59.660 95.500 60.660 95.700 ;
        RECT 66.660 95.600 67.660 95.800 ;
        RECT 60.460 92.000 60.660 95.500 ;
        RECT 67.460 92.000 67.660 95.600 ;
        RECT 70.360 95.700 70.560 97.100 ;
        RECT 77.360 95.800 77.560 97.100 ;
        RECT 70.360 95.500 71.360 95.700 ;
        RECT 77.360 95.600 78.360 95.800 ;
        RECT 71.160 92.000 71.360 95.500 ;
        RECT 78.160 92.000 78.360 95.600 ;
        RECT 81.060 95.700 81.260 97.100 ;
        RECT 88.060 95.800 88.260 97.100 ;
        RECT 81.060 95.500 82.060 95.700 ;
        RECT 88.060 95.600 89.060 95.800 ;
        RECT 81.860 92.000 82.060 95.500 ;
        RECT 88.860 92.000 89.060 95.600 ;
        RECT 91.760 95.700 91.960 97.100 ;
        RECT 98.760 95.800 98.960 97.100 ;
        RECT 91.760 95.500 92.760 95.700 ;
        RECT 98.760 95.600 99.760 95.800 ;
        RECT 92.560 92.000 92.760 95.500 ;
        RECT 99.560 92.000 99.760 95.600 ;
        RECT 102.460 95.700 102.660 97.100 ;
        RECT 109.460 95.800 109.660 97.100 ;
        RECT 102.460 95.500 103.460 95.700 ;
        RECT 109.460 95.600 110.460 95.800 ;
        RECT 103.260 92.000 103.460 95.500 ;
        RECT 110.260 92.000 110.460 95.600 ;
        RECT 113.160 95.700 113.360 97.100 ;
        RECT 120.160 95.800 120.360 97.100 ;
        RECT 113.160 95.500 114.160 95.700 ;
        RECT 120.160 95.600 121.160 95.800 ;
        RECT 113.960 92.000 114.160 95.500 ;
        RECT 120.960 92.000 121.160 95.600 ;
        RECT 123.860 95.700 124.060 97.100 ;
        RECT 123.860 95.500 124.860 95.700 ;
        RECT 124.660 92.000 124.860 95.500 ;
        RECT 47.960 91.400 48.560 92.000 ;
        RECT 51.660 91.400 52.260 92.000 ;
        RECT 56.560 91.400 57.160 92.000 ;
        RECT 60.260 91.400 60.860 92.000 ;
        RECT 67.260 91.400 67.860 92.000 ;
        RECT 70.960 91.400 71.560 92.000 ;
        RECT 77.960 91.400 78.560 92.000 ;
        RECT 81.660 91.400 82.260 92.000 ;
        RECT 88.660 91.400 89.260 92.000 ;
        RECT 92.360 91.400 92.960 92.000 ;
        RECT 99.360 91.400 99.960 92.000 ;
        RECT 103.060 91.400 103.660 92.000 ;
        RECT 110.060 91.400 110.660 92.000 ;
        RECT 113.760 91.400 114.360 92.000 ;
        RECT 120.760 91.400 121.360 92.000 ;
        RECT 124.460 91.400 125.060 92.000 ;
        RECT 48.160 90.100 48.360 91.400 ;
        RECT 56.760 90.100 56.960 91.400 ;
        RECT 67.460 90.100 67.660 91.400 ;
        RECT 78.160 90.100 78.360 91.400 ;
        RECT 88.860 90.100 89.060 91.400 ;
        RECT 99.560 90.100 99.760 91.400 ;
        RECT 110.260 90.100 110.460 91.400 ;
        RECT 120.960 90.100 121.160 91.400 ;
        RECT 45.560 89.900 48.360 90.100 ;
        RECT 54.160 89.900 56.960 90.100 ;
        RECT 64.860 89.900 67.660 90.100 ;
        RECT 75.560 89.900 78.360 90.100 ;
        RECT 86.260 89.900 89.060 90.100 ;
        RECT 96.960 89.900 99.760 90.100 ;
        RECT 107.660 89.900 110.460 90.100 ;
        RECT 118.360 89.900 121.160 90.100 ;
        RECT 45.560 85.400 45.760 89.900 ;
        RECT 54.160 85.400 54.360 89.900 ;
        RECT 64.860 85.400 65.060 89.900 ;
        RECT 75.560 85.400 75.760 89.900 ;
        RECT 86.260 85.400 86.460 89.900 ;
        RECT 96.960 85.400 97.160 89.900 ;
        RECT 107.660 85.400 107.860 89.900 ;
        RECT 118.360 85.400 118.560 89.900 ;
        RECT 45.360 84.800 45.960 85.400 ;
        RECT 43.550 84.500 44.160 84.700 ;
        RECT 46.260 84.500 46.860 84.900 ;
        RECT 43.550 84.300 46.860 84.500 ;
        RECT 49.960 84.300 50.560 84.900 ;
        RECT 53.960 84.800 54.560 85.400 ;
        RECT 54.860 84.500 55.460 84.900 ;
        RECT 52.460 84.300 55.460 84.500 ;
        RECT 58.560 84.300 59.160 84.900 ;
        RECT 64.660 84.800 65.260 85.400 ;
        RECT 65.560 84.500 66.160 84.900 ;
        RECT 63.460 84.300 66.160 84.500 ;
        RECT 69.260 84.300 69.860 84.900 ;
        RECT 75.360 84.800 75.960 85.400 ;
        RECT 76.260 84.500 76.860 84.900 ;
        RECT 74.160 84.300 76.860 84.500 ;
        RECT 79.960 84.300 80.560 84.900 ;
        RECT 86.060 84.800 86.660 85.400 ;
        RECT 86.960 84.500 87.560 84.900 ;
        RECT 84.860 84.300 87.560 84.500 ;
        RECT 90.660 84.300 91.260 84.900 ;
        RECT 96.760 84.800 97.360 85.400 ;
        RECT 97.660 84.500 98.260 84.900 ;
        RECT 95.560 84.300 98.260 84.500 ;
        RECT 101.360 84.300 101.960 84.900 ;
        RECT 107.460 84.800 108.060 85.400 ;
        RECT 108.360 84.500 108.960 84.900 ;
        RECT 106.260 84.300 108.960 84.500 ;
        RECT 112.060 84.300 112.660 84.900 ;
        RECT 118.160 84.800 118.760 85.400 ;
        RECT 119.060 84.500 119.660 84.900 ;
        RECT 116.960 84.300 119.660 84.500 ;
        RECT 122.760 84.300 123.360 84.900 ;
        RECT 43.550 84.100 44.160 84.300 ;
        RECT 44.760 82.700 44.960 84.300 ;
        RECT 52.460 82.700 52.660 84.300 ;
        RECT 63.460 82.700 63.660 84.300 ;
        RECT 74.160 82.700 74.360 84.300 ;
        RECT 84.860 82.700 85.060 84.300 ;
        RECT 95.560 82.700 95.760 84.300 ;
        RECT 106.260 82.700 106.460 84.300 ;
        RECT 116.960 82.700 117.160 84.300 ;
        RECT 44.760 82.500 117.160 82.700 ;
        RECT 60.850 64.150 85.490 64.450 ;
        RECT 60.850 62.750 61.150 64.150 ;
        RECT 59.090 62.450 61.150 62.750 ;
        RECT 44.950 56.550 45.650 57.250 ;
        RECT 48.550 55.600 49.150 55.750 ;
        RECT 59.100 55.600 59.500 62.450 ;
        RECT 85.190 61.650 85.490 64.150 ;
        RECT 84.550 61.550 85.490 61.650 ;
        RECT 83.350 61.050 83.850 61.550 ;
        RECT 84.550 61.050 85.500 61.550 ;
        RECT 77.850 59.850 78.350 59.950 ;
        RECT 83.450 59.850 83.750 61.050 ;
        RECT 84.550 60.950 85.490 61.050 ;
        RECT 77.850 59.550 83.750 59.850 ;
        RECT 77.850 59.450 78.350 59.550 ;
        RECT 71.850 58.400 72.550 58.550 ;
        RECT 48.550 55.200 59.500 55.600 ;
        RECT 60.600 58.050 75.100 58.400 ;
        RECT 60.600 55.550 61.000 58.050 ;
        RECT 71.850 57.850 72.550 58.050 ;
        RECT 48.550 55.150 49.150 55.200 ;
        RECT 60.500 54.850 61.200 55.550 ;
        RECT 67.550 53.450 68.150 54.150 ;
        RECT 60.500 50.450 61.200 51.150 ;
        RECT 47.350 40.050 48.050 40.550 ;
        RECT 47.650 39.350 47.950 40.050 ;
        RECT 69.650 39.850 70.250 40.450 ;
        RECT 72.550 40.250 73.250 40.450 ;
        RECT 74.700 40.250 75.100 58.050 ;
        RECT 85.190 46.950 85.490 60.950 ;
        RECT 77.550 46.650 85.490 46.950 ;
        RECT 77.550 42.750 77.850 46.650 ;
        RECT 77.550 42.250 78.050 42.750 ;
        RECT 80.450 42.250 81.150 42.950 ;
        RECT 72.550 39.950 75.100 40.250 ;
        RECT 72.550 39.750 73.250 39.950 ;
        RECT 47.650 39.050 60.350 39.350 ;
        RECT 60.050 37.050 60.350 39.050 ;
        RECT 58.550 35.950 59.050 36.550 ;
        RECT 59.650 36.450 60.350 37.050 ;
        RECT 74.700 34.550 75.100 39.950 ;
        RECT 74.550 33.850 75.250 34.550 ;
        RECT 48.250 33.600 48.800 33.750 ;
        RECT 51.250 33.600 51.800 33.750 ;
        RECT 54.250 33.600 54.800 33.750 ;
        RECT 48.250 33.350 54.800 33.600 ;
        RECT 48.250 33.200 48.800 33.350 ;
        RECT 51.250 33.200 51.800 33.350 ;
        RECT 54.250 33.200 54.800 33.350 ;
        RECT 44.950 32.450 45.650 33.150 ;
        RECT 48.250 29.550 48.650 33.200 ;
        RECT 47.950 28.800 48.700 29.550 ;
        RECT 50.000 28.800 50.700 29.500 ;
      LAYER met3 ;
        RECT 48.360 105.700 48.960 106.300 ;
        RECT 56.960 105.700 57.560 106.300 ;
        RECT 67.660 105.700 68.260 106.300 ;
        RECT 78.360 105.700 78.960 106.300 ;
        RECT 89.060 105.700 89.660 106.300 ;
        RECT 99.760 105.700 100.360 106.300 ;
        RECT 110.460 105.700 111.060 106.300 ;
        RECT 121.160 105.700 121.760 106.300 ;
        RECT 48.560 84.700 48.860 105.700 ;
        RECT 49.960 84.700 50.560 84.900 ;
        RECT 43.550 84.100 44.150 84.700 ;
        RECT 48.560 84.400 50.560 84.700 ;
        RECT 57.160 84.700 57.460 105.700 ;
        RECT 58.560 84.700 59.160 84.900 ;
        RECT 57.160 84.400 59.160 84.700 ;
        RECT 67.860 84.700 68.160 105.700 ;
        RECT 69.260 84.700 69.860 84.900 ;
        RECT 67.860 84.400 69.860 84.700 ;
        RECT 78.560 84.700 78.860 105.700 ;
        RECT 79.960 84.700 80.560 84.900 ;
        RECT 78.560 84.400 80.560 84.700 ;
        RECT 89.260 84.700 89.560 105.700 ;
        RECT 90.660 84.700 91.260 84.900 ;
        RECT 89.260 84.400 91.260 84.700 ;
        RECT 99.960 84.700 100.260 105.700 ;
        RECT 101.360 84.700 101.960 84.900 ;
        RECT 99.960 84.400 101.960 84.700 ;
        RECT 110.660 84.700 110.960 105.700 ;
        RECT 112.060 84.700 112.660 84.900 ;
        RECT 110.660 84.400 112.660 84.700 ;
        RECT 121.360 84.700 121.660 105.700 ;
        RECT 122.760 84.700 123.360 84.900 ;
        RECT 121.360 84.400 123.360 84.700 ;
        RECT 49.960 84.300 50.560 84.400 ;
        RECT 58.560 84.300 59.160 84.400 ;
        RECT 69.260 84.300 69.860 84.400 ;
        RECT 79.960 84.300 80.560 84.400 ;
        RECT 90.660 84.300 91.260 84.400 ;
        RECT 101.360 84.300 101.960 84.400 ;
        RECT 112.060 84.300 112.660 84.400 ;
        RECT 122.760 84.300 123.360 84.400 ;
        RECT 43.650 70.950 44.050 84.100 ;
        RECT 43.650 70.550 81.150 70.950 ;
        RECT 43.650 70.500 44.050 70.550 ;
        RECT 80.750 69.350 81.150 70.550 ;
        RECT 80.740 69.250 81.150 69.350 ;
        RECT 80.740 67.850 81.140 69.250 ;
        RECT 80.740 67.750 81.150 67.850 ;
        RECT 44.950 56.550 45.650 57.250 ;
        RECT 80.750 42.950 81.150 67.750 ;
        RECT 84.550 60.950 85.250 61.650 ;
        RECT 77.550 42.350 78.150 42.750 ;
        RECT 73.250 42.050 78.150 42.350 ;
        RECT 80.450 42.250 81.150 42.950 ;
        RECT 69.650 39.850 70.250 40.450 ;
        RECT 59.650 36.450 60.350 37.050 ;
        RECT 44.950 32.450 45.650 33.150 ;
        RECT 45.350 30.350 45.650 32.450 ;
        RECT 45.350 30.050 49.550 30.350 ;
        RECT 49.250 29.550 49.550 30.050 ;
        RECT 73.250 29.550 73.550 42.050 ;
        RECT 49.250 29.250 73.550 29.550 ;
        RECT 49.950 28.750 50.750 29.250 ;
  END
END tt_um_irfantekin_analog_readout
END LIBRARY

